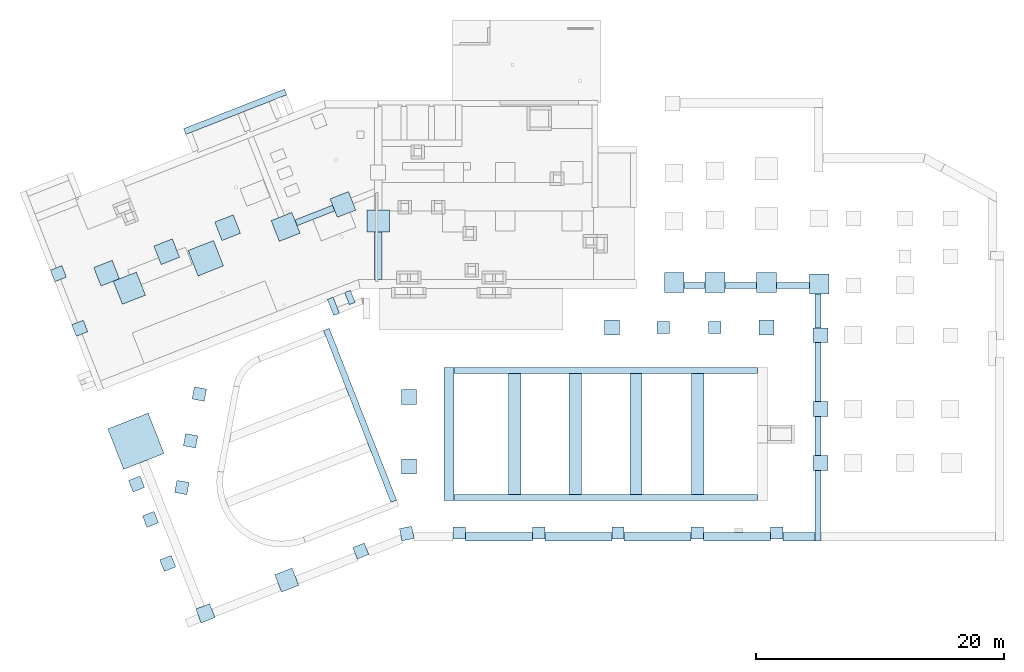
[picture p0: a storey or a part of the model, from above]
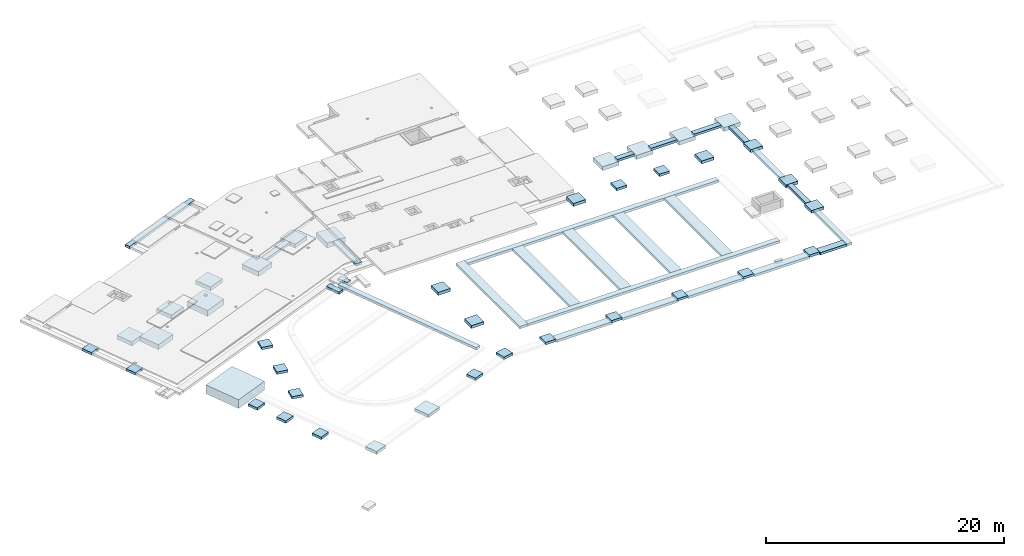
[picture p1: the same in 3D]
Properties of the parts of a building model (IFC2X3), part 1 of 4

# File
Description: no view
File name: L:\EXE\BA\2020\CALLEC\2020 303-Piscine DOULLENS\BET\DIFFUSIONS\IFC\MODELISATION-060921.ifc
Time: 2021-09-06T10:32:10
Author: Marie LEBLOND
Organization: No Organization
Written by: EDMsix Version 2.0100.09 Sep 7 2016
Made in: Allplan 2021.1 05.08.2021 - 11:04:06

# IfcProject, 2020 303 - CALLEC - PISCINE DOULLENS
AllplanAttributes - Modèle de projet: Gabarit; Description du projet: Data-Eng-2018

# IfcSite, Site
RefLatitude: 48, 0, 0, 0; RefLongitude: 0, 0, 0, 0

# IfcBuildingStorey (3)
In: Bâtiments
Name | Elevation (m)
FONDATIONS | -7.1
SOUS-SOL | -5.3
RDC | -0.14

# IfcBeam (139)
AllplanAttributes - Catégorie de transformation: Nouvelle construction; RATIO_HA: 200; Unité: m³; Nom_de_macro: Sous-poutre
Pset_BeamCommon - LoadBearing: yes
Name | In | Material = Matériau | Désignation | Id_élt_Allmétré
PoR 00 | FONDATIONS | Béton | PoR 00 | 0010S-p1612654325
PoR 00 | FONDATIONS | Béton | PoR 00 | 0010S-p1612721315
PoR 00 | SOUS-SOL | Béton | PoR 00 | 0050S-p1612686167
PoR 00 | SOUS-SOL | Béton | PoR 00 | 0050S-p1612686207
PoR 00 | SOUS-SOL | Béton | PoR 00 | 0050S-p1612686236
PoR 00 | SOUS-SOL | Béton | PoR 00 | 0050S-p1612686181
PoR 00 | SOUS-SOL | Béton | PoR 00 | 0050S-p1612686958
PoR 00 | SOUS-SOL | Béton | PoR 00 | 0050S-p1612686986
PoR 00 | SOUS-SOL | Béton | PoR 00 | 0050S-p1612686960
PoR 00 | SOUS-SOL | Béton | PoR 00 | 0050S-p1612686985
PoR 001 | SOUS-SOL | Béton | PoR 001 | 0050S-p1612678472
PoR 002 | SOUS-SOL | Béton | PoR 002 | 0050S-p1612673227
Po 003 | SOUS-SOL | Béton | Po 003 | 0050S-p1612648930
Po 004 | SOUS-SOL | Béton | Po 004 | 0050S-p1612648985
Po 005 | SOUS-SOL | Béton | Po 005 | 0050S-p1612649005
Po 008 | SOUS-SOL | Béton | Po 008 | 0050S-p1612649160
Po 009 | SOUS-SOL | Béton | Po 009 | 0050S-p1612649244
Po 011 | SOUS-SOL | Béton | Po 011 | 0050S-p1612661429
Po 012 | SOUS-SOL | Béton | Po 012 | 0050S-p1612649500
Po 013 | SOUS-SOL | Béton | Po 013 | 0050S-p1612650246
Po 014 | SOUS-SOL | Béton | Po 014 | 0050S-p1612650380
Po 015 | SOUS-SOL | Béton | Po 015 | 0050S-p1612649763
Po 020 | SOUS-SOL | Béton | Po 020 | 0050S-p1612649906
Po 021 | SOUS-SOL | Béton | Po 021 | 0050S-p1612649915
Po 022 | SOUS-SOL | Béton | Po 022 | 0050S-p1612649935
Po 023 | SOUS-SOL | Béton | Po 023 | 0050S-p1612649926
Po 040 | SOUS-SOL | Béton | Po 040 | 0050S-p1612657694
Po 041 | SOUS-SOL | Béton | Po 041 | 0050S-p1612657721
Po 042 | SOUS-SOL | Béton | Po 042 | 0050S-p1612657737
Po 043 | SOUS-SOL | Béton | Po 043 | 0050S-p1612657752
Po 044 | SOUS-SOL | Béton | Po 044 | 0050S-p1612657767
Po 066 | SOUS-SOL | Béton | Po 066 | 0050S-p1612658437
Po 067 | SOUS-SOL | Béton | Po 067 | 0050S-p1612688318
Po 068 | SOUS-SOL | Béton | Po 068 | 0050S-p1612688321
Po 076 | SOUS-SOL | Béton | Po 076 | 0050S-p1612657643
Po 077 | SOUS-SOL | Béton | Po 077 | 0050S-p1612657623
Po 078 | SOUS-SOL | Béton | Po 078 | 0050S-p1612657587
Po 017 | SOUS-SOL | Béton | Po 017 | 0050S-p1612650627
Po 025 | SOUS-SOL | Béton | Po 025 | 0050S-p1612650941
Po 024 | SOUS-SOL | Béton | Po 024 | 0050S-p1612650943
Po 019 | SOUS-SOL | Béton | Po 019 | 0050S-p1612650786
Po 016 | SOUS-SOL | Béton | Po 016 | 0050S-p1612650218
Po 057 | SOUS-SOL | Béton | Po 057 | 0050S-p1612650673
Po 018 | SOUS-SOL | Béton | Po 018 | 0050S-p1612650757
Po 026 | SOUS-SOL | Béton | Po 026 | 0050S-p1612650901
Po 027 | SOUS-SOL | Béton | Po 027 | 0050S-p1612650910
Po 058 | SOUS-SOL | Béton | Po 058 | 0050S-p1612651068
Po 037 | SOUS-SOL | Béton | Po 037 | 0050S-p1612651011
Po 059 | SOUS-SOL | Béton | Po 059 | 0050S-p1612736127
Po 028 | SOUS-SOL | Béton | Po 028 | 0050S-p1612736169
Po 060 | SOUS-SOL | Béton | Po 060 | 0050S-p1612651301
Po 029 | SOUS-SOL | Béton | Po 029 | 0050S-p1612651623
Po 033 | SOUS-SOL | Béton | Po 033 | 0050S-p1612652504
Po 053 | SOUS-SOL | Béton | Po 053 | 0050S-p1612652937
Po 065 | SOUS-SOL | Béton | Po 065 | 0050S-p1612657832
Po 062 | SOUS-SOL | Béton | Po 062 | 0050S-p1612657916
Po 061 | SOUS-SOL | Béton | Po 061 | 0050S-p1612657938
Po 054 | SOUS-SOL | Béton | Po 054 | 0050S-p1612735053
Po 035 | SOUS-SOL | Béton | Po 035 | 0050S-p1612741570
Po 034 | SOUS-SOL | Béton | Po 034 | 0050S-p1612741563
Po 036 | SOUS-SOL | Béton | Po 036 | 0050S-p1612651013
Po 031 | SOUS-SOL | Béton | Po 031 | 0050S-p1612744113
Po 030 | SOUS-SOL | Béton | Po 030 | 0050S-p1612651674
Po 031 | SOUS-SOL | Béton | Po 031 | 0050S-p1612651713
Po 032 | SOUS-SOL | Béton | Po 032 | 0050S-p1612735962
Po 039 | SOUS-SOL | Béton | Po 039 | 0050S-p1612735828
Po 038 | SOUS-SOL | Béton | Po 038 | 0050S-p1612652550
Po 064 | SOUS-SOL | Béton | Po 064 | 0050S-p1612736077
Po 051 | SOUS-SOL | Béton | Po 051 | 0050S-p1612652868
Po 052 | SOUS-SOL | Béton | Po 052 | 0050S-p1612652858
Po 051 | SOUS-SOL | Béton | Po 051 | 0050S-p1612745349
PoR 007 | SOUS-SOL | Béton | PoR 007 | 0050S-p1612647993
PoR 069 | SOUS-SOL | Béton | PoR 069 | 0050S-p1612778632
PoR 069 | SOUS-SOL | Béton | PoR 069 | 0050S-p1612778567
Po 045 | SOUS-SOL | Béton | Po 045 | 0050S-p1612652713
Po 047 | SOUS-SOL | Béton | Po 047 | 0050S-p1612652656
Po 046 | SOUS-SOL | Béton | Po 046 | 0050S-p1612735558
Po 063 | SOUS-SOL | Béton | Po 063 | 0050S-p1612652802
Po 048 | SOUS-SOL | Béton | Po 048 | 0050S-p1612652650
Po 075 | SOUS-SOL | Béton | Po 075 | 0050S-p1612665531
Po 074 | SOUS-SOL | Béton | Po 074 | 0050S-p1612665619
Po 073 | SOUS-SOL | Béton | Po 073 | 0050S-p1612665646
Po 079 | SOUS-SOL | Béton | Po 079 | 0050S-p1612663488
Po 080 | SOUS-SOL | Béton | Po 080 | 0050S-p1612788852
Po 081 | SOUS-SOL |  | Po 081 | 0050S-p1612788903
Po 082 | SOUS-SOL | Béton | Po 082 | 0050S-p1612788969
Po 083 | SOUS-SOL | Béton | Po 083 | 0050S-p1612789005
Po 084 | SOUS-SOL | Béton | Po 084 | 0050S-p1613170464
Po 084 | SOUS-SOL | Béton | Po 084 | 0050S-p1613170500
Po 084 | SOUS-SOL | Béton | Po 084 | 0050S-p1613170613
PoR 00 | SOUS-SOL | Béton | PoR 00 | 0050S-p1612780933
PoR 069 | SOUS-SOL | Béton | PoR 069 | 0050S-p1612778735
Po 085 | SOUS-SOL | Béton | Po 085 | 0050S-p1612788088
PoR 00 | SOUS-SOL | Béton | PoR 00 | 0050S-p1612780318
PoR 00 | SOUS-SOL | Béton | PoR 00 | 0050S-p1612780399
PoR 00 | SOUS-SOL | Béton | PoR 00 | 0050S-p1612780922
PoR 00 | SOUS-SOL | Béton | PoR 00 | 0050S-p1612780363
PoR 00 | SOUS-SOL | Béton | PoR 00 | 0050S-p1612780500
PoR 071 | SOUS-SOL | Béton | PoR 071 | 0050S-p1612778676
Po 084 | SOUS-SOL | Béton | Po 084 | 0050S-p1612787610
PoR 070 | SOUS-SOL | Béton | PoR 070 | 0050S-p1612778614
PoR 072 | SOUS-SOL | Béton | PoR 072 | 0050S-p1612778448
Po 055 | SOUS-SOL | Béton | Po 055 | 0050S-p1612652952
Po 056 | SOUS-SOL | Béton | Po 056 | 0050S-p1613195454
PoR 006 | SOUS-SOL | Béton | PoR 006 | 0050S-p1612647966
Po 086 | SOUS-SOL | Béton | Po 086 | 0050S-p1613203273
PoR 00 | SOUS-SOL | Béton | PoR 00 | 0050S-p1612776846
PoR 00 | SOUS-SOL | Béton | PoR 00 | 0050S-p1612776870
PoR 00 | SOUS-SOL | Béton | PoR 00 | 0050S-p1612776830
Po 010 | SOUS-SOL | Béton | Po 010 | 0050S-p1612661403
Po 050 | SOUS-SOL | Béton | Po 050 | 0050S-p1612735270
Po 049 | SOUS-SOL | Béton | Po 049 | 0050S-p1612652866
Po 087 | SOUS-SOL | Béton | Po 087 | 0050S-p1613204714
PoR 120 | RDC | Béton | PoR 120 | 0100S-p0000007770
Po 112 | RDC | Béton | Po 112 | 0100S-p0000010115
Po 117 | RDC | Béton | Po 117 | 0100S-p0000010028
Po 118 | RDC | Béton | Po 118 | 0100S-p0000010144
Po 116 | RDC | Béton | Po 116 | 0100S-p0000009747
Po 115 | RDC | Béton | Po 115 | 0100S-p0000009762
Po 114 | RDC | Béton | Po 114 | 0100S-p0000009777
Po 113 | RDC | Béton | Po 113 | 0100S-p0000009794
Po 111 | RDC | Béton | Po 111 | 0100S-p0000010074
Po 110 | RDC | Béton | Po 110 | 0100S-p0000009999
Po 109 | RDC | Béton | Po 109 | 0100S-p0000009725
Po 108 | RDC | Béton | Po 108 | 0100S-p0000009710
Po 107 | RDC | Béton | Po 107 | 0100S-p0000009695
Po 106 | RDC | Béton | Po 106 | 0100S-p0000009551
Po 105 | RDC | Béton | Po 105 | 0100S-p0000009680
PoR 126 | RDC | Béton | PoR 126 | 0100S-p0000007630
Po 119 | RDC | Béton | Po 119 | 0100S-p0000010157
PoR 121 | RDC | Béton | PoR 121 | 0100S-p0000010289
PoR 123 | RDC | Béton | PoR 123 | 0100S-p0000008214
PoR 124 | RDC | Béton | PoR 124 | 0100S-p0000008228
PoR 122 | RDC | Béton | PoR 122 | 0100S-p0000007911
PoR 101 | RDC | Béton | PoR 101 | 0100S-p0000014675
PoR 104 | RDC | Béton | PoR 104 | 0100S-p0000009035
PoR 103 | RDC | Béton | PoR 103 | 0100S-p0000008747
PoR 102 | RDC | Béton | PoR 102 | 0100S-p0000008701
PoR 125 | RDC | Béton | PoR 125 | 0100S-p0000009021

# IfcBuildingElementProxy, Cunette
In: FONDATIONS
Material: Béton
AllplanAttributes - Nom_de_macro: Elément d'architecture personnalisé; Désignation: Cunette; Matériau: Béton; Id_élt_Allmétré: 0010élé1612676268; Unité: m³

# IfcColumn (87)
Material: Béton
AllplanAttributes - Catégorie de transformation: Nouvelle construction; Matériau: Béton; RATIO_HA: 15; Unité: m³; Nom_de_macro: Poteau
Pset_ColumnCommon - LoadBearing: no
Name | In | Désignation | Id_élt_Allmétré
Pot 003 | SOUS-SOL | Pot 003 | 0050Pot1612673785
Pot 004 | SOUS-SOL | Pot 004 | 0050Pot1612673797
Pot 005 | SOUS-SOL | Pot 005 | 0050Pot1612647774
Pot 006 | SOUS-SOL | Pot 006 | 0050Pot1612648906
Pot 007 | SOUS-SOL | Pot 007 | 0050Pot1612648918
Pot 008 | SOUS-SOL | Pot 008 | 0050Pot1612649036
Pot 009 | SOUS-SOL | Pot 009 | 0050Pot1612661395
Pot 010 | SOUS-SOL | Pot 010 | 0050Pot1612649441
Pot 011 | SOUS-SOL | Pot 011 | 0050Pot1612649667
Pot 012 | SOUS-SOL | Pot 012 | 0050Pot1612649675
Pot 013 | SOUS-SOL | Pot 013 | 0050Pot1612649684
Pot 017 | SOUS-SOL | Pot 017 | 0050Pot1612649880
Pot 018 | SOUS-SOL | Pot 018 | 0050Pot1612649899
Pot 019 | SOUS-SOL | Pot 019 | 0050Pot1612649920
Pot 020 | SOUS-SOL | Pot 020 | 0050Pot1612649928
Pot 038 | SOUS-SOL | Pot 038 | 0050Pot1612656995
Pot 039 | SOUS-SOL | Pot 039 | 0050Pot1612657006
Pot 040 | SOUS-SOL | Pot 040 | 0050Pot1612657017
Pot 041 | SOUS-SOL | Pot 041 | 0050Pot1612657028
Pot 054 | SOUS-SOL | Pot 054 | 0050Pot1612687138
Pot 056 | SOUS-SOL | Pot 056 | 0050Pot1612687148
Pot 059 | SOUS-SOL | Pot 059 | 0050Pot1612687159
Pot 061 | SOUS-SOL | Pot 061 | 0050Pot1612656981
Pot 062 | SOUS-SOL | Pot 062 | 0050Pot1612687169
Pot 069 | SOUS-SOL | Pot 069 | 0050Pot1612654130
Pot 071 | SOUS-SOL | Pot 071 | 0050Pot1612658227
Pot 014 | SOUS-SOL | Pot 014 | 0050Pot1612650572
Pot 021 | SOUS-SOL | Pot 021 | 0050Pot1612650946
Pot 016 | SOUS-SOL | Pot 016 | 0050Pot1612650749
Pot 015 | SOUS-SOL | Pot 015 | 0050Pot1612650642
Pot 023 | SOUS-SOL | Pot 023 | 0050Pot1612650912
Pot 024 | SOUS-SOL | Pot 024 | 0050Pot1612651312
Pot 034 | SOUS-SOL | Pot 034 | 0050Pot1612651101
Pot 027 | SOUS-SOL | Pot 027 | 0050Pot1612651639
Pot 026 | SOUS-SOL | Pot 026 | 0050Pot1612651436
Pot 025 | SOUS-SOL | Pot 025 | 0050Pot1612651332
Pot 029 | SOUS-SOL | Pot 029 | 0050Pot1612652058
Pot 030 | SOUS-SOL | Pot 030 | 0050Pot1612651933
Pot 035 | SOUS-SOL | Pot 035 | 0050Pot1612651352
Pot 050 | SOUS-SOL | Pot 050 | 0050Pot1612652464
Pot 051 | SOUS-SOL | Pot 051 | 0050Pot1612652427
Pot 052 | SOUS-SOL | Pot 052 | 0050Pot1612652102
Pot 022 | SOUS-SOL | Pot 022 | 0050Pot1612650884
Pot 031 | SOUS-SOL | Pot 031 | 0050Pot1612650978
Pot 032 | SOUS-SOL | Pot 032 | 0050Pot1612650989
Pot 033 | SOUS-SOL | Pot 033 | 0050Pot1612650999
Pot 028 | SOUS-SOL | Pot 028 | 0050Pot1612651648
Pot 037 | SOUS-SOL | Pot 037 | 0050Pot1612652080
Pot 036 | SOUS-SOL | Pot 036 | 0050Pot1612652397
Pot 046 | SOUS-SOL | Pot 046 | 0050Pot1612652453
Pot 047 | SOUS-SOL | Pot 047 | 0050Pot1612652416
Pot 048 | SOUS-SOL | Pot 048 | 0050Pot1612652091
Pot 049 | SOUS-SOL | Pot 049 | 0050Pot1612652026
Pot 065 | SOUS-SOL | Pot 065 | 0050Pot1612654456
Pot 055 | SOUS-SOL | Pot 055 | 0050Pot1612654755
Pot 060 | SOUS-SOL | Pot 060 | 0050Pot1612654726
Pot 063 | SOUS-SOL | Pot 063 | 0050Pot1612654502
Pot 057 | SOUS-SOL | Pot 057 | 0050Pot1612654746
Pot 043 | SOUS-SOL | Pot 043 | 0050Pot1612652405
Pot 042 | SOUS-SOL | Pot 042 | 0050Pot1612652445
Pot 044 | SOUS-SOL | Pot 044 | 0050Pot1612652069
Pot 045 | SOUS-SOL | Pot 045 | 0050Pot1612652015
Pot 067 | SOUS-SOL | Pot 067 | 0050Pot1612654159
Pot 058 | SOUS-SOL | Pot 058 | 0050Pot1612656962
Pot 053 | SOUS-SOL | Pot 053 | 0050Pot1612652037
Pot 001 | SOUS-SOL | Pot 001 | 0050Pot1612647617
Pot 002 | SOUS-SOL | Pot 002 | 0050Pot1612648008
Pot 070 | SOUS-SOL | Pot 070 | 0050Pot1612653755
Pot 068 | SOUS-SOL | Pot 068 | 0050Pot1612654145
Pot 66 | SOUS-SOL | Pot 66 | 0050Pot1612654370
Pot 064 | SOUS-SOL | Pot 064 | 0050Pot1612654488
Pot101 | RDC | Pot101 | 0100Pot0000008467
Pot 102 | RDC | Pot 102 | 0100Pot0000008324
Pot 107 | RDC | Pot 107 | 0100Pot0000009464
Pot 108 | RDC | Pot 108 | 0100Pot0000009481
Pot 109 | RDC | Pot 109 | 0100Pot0000009490
Pot 110 | RDC | Pot 110 | 0100Pot0000009499
Pot 111 | RDC | Pot 111 | 0100Pot0000009508
Pot 112 | RDC | Pot 112 | 0100Pot0000009544
Pot 113 | RDC | Pot 113 | 0100Pot0000009535
Pot 114 | RDC | Pot 114 | 0100Pot0000009526
Pot 115 | RDC | Pot 115 | 0100Pot0000009517
Pot 116 | RDC | Pot 116 | 0100Pot0000024799
Pot 103 | RDC | Pot 103 | 0100Pot0000008482
Pot 104 | RDC | Pot 104 | 0100Pot0000008583
Pot 106 | RDC | Pot 106 | 0100Pot0000008981
Pot 105 | RDC | Pot 105 | 0100Pot0000014546

# IfcElementAssembly (61)
In: Site
AllplanAttributes - Unité: m³; Nom_de_macro: Grille des axes
Name | Id_élt_Allmétré
 | 0008Gri1612633215
 | 0008Gri1612633260
 | 0008Gri1612633269
 | 0008Gri1612633278
 | 0008Gri1612633287
 | 0008Gri1612633296
 | 0008Gri1612633486
 | 0008Gri1612633513
 | 0008Gri1612633540
 | 0008Gri1612633558
 | 0008Gri1612633576
 | 0008Gri1612633594
 | 0008Gri1612633675
 | 0008Gri1612633702
 | 0008Gri1612633729
 | 0008Gri1612633756
 | 0008Gri1612633783
 | 0008Gri1612633810
 | 0008Gri1612633864
 | 0008Gri1612633891
 | 0008Gri1612633909
 | 0008Gri1612633927
 | 0008Gri1612633981
 | 0008Gri1612633999
 | 0008Gri1612634035
 | 0008Gri1612634098
 | 0008Gri1612634252
 | 0008Gri1612634288
 | 0008Gri1612634474
 | 0008Gri1612634522
 | 0008Gri1612634540
 | 0008Gri1612634648
 | 0008Gri1612634730
 | 0008Gri1612634775
 | 0008Gri1612633945
 | 0008Gri1612633837
 | 0008Gri1612634270
 | 0008Gri1612636818
 | 0008Gri1612636827
 | 0008Gri1612636836
 | 0008Gri1612633963
 | 0008Gri1612636854
 | 0008Gri1612636863
 | 0008Gri1612636872
 | 0008Gri1612636881
 | 0008Gri1612636890
 | 0008Gri1612636917
 | 0008Gri1612636926
 | 0008Gri1612636935
 | 0008Gri1612636953
 | 0008Gri1612636998
 | 0008Gri1612637007
 | 0008Gri1612637016
 | 0008Gri1612636899
 | 0008Gri1612637025
 | 0008Gri1612637034
 | 0008Gri1612637052
 | 0008Gri1612637115
 | 0008Gri1612637150
 | 0008Gri1612637159
 | 0008Gri1612638170

# IfcFooting (154)
In: FONDATIONS
Material: Béton
AllplanAttributes - Matériau: Béton
Pset_FootingCommon - Status: Nouvelle construction; LoadBearing: no
Name | PredefinedType | Désignation | RATIO_HA | Id_élt_Allmétré | Unité | Nom_de_macro
SF006 | STRIP_FOOTING | SF006 | 50 | 0010SeF1612651470 | m | Semelle filante
SF006 | STRIP_FOOTING | SF006 | 50 | 0010SeF1612651531 | m | Semelle filante
SF006 | STRIP_FOOTING | SF006 | 50 | 0010SeF1612651554 | m | Semelle filante
M002-A | PAD_FOOTING | M002-A |  | 0010SeI1612652197 | m³ | Semelle isolée
M002-A | PAD_FOOTING | M002-A |  | 0010SeI1612652175 | m³ | Semelle isolée
M002-A | PAD_FOOTING | M002-A |  | 0010SeI1612652164 | m³ | Semelle isolée
M004-C | PAD_FOOTING | M004-C |  | 0010SeI1612652083 | m³ | Semelle isolée
M004-C | PAD_FOOTING | M004-C |  | 0010SeI1612652070 | m³ | Semelle isolée
M007-A | PAD_FOOTING | M007-A |  | 0010SeI1612651798 | m³ | Semelle isolée
SF006 | STRIP_FOOTING | SF006 | 50 | 0010SeF1612650997 | m | Semelle filante
SF006 | STRIP_FOOTING | SF006 | 50 | 0010SeF1612653563 | m | Semelle filante
SF001 | STRIP_FOOTING | SF001 | 50 | 0010SeF1612651608 | m | Semelle filante
SF001 | STRIP_FOOTING | SF001 | 50 | 0010SeF1612652292 | m | Semelle filante
SF001 | STRIP_FOOTING | SF001 | 50 | 0010SeF1612652274 | m | Semelle filante
SF001 | STRIP_FOOTING | SF001 | 50 | 0010SeF1612652254 | m | Semelle filante
SF001 | STRIP_FOOTING | SF001 | 50 | 0010SeF1612652774 | m | Semelle filante
SF001 | STRIP_FOOTING | SF001 | 50 | 0010SeF1612652627 | m | Semelle filante
SF003-A | STRIP_FOOTING | SF003-A | 50 | 0010SeF1612652830 | m | Semelle filante
SF001 | STRIP_FOOTING | SF001 | 50 | 0010SeF1612652680 | m | Semelle filante
SF003-A | STRIP_FOOTING | SF003-A | 50 | 0010SeF1612652820 | m | Semelle filante
SF001 | STRIP_FOOTING | SF001 | 50 | 0010SeF1612652618 | m | Semelle filante
SF001 | STRIP_FOOTING | SF001 | 50 | 0010SeF1612652717 | m | Semelle filante
SF001 | STRIP_FOOTING | SF001 | 50 | 0010SeF1612652643 | m | Semelle filante
SF006 | STRIP_FOOTING | SF006 | 50 | 0010SeF1612651762 | m | Semelle filante
SF006 | STRIP_FOOTING | SF006 | 50 | 0010SeF1612653541 | m | Semelle filante
SF006 | STRIP_FOOTING | SF006 | 50 | 0010SeF1612653519 | m | Semelle filante
SF006 | STRIP_FOOTING | SF006 | 50 | 0010SeF1612653496 | m | Semelle filante
SF006 | STRIP_FOOTING | SF006 | 50 | 0010SeF1612653474 | m | Semelle filante
SF006 | STRIP_FOOTING | SF006 | 50 | 0010SeF1612652485 | m | Semelle filante
SF006 | STRIP_FOOTING | SF006 | 50 | 0010SeF1612652510 | m | Semelle filante
SF006 | STRIP_FOOTING | SF006 | 50 | 0010SeF1612652528 | m | Semelle filante
SF006 | STRIP_FOOTING | SF006 | 50 | 0010SeF1612652546 | m | Semelle filante
SF006 | STRIP_FOOTING | SF006 | 50 | 0010SeF1612652560 | m | Semelle filante
M001-E | PAD_FOOTING | M001-E |  | 0010SeI1612653432 | m³ | Semelle isolée
M001-E | PAD_FOOTING | M001-E |  | 0010SeI1612653421 | m³ | Semelle isolée
M001-E | PAD_FOOTING | M001-E |  | 0010SeI1612653410 | m³ | Semelle isolée
M001-E | PAD_FOOTING | M001-E |  | 0010SeI1612653398 | m³ | Semelle isolée
M001-E | PAD_FOOTING | M001-E |  | 0010SeI1612653388 | m³ | Semelle isolée
M001-E | PAD_FOOTING | M001-E |  | 0010SeI1612665969 | m³ | Semelle isolée
M001-E | PAD_FOOTING | M001-E |  | 0010SeI1612652443 | m³ | Semelle isolée
M002-A | PAD_FOOTING | M002-A |  | 0010SeI1612666058 | m³ | Semelle isolée
M007-A | PAD_FOOTING | M007-A |  | 0010SeI1612651811 | m³ | Semelle isolée
M007-B | PAD_FOOTING | M007-B |  | 0010SeI1612652023 | m³ | Semelle isolée
M007-C | PAD_FOOTING | M007-C |  | 0010SeI1612652035 | m³ | Semelle isolée
M007-D | PAD_FOOTING | M007-D |  | 0010SeI1612651822 | m³ | Semelle isolée
M003-C | PAD_FOOTING | M003-C |  | 0010SeI1612652208 | m³ | Semelle isolée
M001-D | PAD_FOOTING | M001-D |  | 0010SeI1612653341 | m³ | Semelle isolée
M002-A | PAD_FOOTING | M002-A |  | 0010SeI1612653330 | m³ | Semelle isolée
M001-D | PAD_FOOTING | M001-D |  | 0010SeI1612653352 | m³ | Semelle isolée
M002-A | PAD_FOOTING | M002-A |  | 0010SeI1612653363 | m³ | Semelle isolée
M002-A | PAD_FOOTING | M002-A |  | 0010SeI1612652138 | m³ | Semelle isolée
M002-A | PAD_FOOTING | M002-A |  | 0010SeI1612652151 | m³ | Semelle isolée
M002-A | PAD_FOOTING | M002-A |  | 0010SeI1612652186 | m³ | Semelle isolée
M002-A | PAD_FOOTING | M002-A |  | 0010SeI1612652219 | m³ | Semelle isolée
M002-A | PAD_FOOTING | M002-A |  | 0010SeI1612652232 | m³ | Semelle isolée
M002-A | PAD_FOOTING | M002-A |  | 0010SeI1612652243 | m³ | Semelle isolée
M001-D | PAD_FOOTING | M001-D |  | 0010SeI1612652336 | m³ | Semelle isolée
M007-E | PAD_FOOTING | M007-E |  | 0010SeI1612651833 | m³ | Semelle isolée
M007-E | PAD_FOOTING | M007-E |  | 0010SeI1612651855 | m³ | Semelle isolée
M007-E | PAD_FOOTING | M007-E |  | 0010SeI1612651844 | m³ | Semelle isolée
M007-E | PAD_FOOTING | M007-E |  | 0010SeI1612651899 | m³ | Semelle isolée
M007-E | PAD_FOOTING | M007-E |  | 0010SeI1612651910 | m³ | Semelle isolée
M007-E | PAD_FOOTING | M007-E |  | 0010SeI1612651866 | m³ | Semelle isolée
M007-E | PAD_FOOTING | M007-E |  | 0010SeI1612651888 | m³ | Semelle isolée
M007-E | PAD_FOOTING | M007-E |  | 0010SeI1612651877 | m³ | Semelle isolée
M003-B | PAD_FOOTING | M003-B |  | 0010SeI1612651921 | m³ | Semelle isolée
M002-A | PAD_FOOTING | M002-A |  | 0010SeI1612653308 | m³ | Semelle isolée
M002-A | PAD_FOOTING | M002-A |  | 0010SeI1612653319 | m³ | Semelle isolée
M001-C | PAD_FOOTING | M001-C |  | 0010SeI1612652575 | m³ | Semelle isolée
M001-C | PAD_FOOTING | M001-C |  | 0010SeI1612652607 | m³ | Semelle isolée
M009 | PAD_FOOTING | M009 |  | 0010SeI1612652427 | m³ | Semelle isolée
M008 | PAD_FOOTING | M008 |  | 0010SeI1612652396 | m³ | Semelle isolée
M001-C | PAD_FOOTING | M001-C |  | 0010SeI1612652596 | m³ | Semelle isolée
M001-C | PAD_FOOTING | M001-C |  | 0010SeI1612653628 | m³ | Semelle isolée
M001-C | PAD_FOOTING | M001-C |  | 0010SeI1612653641 | m³ | Semelle isolée
M001-C | PAD_FOOTING | M001-C |  | 0010SeI1612653652 | m³ | Semelle isolée
M003-B | PAD_FOOTING | M003-B |  | 0010SeI1612651976 | m³ | Semelle isolée
M003-B | PAD_FOOTING | M003-B |  | 0010SeI1612651965 | m³ | Semelle isolée
M003-B | PAD_FOOTING | M003-B |  | 0010SeI1612651934 | m³ | Semelle isolée
M010 | PAD_FOOTING | M010 |  | 0010SeI1612666026 | m³ | Semelle isolée
SF001 | STRIP_FOOTING | SF001 | 50 | 0010SeF1612650064 | m | Semelle filante
SF001 | STRIP_FOOTING | SF001 | 50 | 0010SeF1612650013 | m | Semelle filante
SF001 | STRIP_FOOTING | SF001 | 50 | 0010SeF1612650039 | m | Semelle filante
SF001 | STRIP_FOOTING | SF001 | 50 | 0010SeF1612650052 | m | Semelle filante
SF001 | STRIP_FOOTING | SF001 | 50 | 0010SeF1612649396 | m | Semelle filante
SF002 | STRIP_FOOTING | SF002 | 50 | 0010SeF1612650516 | m | Semelle filante
SF002 | STRIP_FOOTING | SF002 | 50 | 0010SeF1612708971 | m | Semelle filante
SF002 | STRIP_FOOTING | SF002 | 50 | 0010SeF1612656001 | m | Semelle filante
SF001 | STRIP_FOOTING | SF001 | 50 | 0010SeF1612648638 | m | Semelle filante
SF001 | STRIP_FOOTING | SF001 | 50 | 0010SeF1612648993 | m | Semelle filante
SF001 | STRIP_FOOTING | SF001 | 50 | 0010SeF1612648941 | m | Semelle filante
SF001 | STRIP_FOOTING | SF001 | 50 | 0010SeF1612664343 | m | Semelle filante
SF006 | STRIP_FOOTING | SF006 | 50 | 0010SeF1612653584 | m | Semelle filante
SF001 | STRIP_FOOTING | SF001 | 50 | 0010SeF1612649152 | m | Semelle filante
SF001 | STRIP_FOOTING | SF001 | 50 | 0010SeF1612649073 | m | Semelle filante
SF001 | STRIP_FOOTING | SF001 | 50 | 0010SeF1612650729 | m | Semelle filante
SF001 | STRIP_FOOTING | SF001 | 50 | 0010SeF1612650741 | m | Semelle filante
SF001 | STRIP_FOOTING | SF001 | 50 | 0010SeF1612650754 | m | Semelle filante
SF001 | STRIP_FOOTING | SF001 | 50 | 0010SeF1612650817 | m | Semelle filante
SF002 | STRIP_FOOTING | SF002 | 50 | 0010SeF1612650541 | m | Semelle filante
SF001 | STRIP_FOOTING | SF001 | 50 | 0010SeF1612650166 | m | Semelle filante
SF002 | STRIP_FOOTING | SF002 | 50 | 0010SeF1612648480 | m | Semelle filante
SF001 | STRIP_FOOTING | SF001 | 50 | 0010SeF1612650233 | m | Semelle filante
SF001 | STRIP_FOOTING | SF001 | 50 | 0010SeF1612650082 | m | Semelle filante
SF001 | STRIP_FOOTING | SF001 | 50 | 0010SeF1612653696 | m | Semelle filante
SF001 | STRIP_FOOTING | SF001 | 50 | 0010SeF1612653708 | m | Semelle filante
SF001 | STRIP_FOOTING | SF001 | 50 | 0010SeF1612653663 | m | Semelle filante
SF001 | STRIP_FOOTING | SF001 | 50 | 0010SeF1612649705 | m | Semelle filante
SF001 | STRIP_FOOTING | SF001 | 50 | 0010SeF1612650722 | m | Semelle filante
SF003-B | STRIP_FOOTING | SF003-B | 50 | 0010SeF1612649238 | m | Semelle filante
SF003-B | STRIP_FOOTING | SF003-B | 50 | 0010SeF1612649431 | m | Semelle filante
SF001 | STRIP_FOOTING | SF001 | 50 | 0010SeF1612659269 | m | Semelle filante
SF001 | STRIP_FOOTING | SF001 | 50 | 0010SeF1612648887 | m | Semelle filante
SF002 | STRIP_FOOTING | SF002 | 50 | 0010SeF1612648829 | m | Semelle filante
SF001 | STRIP_FOOTING | SF001 | 50 | 0010SeF1612649362 | m | Semelle filante
SF001 | STRIP_FOOTING | SF001 | 50 | 0010SeF1612649766 | m | Semelle filante
SF001 | STRIP_FOOTING | SF001 | 50 | 0010SeF1612648390 | m | Semelle filante
M001-B | PAD_FOOTING | M001-B |  | 0010SeI1612650144 | m³ | Semelle isolée | AllplanAttributes - Gousset à gauche: 100; Gousset à droite: 100; Gousset à l'avant: 100; Gousset à l'arrière: 100
M001-B | PAD_FOOTING | M001-B |  | 0010SeI1612650216 | m³ | Semelle isolée
M005 | PAD_FOOTING | M005 |  | 0010SeI1612650132 | m³ | Semelle isolée
M006 | PAD_FOOTING | M006 |  | 0010SeI1612650262 | m³ | Semelle isolée
M003-A | PAD_FOOTING | M003-A |  | 0010SeI1612650962 | m³ | Semelle isolée
M003-A | PAD_FOOTING | M003-A |  | 0010SeI1612650971 | m³ | Semelle isolée
M003-A | PAD_FOOTING | M003-A |  | 0010SeI1612650980 | m³ | Semelle isolée
M004-A | PAD_FOOTING | M004-A |  | 0010SeI1612650277 | m³ | Semelle isolée
M003-D | PAD_FOOTING | M003-D |  | 0010SeI1612650318 | m³ | Semelle isolée
M004-D | PAD_FOOTING | M004-D |  | 0010SeI1612650371 | m³ | Semelle isolée
M002-B | PAD_FOOTING | M002-B |  | 0010SeI1612650359 | m³ | Semelle isolée
M004-B | PAD_FOOTING | M004-B |  | 0010SeI1612650438 | m³ | Semelle isolée
M004-B | PAD_FOOTING | M004-B |  | 0010SeI1612650427 | m³ | Semelle isolée
M003-A | PAD_FOOTING | M003-A |  | 0010SeI1612650391 | m³ | Semelle isolée
M003-A | PAD_FOOTING | M003-A |  | 0010SeI1612650418 | m³ | Semelle isolée
M003-A | PAD_FOOTING | M003-A |  | 0010SeI1612650409 | m³ | Semelle isolée
M003-A | PAD_FOOTING | M003-A |  | 0010SeI1612650400 | m³ | Semelle isolée
SF001 | STRIP_FOOTING | SF001 | 50 | 0010SeF1612652005 | m | Semelle filante
SF001 | STRIP_FOOTING | SF001 | 50 | 0010SeF1612651951 | m | Semelle filante
SF001 | STRIP_FOOTING | SF001 | 50 | 0010SeF1612651986 | m | Semelle filante
SF006 | STRIP_FOOTING | SF006 | 50 | 0010SeF1612651423 | m | Semelle filante
SF006 | STRIP_FOOTING | SF006 | 50 | 0010SeF1612651394 | m | Semelle filante
SF006 | STRIP_FOOTING | SF006 | 50 | 0010SeF1612651298 | m | Semelle filante
SF006 | STRIP_FOOTING | SF006 | 50 | 0010SeF1612664112 | m | Semelle filante
SF006 | STRIP_FOOTING | SF006 | 50 | 0010SeF1612651288 | m | Semelle filante
SF006 | STRIP_FOOTING | SF006 | 50 | 0010SeF1612651209 | m | Semelle filante
SF006 | STRIP_FOOTING | SF006 | 50 | 0010SeF1612651357 | m | Semelle filante
SF001 | STRIP_FOOTING | SF001 | 50 | 0010SeF1612653010 | m | Semelle filante
SF001 | STRIP_FOOTING | SF001 | 50 | 0010SeF1612653000 | m | Semelle filante
SF004 | STRIP_FOOTING | SF004 | 50 | 0010SeF1612653020 | m | Semelle filante
SF005 | STRIP_FOOTING | SF005 | 50 | 0010SeF1612653207 | m | Semelle filante
SF005 | STRIP_FOOTING | SF005 | 50 | 0010SeF1612653259 | m | Semelle filante
SF005 | STRIP_FOOTING | SF005 | 50 | 0010SeF1612653274 | m | Semelle filante
SF005 | STRIP_FOOTING | SF005 | 50 | 0010SeF1612653288 | m | Semelle filante
SF004 | STRIP_FOOTING | SF004 | 50 | 0010SeF1612653184 | m | Semelle filante
SF004 | STRIP_FOOTING | SF004 | 50 | 0010SeF1612719133 | m | Semelle filante
SF001 | STRIP_FOOTING | SF001 | 50 | 0010SeF1612648498 | m | Semelle filante

# IfcOpeningElement: Opening (1065)
Name | In | Object Layer Attributes #1, Catégorie de transformation | Object Layer Attributes #1, Métier | Object Layer Attributes #1, Id_élt_Allmétré | Object Layer Attributes #1, Unité | Object Layer Attributes #1, Nom_de_macro
Résa. | FONDATIONS | Nouvelle construction | Maçonnerie | 0010PeM1612676312 | m³ | Percement dans un mur | AllplanAttributes - Object Layer Attributes #1, Désignation: Résa.
Trémie dans dalle | FONDATIONS | Nouvelle construction |  | 0010TrD1612668609 | m³ | Trémie | AllplanAttributes - Object Layer Attributes #1, Matériau: Dalle_BA; Object Layer Attributes #1, structure_porteur: yes
Trémie dans dalle | FONDATIONS | Nouvelle construction |  | 0010TrD1612676138 | m³ | Trémie
Trémie dans dalle | FONDATIONS | Nouvelle construction |  | 0010TrD1612676131 | m³ | Trémie
Trémie dans dalle | FONDATIONS | Nouvelle construction |  | 0010TrD1612675832 | m³ | Trémie
Trémie dans dalle | FONDATIONS | Nouvelle construction |  | 0010TrD1612675840 | m³ | Trémie
Trémie dans dalle | FONDATIONS | Nouvelle construction |  | 0010TrD1612675825 | m³ | Trémie
Trémie dans dalle | FONDATIONS | Nouvelle construction |  | 0010TrD1612675818 | m³ | Trémie
Trémie dans dalle | FONDATIONS | Nouvelle construction |  | 0010TrD1612673805 | m³ | Trémie
Trémie dans dalle | FONDATIONS | Nouvelle construction |  | 0010TrD1612689277 | m³ | Trémie
Trémie dans dalle | FONDATIONS | Nouvelle construction |  | 0010TrD1612710010 | m³ | Trémie
Trémie dans dalle | FONDATIONS | Nouvelle construction |  | 0010TrD1612710000 | m³ | Trémie
Trémie dans dalle | FONDATIONS | Nouvelle construction |  | 0010TrD1612710005 | m³ | Trémie
Trémie dans dalle | FONDATIONS | Nouvelle construction |  | 0010TrD1612710017 | m³ | Trémie
Trémie dans dalle | FONDATIONS | Nouvelle construction |  | 0010TrD1612710335 | m³ | Trémie
Trémie dans dalle | FONDATIONS | Nouvelle construction |  | 0010TrD1612710074 | m³ | Trémie
Trémie dans dalle | FONDATIONS | Nouvelle construction |  | 0010TrD1612710297 | m³ | Trémie
Trémie dans dalle | FONDATIONS | Nouvelle construction |  | 0010TrD1612709995 | m³ | Trémie
Trémie dans dalle | FONDATIONS | Nouvelle construction |  | 0010TrD1612709990 | m³ | Trémie
Trémie dans dalle | FONDATIONS | Nouvelle construction |  | 0010TrD1612709985 | m³ | Trémie
Trémie dans dalle | FONDATIONS | Nouvelle construction |  | 0010TrD1612709660 | m³ | Trémie
Trémie dans dalle | FONDATIONS | Nouvelle construction |  | 0010TrD1612720826 | m³ | Trémie
Trémie dans dalle | FONDATIONS | Nouvelle construction |  | 0010TrD1612706906 | m³ | Trémie
Trémie dans dalle | FONDATIONS | Nouvelle construction |  | 0010TrD1612706894 | m³ | Trémie
Trémie dans dalle | FONDATIONS | Nouvelle construction |  | 0010TrD1612689319 | m³ | Trémie
Trémie dans dalle | FONDATIONS | Nouvelle construction |  | 0010TrD1612665962 | m³ | Trémie | AllplanAttributes - Object Layer Attributes #1, Matériau: Trémie; Object Layer Attributes #1, structure_porteur: no
Trémie dans dalle | FONDATIONS | Nouvelle construction |  | 0010TrD1612656506 | m³ | Trémie | AllplanAttributes - Object Layer Attributes #1, Matériau: Trémie; Object Layer Attributes #1, structure_porteur: no
Trémie dans dalle | FONDATIONS | Nouvelle construction |  | 0010TrD1612676103 | m³ | Trémie
Trémie dans dalle | FONDATIONS | Nouvelle construction |  | 0010TrD1612676110 | m³ | Trémie
Trémie dans dalle | FONDATIONS | Nouvelle construction |  | 0010TrD1612676117 | m³ | Trémie
Trémie dans dalle | FONDATIONS | Nouvelle construction |  | 0010TrD1612676124 | m³ | Trémie
Trémie dans dalle | FONDATIONS | Nouvelle construction |  | 0010TrD1612689294 | m³ | Trémie
Trémie dans dalle | FONDATIONS | Nouvelle construction |  | 0010TrD1612709317 | m³ | Trémie
CVC-011 | SOUS-SOL | Nouvelle construction | Maçonnerie | 0050PeM1612695766 | m³ | Percement dans un mur | AllplanAttributes - Object Layer Attributes #1, Désignation: CVC-011
Incorp. TE-019 | SOUS-SOL | Nouvelle construction | Maçonnerie | 0050PeM1613177163 | m³ | Percement dans un mur | AllplanAttributes - Object Layer Attributes #1, Désignation: Incorp. TE-019
Incorp.TE-018 | SOUS-SOL | Nouvelle construction | Maçonnerie | 0050PeM1613177093 | m³ | Percement dans un mur | AllplanAttributes - Object Layer Attributes #1, Désignation: Incorp.TE-018
Incorp. TE-020 | SOUS-SOL | Nouvelle construction | Maçonnerie | 0050PeM1613177200 | m³ | Percement dans un mur | AllplanAttributes - Object Layer Attributes #1, Désignation: Incorp. TE-020
Trappe | SOUS-SOL | Nouvelle construction | Maçonnerie | 0050PeM1612687194 | m³ | Percement dans un mur | AllplanAttributes - Object Layer Attributes #1, Désignation: Trappe
EL-001 | SOUS-SOL | Nouvelle construction | Maçonnerie | 0050PeM1612715001 | m³ | Percement dans un mur | AllplanAttributes - Object Layer Attributes #1, Désignation: EL-001
CVC-086 | SOUS-SOL | Nouvelle construction | Maçonnerie | 0050PeM1612697721 | m³ | Percement dans un mur | AllplanAttributes - Object Layer Attributes #1, Désignation: CVC-086
CVC-085 | SOUS-SOL | Nouvelle construction | Maçonnerie | 0050PeM1612697685 | m³ | Percement dans un mur | AllplanAttributes - Object Layer Attributes #1, Désignation: CVC-085
CVC-084 | SOUS-SOL | Nouvelle construction | Maçonnerie | 0050PeM1612697656 | m³ | Percement dans un mur | AllplanAttributes - Object Layer Attributes #1, Désignation: CVC-084
Baie de porte | SOUS-SOL | Nouvelle construction | Béton et béton armé | 0050Por1612723282 | m³ | Baie de porte | AllplanAttributes - Object Layer Attributes #1, Mode_d'ouverture_porte: DIN L
CVC-081 | SOUS-SOL | Nouvelle construction | Maçonnerie | 0050PeM1612697521 | m³ | Percement dans un mur | AllplanAttributes - Object Layer Attributes #1, Désignation: CVC-081
CVC-080 | SOUS-SOL | Nouvelle construction | Maçonnerie | 0050PeM1612697527 | m³ | Percement dans un mur | AllplanAttributes - Object Layer Attributes #1, Désignation: CVC-080
CVC-083 | SOUS-SOL | Nouvelle construction | Maçonnerie | 0050PeM1612697584 | m³ | Percement dans un mur | AllplanAttributes - Object Layer Attributes #1, Désignation: CVC-083
CVC-082 | SOUS-SOL | Nouvelle construction | Maçonnerie | 0050PeM1612697517 | m³ | Percement dans un mur | AllplanAttributes - Object Layer Attributes #1, Désignation: CVC-082
TE-027 | SOUS-SOL | Nouvelle construction | Maçonnerie | 0050PeM1612703368 | m³ | Percement dans un mur | AllplanAttributes - Object Layer Attributes #1, Désignation: TE-027
CVC-078 | SOUS-SOL | Nouvelle construction | Maçonnerie | 0050PeM1612697542 | m³ | Percement dans un mur | AllplanAttributes - Object Layer Attributes #1, Désignation: CVC-078
CVC-079 | SOUS-SOL | Nouvelle construction | Maçonnerie | 0050PeM1612697533 | m³ | Percement dans un mur | AllplanAttributes - Object Layer Attributes #1, Désignation: CVC-079
CVC-012 | SOUS-SOL | Nouvelle construction | Maçonnerie | 0050PeM1612695615 | m³ | Percement dans un mur | AllplanAttributes - Object Layer Attributes #1, Désignation: CVC-012
TE-030 | SOUS-SOL | Nouvelle construction | Maçonnerie | 0050PeM1612702965 | m³ | Percement dans un mur | AllplanAttributes - Object Layer Attributes #1, Désignation: TE-030
CVC-001 | SOUS-SOL | Nouvelle construction | Maçonnerie | 0050PeM1612687253 | m³ | Percement dans un mur | AllplanAttributes - Object Layer Attributes #1, Désignation: CVC-001
CVC-002 | SOUS-SOL | Nouvelle construction | Maçonnerie | 0050PeM1612695169 | m³ | Percement dans un mur | AllplanAttributes - Object Layer Attributes #1, Désignation: CVC-002
CVC-008 | SOUS-SOL | Nouvelle construction | Maçonnerie | 0050PeM1612695992 | m³ | Percement dans un mur | AllplanAttributes - Object Layer Attributes #1, Désignation: CVC-008
CVC-009 | SOUS-SOL | Nouvelle construction | Maçonnerie | 0050PeM1612696043 | m³ | Percement dans un mur | AllplanAttributes - Object Layer Attributes #1, Désignation: CVC-009
CVC-003 | SOUS-SOL | Nouvelle construction | Maçonnerie | 0050PeM1612695817 | m³ | Percement dans un mur | AllplanAttributes - Object Layer Attributes #1, Désignation: CVC-003
CVC-004 | SOUS-SOL | Nouvelle construction | Maçonnerie | 0050PeM1612695859 | m³ | Percement dans un mur | AllplanAttributes - Object Layer Attributes #1, Désignation: CVC-004
CVC-005 | SOUS-SOL | Nouvelle construction | Maçonnerie | 0050PeM1612695915 | m³ | Percement dans un mur | AllplanAttributes - Object Layer Attributes #1, Désignation: CVC-005
CVC-006 | SOUS-SOL | Nouvelle construction | Maçonnerie | 0050PeM1612695945 | m³ | Percement dans un mur | AllplanAttributes - Object Layer Attributes #1, Désignation: CVC-006
Baie de porte | SOUS-SOL | Nouvelle construction | Béton et béton armé | 0050Por1612723156 | m³ | Baie de porte | AllplanAttributes - Object Layer Attributes #1, Mode_d'ouverture_porte: DIN L
CVC-007 | SOUS-SOL | Nouvelle construction | Maçonnerie | 0050PeM1612695974 | m³ | Percement dans un mur | AllplanAttributes - Object Layer Attributes #1, Désignation: CVC-007
CVC-013 | SOUS-SOL | Nouvelle construction | Maçonnerie | 0050PeM1612696153 | m³ | Percement dans un mur | AllplanAttributes - Object Layer Attributes #1, Désignation: CVC-013
CVC-014 | SOUS-SOL | Nouvelle construction | Maçonnerie | 0050PeM1612696085 | m³ | Percement dans un mur | AllplanAttributes - Object Layer Attributes #1, Désignation: CVC-014
PB-033 | SOUS-SOL | Nouvelle construction | Maçonnerie | 0050PeM1612712724 | m³ | Percement dans un mur | AllplanAttributes - Object Layer Attributes #1, Désignation: PB-033
PB-040 | SOUS-SOL | Nouvelle construction | Maçonnerie | 0050PeM1612712791 | m³ | Percement dans un mur | AllplanAttributes - Object Layer Attributes #1, Désignation: PB-040
CVC-015 | SOUS-SOL | Nouvelle construction | Maçonnerie | 0050PeM1612696256 | m³ | Percement dans un mur | AllplanAttributes - Object Layer Attributes #1, Désignation: CVC-015
CVC-018 | SOUS-SOL | Nouvelle construction | Maçonnerie | 0050PeM1612696172 | m³ | Percement dans un mur | AllplanAttributes - Object Layer Attributes #1, Désignation: CVC-018
CVC-017 | SOUS-SOL | Nouvelle construction | Maçonnerie | 0050PeM1612696208 | m³ | Percement dans un mur | AllplanAttributes - Object Layer Attributes #1, Désignation: CVC-017
CVC-016 | SOUS-SOL | Nouvelle construction | Maçonnerie | 0050PeM1612696225 | m³ | Percement dans un mur | AllplanAttributes - Object Layer Attributes #1, Désignation: CVC-016
PB-050 | SOUS-SOL | Nouvelle construction | Maçonnerie | 0050PeM1612712808 | m³ | Percement dans un mur | AllplanAttributes - Object Layer Attributes #1, Désignation: PB-050
PB-052 | SOUS-SOL | Nouvelle construction | Maçonnerie | 0050PeM1612712852 | m³ | Percement dans un mur | AllplanAttributes - Object Layer Attributes #1, Désignation: PB-052
PB-043 | SOUS-SOL | Nouvelle construction | Maçonnerie | 0050PeM1612712883 | m³ | Percement dans un mur | AllplanAttributes - Object Layer Attributes #1, Désignation: PB-043
Baie de porte | SOUS-SOL | Nouvelle construction | Béton et béton armé | 0050Por1612723148 | m³ | Baie de porte | AllplanAttributes - Object Layer Attributes #1, Mode_d'ouverture_porte: DIN R
TE-030 | SOUS-SOL | Nouvelle construction | Maçonnerie | 0050PeM1612703617 | m³ | Percement dans un mur | AllplanAttributes - Object Layer Attributes #1, Désignation: TE-030
PB-023 | SOUS-SOL | Nouvelle construction | Maçonnerie | 0050PeM1612710799 | m³ | Percement dans un mur | AllplanAttributes - Object Layer Attributes #1, Désignation: PB-023
TE-028 | SOUS-SOL | Nouvelle construction | Maçonnerie | 0050PeM1612703460 | m³ | Percement dans un mur | AllplanAttributes - Object Layer Attributes #1, Désignation: TE-028
PB-025 | SOUS-SOL | Nouvelle construction | Maçonnerie | 0050PeM1612710882 | m³ | Percement dans un mur | AllplanAttributes - Object Layer Attributes #1, Désignation: PB-025
TE-029 | SOUS-SOL | Nouvelle construction | Maçonnerie | 0050PeM1612703489 | m³ | Percement dans un mur | AllplanAttributes - Object Layer Attributes #1, Désignation: TE-029
PB-024 | SOUS-SOL | Nouvelle construction | Maçonnerie | 0050PeM1612710842 | m³ | Percement dans un mur | AllplanAttributes - Object Layer Attributes #1, Désignation: PB-024
Baie de porte | SOUS-SOL | Nouvelle construction | Béton et béton armé | 0050Por1612723122 | m³ | Baie de porte | AllplanAttributes - Object Layer Attributes #1, Mode_d'ouverture_porte: DIN R
TE-020 | SOUS-SOL | Nouvelle construction | Maçonnerie | 0050PeM1612703508 | m³ | Percement dans un mur | AllplanAttributes - Object Layer Attributes #1, Désignation: TE-020
PB-030 | SOUS-SOL | Nouvelle construction | Maçonnerie | 0050PeM1612710995 | m³ | Percement dans un mur | AllplanAttributes - Object Layer Attributes #1, Désignation: PB-030
PB-029 | SOUS-SOL | Nouvelle construction | Maçonnerie | 0050PeM1612710954 | m³ | Percement dans un mur | AllplanAttributes - Object Layer Attributes #1, Désignation: PB-029
PB-028 | SOUS-SOL | Nouvelle construction | Maçonnerie | 0050PeM1612710923 | m³ | Percement dans un mur | AllplanAttributes - Object Layer Attributes #1, Désignation: PB-028
Baie de porte | SOUS-SOL | Nouvelle construction | Béton et béton armé | 0050Por1612723132 | m³ | Baie de porte | AllplanAttributes - Object Layer Attributes #1, Mode_d'ouverture_porte: DIN R
CVC-077 | SOUS-SOL | Nouvelle construction | Maçonnerie | 0050PeM1612697010 | m³ | Percement dans un mur | AllplanAttributes - Object Layer Attributes #1, Désignation: CVC-077
CVC-076 | SOUS-SOL | Nouvelle construction | Maçonnerie | 0050PeM1612696992 | m³ | Percement dans un mur | AllplanAttributes - Object Layer Attributes #1, Désignation: CVC-076
CVC-075 | SOUS-SOL | Nouvelle construction | Maçonnerie | 0050PeM1612696979 | m³ | Percement dans un mur | AllplanAttributes - Object Layer Attributes #1, Désignation: CVC-075
CVC-074 | SOUS-SOL | Nouvelle construction | Maçonnerie | 0050PeM1612696962 | m³ | Percement dans un mur | AllplanAttributes - Object Layer Attributes #1, Désignation: CVC-074
CVC-073 | SOUS-SOL | Nouvelle construction | Maçonnerie | 0050PeM1612696928 | m³ | Percement dans un mur | AllplanAttributes - Object Layer Attributes #1, Désignation: CVC-073
TE-026 | SOUS-SOL | Nouvelle construction | Maçonnerie | 0050PeM1612703294 | m³ | Percement dans un mur | AllplanAttributes - Object Layer Attributes #1, Désignation: TE-026
TE-024 | SOUS-SOL | Nouvelle construction | Maçonnerie | 0050PeM1612703230 | m³ | Percement dans un mur | AllplanAttributes - Object Layer Attributes #1, Désignation: TE-024
CVC-071 | SOUS-SOL | Nouvelle construction | Maçonnerie | 0050PeM1612696945 | m³ | Percement dans un mur | AllplanAttributes - Object Layer Attributes #1, Désignation: CVC-071
CVC-072 | SOUS-SOL | Nouvelle construction | Maçonnerie | 0050PeM1612696908 | m³ | Percement dans un mur | AllplanAttributes - Object Layer Attributes #1, Désignation: CVC-072
TE-025 | SOUS-SOL | Nouvelle construction | Maçonnerie | 0050PeM1612703269 | m³ | Percement dans un mur | AllplanAttributes - Object Layer Attributes #1, Désignation: TE-025
PB-010 | SOUS-SOL | Nouvelle construction | Maçonnerie | 0050PeM1612710553 | m³ | Percement dans un mur | AllplanAttributes - Object Layer Attributes #1, Désignation: PB-010
CVC-069 | SOUS-SOL | Nouvelle construction | Maçonnerie | 0050PeM1612696865 | m³ | Percement dans un mur | AllplanAttributes - Object Layer Attributes #1, Désignation: CVC-069
PB-015 | SOUS-SOL | Nouvelle construction | Maçonnerie | 0050PeM1612710726 | m³ | Percement dans un mur | AllplanAttributes - Object Layer Attributes #1, Désignation: PB-015
CVC-070 | SOUS-SOL | Nouvelle construction | Maçonnerie | 0050PeM1612696794 | m³ | Percement dans un mur | AllplanAttributes - Object Layer Attributes #1, Désignation: CVC-070
PB-017 | SOUS-SOL | Nouvelle construction | Maçonnerie | 0050PeM1612710770 | m³ | Percement dans un mur | AllplanAttributes - Object Layer Attributes #1, Désignation: PB-017
RCU | SOUS-SOL | Nouvelle construction | Maçonnerie | 0050PeM1612741470 | m³ | Percement dans un mur | AllplanAttributes - Object Layer Attributes #1, Désignation: RCU
CVC-061 | SOUS-SOL | Nouvelle construction | Maçonnerie | 0050PeM1612696754 | m³ | Percement dans un mur | AllplanAttributes - Object Layer Attributes #1, Désignation: CVC-061
TE-022 | SOUS-SOL | Nouvelle construction | Maçonnerie | 0050PeM1612703129 | m³ | Percement dans un mur | AllplanAttributes - Object Layer Attributes #1, Désignation: TE-022
TE-021 | SOUS-SOL | Nouvelle construction | Maçonnerie | 0050PeM1612703177 | m³ | Percement dans un mur | AllplanAttributes - Object Layer Attributes #1, Désignation: TE-021
TE-022 | SOUS-SOL | Nouvelle construction | Maçonnerie | 0050PeM1612703207 | m³ | Percement dans un mur | AllplanAttributes - Object Layer Attributes #1, Désignation: TE-022
PB-005 | SOUS-SOL | Nouvelle construction | Maçonnerie | 0050PeM1612710596 | m³ | Percement dans un mur | AllplanAttributes - Object Layer Attributes #1, Désignation: PB-005
PB-004 | SOUS-SOL | Nouvelle construction | Maçonnerie | 0050PeM1612710646 | m³ | Percement dans un mur | AllplanAttributes - Object Layer Attributes #1, Désignation: PB-004
PB-002 | SOUS-SOL | Nouvelle construction | Maçonnerie | 0050PeM1612710690 | m³ | Percement dans un mur | AllplanAttributes - Object Layer Attributes #1, Désignation: PB-002
TGBT | SOUS-SOL | Nouvelle construction | Maçonnerie | 0050PeM1613192825 | m³ | Percement dans un mur | AllplanAttributes - Object Layer Attributes #1, Désignation: TGBT
TGBT | SOUS-SOL | Nouvelle construction | Maçonnerie | 0050PeM1613192874 | m³ | Percement dans un mur | AllplanAttributes - Object Layer Attributes #1, Désignation: TGBT
Baie de porte | SOUS-SOL | Nouvelle construction | Béton et béton armé | 0050Por1612723191 | m³ | Baie de porte | AllplanAttributes - Object Layer Attributes #1, Mode_d'ouverture_porte: DIN L
CVC-060 | SOUS-SOL | Nouvelle construction | Maçonnerie | 0050PeM1612697788 | m³ | Percement dans un mur | AllplanAttributes - Object Layer Attributes #1, Désignation: CVC-060
CVC-059 | SOUS-SOL | Nouvelle construction | Maçonnerie | 0050PeM1612697833 | m³ | Percement dans un mur | AllplanAttributes - Object Layer Attributes #1, Désignation: CVC-059
PB-013 | SOUS-SOL | Nouvelle construction | Maçonnerie | 0050PeM1612718690 | m³ | Percement dans un mur | AllplanAttributes - Object Layer Attributes #1, Désignation: PB-013
PB-126 | SOUS-SOL | Nouvelle construction | Maçonnerie | 0050PeM1612718692 | m³ | Percement dans un mur | AllplanAttributes - Object Layer Attributes #1, Désignation: PB-126
PB-022 | SOUS-SOL | Nouvelle construction | Maçonnerie | 0050PeM1612718706 | m³ | Percement dans un mur | AllplanAttributes - Object Layer Attributes #1, Désignation: PB-022
PB-037 | SOUS-SOL | Nouvelle construction | Maçonnerie | 0050PeM1612709961 | m³ | Percement dans un mur | AllplanAttributes - Object Layer Attributes #1, Désignation: PB-037
CVC-057 | SOUS-SOL | Nouvelle construction | Maçonnerie | 0050PeM1612718680 | m³ | Percement dans un mur | AllplanAttributes - Object Layer Attributes #1, Désignation: CVC-057
PB-053 | SOUS-SOL | Nouvelle construction | Maçonnerie | 0050PeM1612718715 | m³ | Percement dans un mur | AllplanAttributes - Object Layer Attributes #1, Désignation: PB-053
Baie de porte | SOUS-SOL | Nouvelle construction | Béton et béton armé | 0050Por1612723211 | m³ | Baie de porte | AllplanAttributes - Object Layer Attributes #1, Mode_d'ouverture_porte: DIN L
CVC-058 | SOUS-SOL | Nouvelle construction | Maçonnerie | 0050PeM1612718673 | m³ | Percement dans un mur | AllplanAttributes - Object Layer Attributes #1, Désignation: CVC-058
Baie de porte | SOUS-SOL | Nouvelle construction | Béton et béton armé | 0050Por1612723230 | m³ | Baie de porte | AllplanAttributes - Object Layer Attributes #1, Mode_d'ouverture_porte: -
PB-078 | SOUS-SOL | Nouvelle construction | Maçonnerie | 0050PeM1612713019 | m³ | Percement dans un mur | AllplanAttributes - Object Layer Attributes #1, Désignation: PB-078
Percement dans mur | SOUS-SOL | Nouvelle construction | Maçonnerie | 0050PeM1612696506 | m³ | Percement dans un mur
TE-089 | SOUS-SOL | Nouvelle construction | Maçonnerie | 0050PeM1612703056 | m³ | Percement dans un mur | AllplanAttributes - Object Layer Attributes #1, Désignation: TE-089
Percement dans mur | SOUS-SOL | Nouvelle construction | Maçonnerie | 0050PeM1612696548 | m³ | Percement dans un mur
PB-098 | SOUS-SOL | Nouvelle construction | Maçonnerie | 0050PeM1612713103 | m³ | Percement dans un mur | AllplanAttributes - Object Layer Attributes #1, Désignation: PB-098
Percement dans mur | SOUS-SOL | Nouvelle construction | Maçonnerie | 0050PeM1612715276 | m³ | Percement dans un mur
Percement dans mur | SOUS-SOL | Nouvelle construction | Maçonnerie | 0050PeM1612704069 | m³ | Percement dans un mur
TE-098 | SOUS-SOL | Nouvelle construction | Maçonnerie | 0050PeM1612703895 | m³ | Percement dans un mur | AllplanAttributes - Object Layer Attributes #1, Désignation: TE-098
CVC-054 | SOUS-SOL | Nouvelle construction | Maçonnerie | 0050PeM1612698232 | m³ | Percement dans un mur | AllplanAttributes - Object Layer Attributes #1, Désignation: CVC-054
CVC-001 | SOUS-SOL | Nouvelle construction | Maçonnerie | 0050PeM1612700400 | m³ | Percement dans un mur | AllplanAttributes - Object Layer Attributes #1, Désignation: CVC-001
CVC-002 | SOUS-SOL | Nouvelle construction | Maçonnerie | 0050PeM1612700430 | m³ | Percement dans un mur | AllplanAttributes - Object Layer Attributes #1, Désignation: CVC-002
PB-104 | SOUS-SOL | Nouvelle construction | Maçonnerie | 0050PeM1612709411 | m³ | Percement dans un mur | AllplanAttributes - Object Layer Attributes #1, Désignation: PB-104
PB-114 | SOUS-SOL | Nouvelle construction | Maçonnerie | 0050PeM1612709451 | m³ | Percement dans un mur | AllplanAttributes - Object Layer Attributes #1, Désignation: PB-114
PB-116 | SOUS-SOL | Nouvelle construction | Maçonnerie | 0050PeM1612709505 | m³ | Percement dans un mur | AllplanAttributes - Object Layer Attributes #1, Désignation: PB-116
TE-102 | SOUS-SOL | Nouvelle construction | Maçonnerie | 0050PeM1612714929 | m³ | Percement dans un mur | AllplanAttributes - Object Layer Attributes #1, Désignation: TE-102
PB-120 | SOUS-SOL | Nouvelle construction | Maçonnerie | 0050PeM1612722838 | m³ | Percement dans un mur | AllplanAttributes - Object Layer Attributes #1, Désignation: PB-120
PB-121 | SOUS-SOL | Nouvelle construction | Maçonnerie | 0050PeM1612722836 | m³ | Percement dans un mur | AllplanAttributes - Object Layer Attributes #1, Désignation: PB-121
PB-122 | SOUS-SOL | Nouvelle construction | Maçonnerie | 0050PeM1612722834 | m³ | Percement dans un mur | AllplanAttributes - Object Layer Attributes #1, Désignation: PB-122
PB--119 | SOUS-SOL | Nouvelle construction | Maçonnerie | 0050PeM1612713593 | m³ | Percement dans un mur | AllplanAttributes - Object Layer Attributes #1, Désignation: PB--119
PB-097 | SOUS-SOL | Nouvelle construction | Maçonnerie | 0050PeM1612713138 | m³ | Percement dans un mur | AllplanAttributes - Object Layer Attributes #1, Désignation: PB-097
PB-066 | SOUS-SOL | Nouvelle construction | Maçonnerie | 0050PeM1612713173 | m³ | Percement dans un mur | AllplanAttributes - Object Layer Attributes #1, Désignation: PB-066
PB-041 | SOUS-SOL | Nouvelle construction | Maçonnerie | 0050PeM1612713237 | m³ | Percement dans un mur | AllplanAttributes - Object Layer Attributes #1, Désignation: PB-041
TE-085 | SOUS-SOL | Nouvelle construction | Maçonnerie | 0050PeM1612702737 | m³ | Percement dans un mur | AllplanAttributes - Object Layer Attributes #1, Désignation: TE-085
Baie de porte | SOUS-SOL | Nouvelle construction | Béton et béton armé | 0050Por1612723381 | m³ | Baie de porte | AllplanAttributes - Object Layer Attributes #1, Mode_d'ouverture_porte: DIN R
EL-025 | SOUS-SOL | Nouvelle construction | Maçonnerie | 0050PeM1612715368 | m³ | Percement dans un mur | AllplanAttributes - Object Layer Attributes #1, Désignation: EL-025
PB-044 | SOUS-SOL | Nouvelle construction | Maçonnerie | 0050PeM1612711430 | m³ | Percement dans un mur | AllplanAttributes - Object Layer Attributes #1, Désignation: PB-044
CVC-088 | SOUS-SOL | Nouvelle construction | Maçonnerie | 0050PeM1612698742 | m³ | Percement dans un mur | AllplanAttributes - Object Layer Attributes #1, Désignation: CVC-088
CVC-068 | SOUS-SOL | Nouvelle construction | Maçonnerie | 0050PeM1612698687 | m³ | Percement dans un mur | AllplanAttributes - Object Layer Attributes #1, Désignation: CVC-068
TE-090 | SOUS-SOL | Nouvelle construction | Maçonnerie | 0050PeM1612707557 | m³ | Percement dans un mur | AllplanAttributes - Object Layer Attributes #1, Désignation: TE-090
TE-033 | SOUS-SOL | Nouvelle construction | Maçonnerie | 0050PeM1612707662 | m³ | Percement dans un mur | AllplanAttributes - Object Layer Attributes #1, Désignation: TE-033
TE-032 | SOUS-SOL | Nouvelle construction | Maçonnerie | 0050PeM1612707600 | m³ | Percement dans un mur | AllplanAttributes - Object Layer Attributes #1, Désignation: TE-032
TE-034 | SOUS-SOL | Nouvelle construction | Maçonnerie | 0050PeM1612707726 | m³ | Percement dans un mur | AllplanAttributes - Object Layer Attributes #1, Désignation: TE-034
PB-049 | SOUS-SOL | Nouvelle construction | Maçonnerie | 0050PeM1612711559 | m³ | Percement dans un mur | AllplanAttributes - Object Layer Attributes #1, Désignation: PB-049
CVC-087 | SOUS-SOL | Nouvelle construction | Maçonnerie | 0050PeM1612699023 | m³ | Percement dans un mur | AllplanAttributes - Object Layer Attributes #1, Désignation: CVC-087
PB-051 | SOUS-SOL | Nouvelle construction | Maçonnerie | 0050PeM1612711611 | m³ | Percement dans un mur | AllplanAttributes - Object Layer Attributes #1, Désignation: PB-051
PB-061 | SOUS-SOL | Nouvelle construction | Maçonnerie | 0050PeM1612711772 | m³ | Percement dans un mur | AllplanAttributes - Object Layer Attributes #1, Désignation: PB-061
CVC-088 | SOUS-SOL | Nouvelle construction | Maçonnerie | 0050PeM1612698936 | m³ | Percement dans un mur | AllplanAttributes - Object Layer Attributes #1, Désignation: CVC-088
CVC-066 | SOUS-SOL | Nouvelle construction | Maçonnerie | 0050PeM1612698905 | m³ | Percement dans un mur | AllplanAttributes - Object Layer Attributes #1, Désignation: CVC-066
PB-054 | SOUS-SOL | Nouvelle construction | Maçonnerie | 0050PeM1612711668 | m³ | Percement dans un mur | AllplanAttributes - Object Layer Attributes #1, Désignation: PB-054
CVC-067 | SOUS-SOL | Nouvelle construction | Maçonnerie | 0050PeM1612698829 | m³ | Percement dans un mur | AllplanAttributes - Object Layer Attributes #1, Désignation: CVC-067
TE-046 | SOUS-SOL | Nouvelle construction | Maçonnerie | 0050PeM1612706623 | m³ | Percement dans un mur | AllplanAttributes - Object Layer Attributes #1, Désignation: TE-046
Percement dans mur | SOUS-SOL | Nouvelle construction | Maçonnerie | 0050PeM1612715260 | m³ | Percement dans un mur
TE-035 | SOUS-SOL | Nouvelle construction | Maçonnerie | 0050PeM1612707483 | m³ | Percement dans un mur | AllplanAttributes - Object Layer Attributes #1, Désignation: TE-035
TE-036 | SOUS-SOL | Nouvelle construction | Maçonnerie | 0050PeM1612707319 | m³ | Percement dans un mur | AllplanAttributes - Object Layer Attributes #1, Désignation: TE-036
TE-048 | SOUS-SOL | Nouvelle construction | Maçonnerie | 0050PeM1612707213 | m³ | Percement dans un mur | AllplanAttributes - Object Layer Attributes #1, Désignation: TE-048
TE-010 | SOUS-SOL | Nouvelle construction | Maçonnerie | 0050PeM1612707189 | m³ | Percement dans un mur | AllplanAttributes - Object Layer Attributes #1, Désignation: TE-010
CVC-050 | SOUS-SOL | Nouvelle construction | Maçonnerie | 0050PeM1612698610 | m³ | Percement dans un mur | AllplanAttributes - Object Layer Attributes #1, Désignation: CVC-050
TE-014 | SOUS-SOL | Nouvelle construction | Maçonnerie | 0050PeM1612706927 | m³ | Percement dans un mur | AllplanAttributes - Object Layer Attributes #1, Désignation: TE-014
TE-018 | SOUS-SOL | Nouvelle construction | Maçonnerie | 0050PeM1612706265 | m³ | Percement dans un mur | AllplanAttributes - Object Layer Attributes #1, Désignation: TE-018
TE-053 | SOUS-SOL | Nouvelle construction | Maçonnerie | 0050PeM1612706235 | m³ | Percement dans un mur | AllplanAttributes - Object Layer Attributes #1, Désignation: TE-053
TE-051 | SOUS-SOL | Nouvelle construction | Maçonnerie | 0050PeM1612706191 | m³ | Percement dans un mur | AllplanAttributes - Object Layer Attributes #1, Désignation: TE-051
TE-063 | SOUS-SOL | Nouvelle construction | Maçonnerie | 0050PeM1612705691 | m³ | Percement dans un mur | AllplanAttributes - Object Layer Attributes #1, Désignation: TE-063
TE-054 | SOUS-SOL | Nouvelle construction | Maçonnerie | 0050PeM1612705835 | m³ | Percement dans un mur | AllplanAttributes - Object Layer Attributes #1, Désignation: TE-054
CVC-053 | SOUS-SOL | Nouvelle construction | Maçonnerie | 0050PeM1612698276 | m³ | Percement dans un mur | AllplanAttributes - Object Layer Attributes #1, Désignation: CVC-053
CVC-054 | SOUS-SOL | Nouvelle construction | Maçonnerie | 0050PeM1612698141 | m³ | Percement dans un mur | AllplanAttributes - Object Layer Attributes #1, Désignation: CVC-054
TE-098 | SOUS-SOL | Nouvelle construction | Maçonnerie | 0050PeM1612703857 | m³ | Percement dans un mur | AllplanAttributes - Object Layer Attributes #1, Désignation: TE-098
TE-070 | SOUS-SOL | Nouvelle construction | Maçonnerie | 0050PeM1612703996 | m³ | Percement dans un mur | AllplanAttributes - Object Layer Attributes #1, Désignation: TE-070
TE-068 | SOUS-SOL | Nouvelle construction | Maçonnerie | 0050PeM1612704227 | m³ | Percement dans un mur | AllplanAttributes - Object Layer Attributes #1, Désignation: TE-068
TE-096 | SOUS-SOL | Nouvelle construction | Maçonnerie | 0050PeM1612704347 | m³ | Percement dans un mur | AllplanAttributes - Object Layer Attributes #1, Désignation: TE-096
TE-072 | SOUS-SOL | Nouvelle construction | Maçonnerie | 0050PeM1612704433 | m³ | Percement dans un mur | AllplanAttributes - Object Layer Attributes #1, Désignation: TE-072
TE-050 | SOUS-SOL | Nouvelle construction | Maçonnerie | 0050PeM1612704532 | m³ | Percement dans un mur | AllplanAttributes - Object Layer Attributes #1, Désignation: TE-050
TE-008 | SOUS-SOL | Nouvelle construction | Maçonnerie | 0050PeM1612704602 | m³ | Percement dans un mur | AllplanAttributes - Object Layer Attributes #1, Désignation: TE-008
TE-017 | SOUS-SOL | Nouvelle construction | Maçonnerie | 0050PeM1612704734 | m³ | Percement dans un mur | AllplanAttributes - Object Layer Attributes #1, Désignation: TE-017
TE-065 | SOUS-SOL | Nouvelle construction | Maçonnerie | 0050PeM1612704841 | m³ | Percement dans un mur | AllplanAttributes - Object Layer Attributes #1, Désignation: TE-065
TE-016 | SOUS-SOL | Nouvelle construction | Maçonnerie | 0050PeM1612704965 | m³ | Percement dans un mur | AllplanAttributes - Object Layer Attributes #1, Désignation: TE-016
TE-049 | SOUS-SOL | Nouvelle construction | Maçonnerie | 0050PeM1612704801 | m³ | Percement dans un mur | AllplanAttributes - Object Layer Attributes #1, Désignation: TE-049
TE-007 | SOUS-SOL | Nouvelle construction | Maçonnerie | 0050PeM1612705066 | m³ | Percement dans un mur | AllplanAttributes - Object Layer Attributes #1, Désignation: TE-007
CVC-052 | SOUS-SOL | Nouvelle construction | Maçonnerie | 0050PeM1612698362 | m³ | Percement dans un mur | AllplanAttributes - Object Layer Attributes #1, Désignation: CVC-052
TE-101 | SOUS-SOL | Nouvelle construction | Maçonnerie | 0050PeM1612705463 | m³ | Percement dans un mur | AllplanAttributes - Object Layer Attributes #1, Désignation: TE-101
TE-047 | SOUS-SOL | Nouvelle construction | Maçonnerie | 0050PeM1612706498 | m³ | Percement dans un mur | AllplanAttributes - Object Layer Attributes #1, Désignation: TE-047
TE-009 | SOUS-SOL | Nouvelle construction | Maçonnerie | 0050PeM1612706554 | m³ | Percement dans un mur | AllplanAttributes - Object Layer Attributes #1, Désignation: TE-009
TE-086 | SOUS-SOL | Nouvelle construction | Maçonnerie | 0050PeM1612706526 | m³ | Percement dans un mur | AllplanAttributes - Object Layer Attributes #1, Désignation: TE-086
TE-041 | SOUS-SOL | Nouvelle construction | Maçonnerie | 0050PeM1612741286 | m³ | Percement dans un mur | AllplanAttributes - Object Layer Attributes #1, Désignation: TE-041
CVC-051 | SOUS-SOL | Nouvelle construction | Maçonnerie | 0050PeM1612698461 | m³ | Percement dans un mur | AllplanAttributes - Object Layer Attributes #1, Désignation: CVC-051
TE-012 | SOUS-SOL | Nouvelle construction | Maçonnerie | 0050PeM1612741340 | m³ | Percement dans un mur | AllplanAttributes - Object Layer Attributes #1, Désignation: TE-012
TE-011 | SOUS-SOL | Nouvelle construction | Maçonnerie | 0050PeM1612741363 | m³ | Percement dans un mur | AllplanAttributes - Object Layer Attributes #1, Désignation: TE-011
TE-015 | SOUS-SOL | Nouvelle construction | Maçonnerie | 0050PeM1612706594 | m³ | Percement dans un mur | AllplanAttributes - Object Layer Attributes #1, Désignation: TE-015
CVC-010 | SOUS-SOL | Nouvelle construction | Maçonnerie | 0050PeM1612696684 | m³ | Percement dans un mur | AllplanAttributes - Object Layer Attributes #1, Désignation: CVC-010
Baie de porte | SOUS-SOL | Nouvelle construction | Béton et béton armé | 0050Por1612730842 | m³ | Baie de porte | AllplanAttributes - Object Layer Attributes #1, Mode_d'ouverture_porte: DIN R
CVC-020 | SOUS-SOL | Nouvelle construction | Maçonnerie | 0050PeM1612730844 | m³ | Percement dans un mur | AllplanAttributes - Object Layer Attributes #1, Désignation: CVC-020
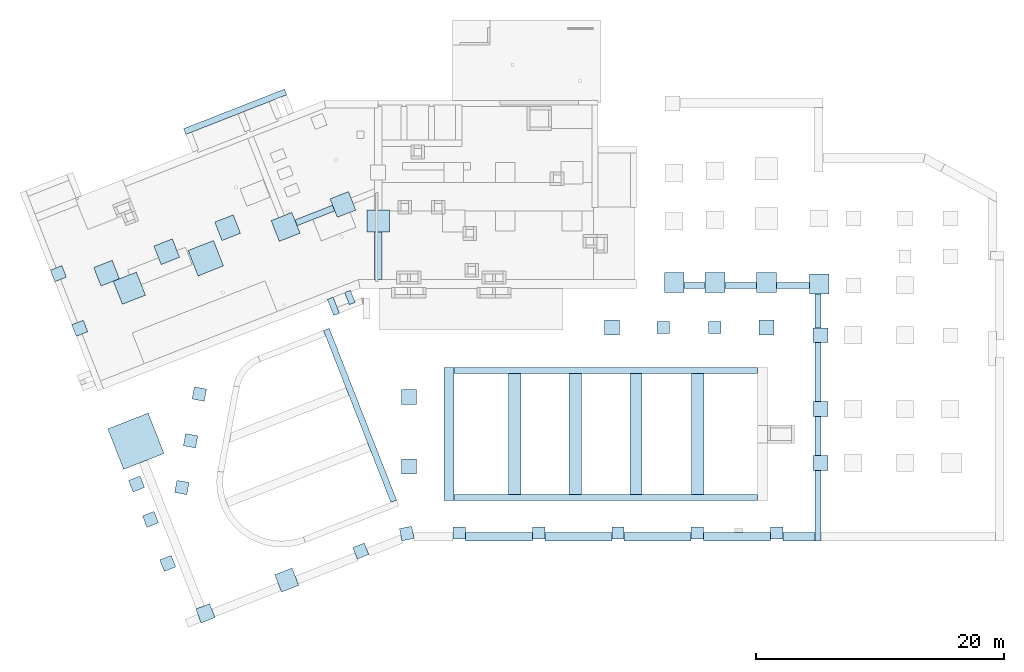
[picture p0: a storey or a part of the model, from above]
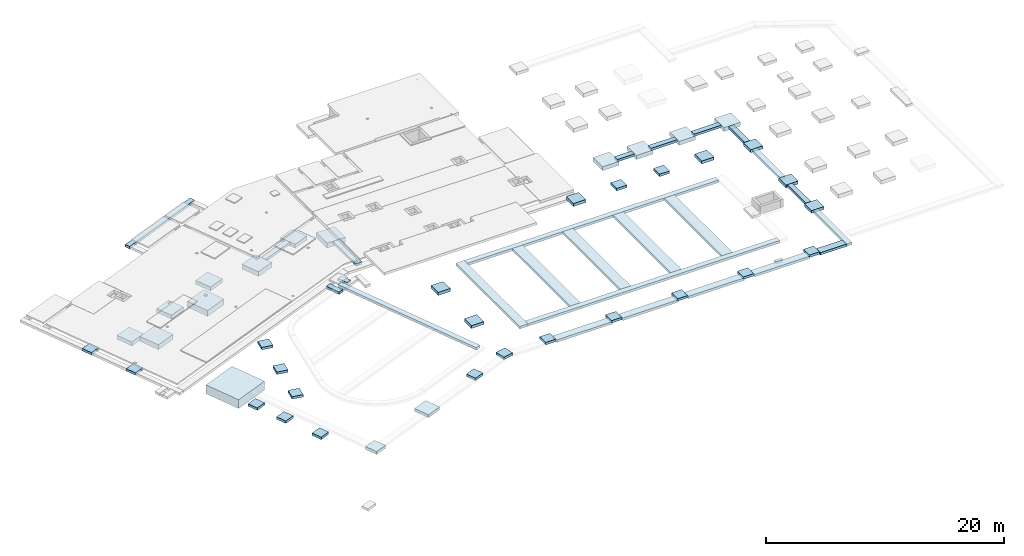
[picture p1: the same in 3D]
Properties of the parts of a building model (IFC2X3), part 2 of 4

# IfcOpeningElement: Opening (1065)
Name | In | Object Layer Attributes #1, Catégorie de transformation | Object Layer Attributes #1, Métier | Object Layer Attributes #1, Id_élt_Allmétré | Object Layer Attributes #1, Unité | Object Layer Attributes #1, Nom_de_macro
CVC-019 | SOUS-SOL | Nouvelle construction | Maçonnerie | 0050PeM1612730846 | m³ | Percement dans un mur | AllplanAttributes - Object Layer Attributes #1, Désignation: CVC-019
PB-078 | SOUS-SOL | Nouvelle construction | Maçonnerie | 0050PeM1612730848 | m³ | Percement dans un mur | AllplanAttributes - Object Layer Attributes #1, Désignation: PB-078
PB-098 | SOUS-SOL | Nouvelle construction | Maçonnerie | 0050PeM1612730850 | m³ | Percement dans un mur | AllplanAttributes - Object Layer Attributes #1, Désignation: PB-098
TE-089 | SOUS-SOL | Nouvelle construction | Maçonnerie | 0050PeM1612730852 | m³ | Percement dans un mur | AllplanAttributes - Object Layer Attributes #1, Désignation: TE-089
PB-012 | SOUS-SOL | Nouvelle construction | Maçonnerie | 0050PeM1612718190 | m³ | Percement dans un mur | AllplanAttributes - Object Layer Attributes #1, Désignation: PB-012
PB-016 | SOUS-SOL | Nouvelle construction | Maçonnerie | 0050PeM1612718188 | m³ | Percement dans un mur | AllplanAttributes - Object Layer Attributes #1, Désignation: PB-016
Baie de porte | SOUS-SOL | Nouvelle construction | Béton et béton armé | 0050Por1612723086 | m³ | Baie de porte | AllplanAttributes - Object Layer Attributes #1, Mode_d'ouverture_porte: DIN R
CVC-063 | SOUS-SOL | Nouvelle construction | Maçonnerie | 0050PeM1612718192 | m³ | Percement dans un mur | AllplanAttributes - Object Layer Attributes #1, Désignation: CVC-063
PB-026 | SOUS-SOL | Nouvelle construction | Maçonnerie | 0050PeM1612718186 | m³ | Percement dans un mur | AllplanAttributes - Object Layer Attributes #1, Désignation: PB-026
EL-007 | SOUS-SOL | Nouvelle construction | Maçonnerie | 0050PeM1612715321 | m³ | Percement dans un mur | AllplanAttributes - Object Layer Attributes #1, Désignation: EL-007
CVC-064 | SOUS-SOL | Nouvelle construction | Maçonnerie | 0050PeM1612718182 | m³ | Percement dans un mur | AllplanAttributes - Object Layer Attributes #1, Désignation: CVC-064
PB-034 | SOUS-SOL | Nouvelle construction | Maçonnerie | 0050PeM1612718180 | m³ | Percement dans un mur | AllplanAttributes - Object Layer Attributes #1, Désignation: PB-034
PB-032 | SOUS-SOL | Nouvelle construction | Maçonnerie | 0050PeM1612711331 | m³ | Percement dans un mur | AllplanAttributes - Object Layer Attributes #1, Désignation: PB-032
Percement dans mur | SOUS-SOL | Nouvelle construction | Maçonnerie | 0050PeM1613195102 | m³ | Percement dans un mur
Percement dans mur | SOUS-SOL | Nouvelle construction | Maçonnerie | 0050PeM1613195118 | m³ | Percement dans un mur
PB-060 | SOUS-SOL | Nouvelle construction | Maçonnerie | 0050PeM1612710403 | m³ | Percement dans un mur | AllplanAttributes - Object Layer Attributes #1, Désignation: PB-060
PB-080 | SOUS-SOL | Nouvelle construction | Maçonnerie | 0050PeM1612710186 | m³ | Percement dans un mur | AllplanAttributes - Object Layer Attributes #1, Désignation: PB-080
PB-085 | SOUS-SOL | Nouvelle construction | Maçonnerie | 0050PeM1612710117 | m³ | Percement dans un mur | AllplanAttributes - Object Layer Attributes #1, Désignation: PB-085
TE-080 | SOUS-SOL | Nouvelle construction | Maçonnerie | 0050PeM1612703634 | m³ | Percement dans un mur | AllplanAttributes - Object Layer Attributes #1, Désignation: TE-080
CVC-056 | SOUS-SOL | Nouvelle construction | Maçonnerie | 0050PeM1612698008 | m³ | Percement dans un mur | AllplanAttributes - Object Layer Attributes #1, Désignation: CVC-056
TE-006 | SOUS-SOL | Nouvelle construction | Maçonnerie | 0050PeM1612703684 | m³ | Percement dans un mur | AllplanAttributes - Object Layer Attributes #1, Désignation: TE-006
Incorpo TE-016 | SOUS-SOL | Nouvelle construction | Maçonnerie | 0050PeM1612703802 | m³ | Percement dans un mur | AllplanAttributes - Object Layer Attributes #1, Désignation: Incorpo TE-016
Incorpo TE-017 | SOUS-SOL | Nouvelle construction | Maçonnerie | 0050PeM1612703820 | m³ | Percement dans un mur | AllplanAttributes - Object Layer Attributes #1, Désignation: Incorpo TE-017
Incorpo TE-015 | SOUS-SOL | Nouvelle construction | Maçonnerie | 0050PeM1612703758 | m³ | Percement dans un mur | AllplanAttributes - Object Layer Attributes #1, Désignation: Incorpo TE-015
TE-004 | SOUS-SOL | Nouvelle construction | Maçonnerie | 0050PeM1612708902 | m³ | Percement dans un mur | AllplanAttributes - Object Layer Attributes #1, Désignation: TE-004
CVC-033 | SOUS-SOL | Nouvelle construction | Maçonnerie | 0050PeM1612700371 | m³ | Percement dans un mur | AllplanAttributes - Object Layer Attributes #1, Désignation: CVC-033
TE-073 | SOUS-SOL | Nouvelle construction | Maçonnerie | 0050PeM1612708859 | m³ | Percement dans un mur | AllplanAttributes - Object Layer Attributes #1, Désignation: TE-073
TE-003 | SOUS-SOL | Nouvelle construction | Maçonnerie | 0050PeM1612708768 | m³ | Percement dans un mur | AllplanAttributes - Object Layer Attributes #1, Désignation: TE-003
TE-060 | SOUS-SOL | Nouvelle construction | Maçonnerie | 0050PeM1612708398 | m³ | Percement dans un mur | AllplanAttributes - Object Layer Attributes #1, Désignation: TE-060
TE-061 | SOUS-SOL | Nouvelle construction | Maçonnerie | 0050PeM1612708313 | m³ | Percement dans un mur | AllplanAttributes - Object Layer Attributes #1, Désignation: TE-061
TE-078 | SOUS-SOL | Nouvelle construction | Maçonnerie | 0050PeM1612708191 | m³ | Percement dans un mur | AllplanAttributes - Object Layer Attributes #1, Désignation: TE-078
TE-058 | SOUS-SOL | Nouvelle construction | Maçonnerie | 0050PeM1612708220 | m³ | Percement dans un mur | AllplanAttributes - Object Layer Attributes #1, Désignation: TE-058
TE-079 | SOUS-SOL | Nouvelle construction | Maçonnerie | 0050PeM1612708094 | m³ | Percement dans un mur | AllplanAttributes - Object Layer Attributes #1, Désignation: TE-079
TE-001 | SOUS-SOL | Nouvelle construction | Maçonnerie | 0050PeM1612707884 | m³ | Percement dans un mur | AllplanAttributes - Object Layer Attributes #1, Désignation: TE-001
TE-043 | SOUS-SOL | Nouvelle construction | Maçonnerie | 0050PeM1612707844 | m³ | Percement dans un mur | AllplanAttributes - Object Layer Attributes #1, Désignation: TE-043
TE-042 | SOUS-SOL | Nouvelle construction | Maçonnerie | 0050PeM1612707799 | m³ | Percement dans un mur | AllplanAttributes - Object Layer Attributes #1, Désignation: TE-042
CVC-036 | SOUS-SOL | Nouvelle construction | Maçonnerie | 0050PeM1612700181 | m³ | Percement dans un mur | AllplanAttributes - Object Layer Attributes #1, Désignation: CVC-036
TE-077 | SOUS-SOL | Nouvelle construction | Maçonnerie | 0050PeM1612708453 | m³ | Percement dans un mur | AllplanAttributes - Object Layer Attributes #1, Désignation: TE-077
TE-057 | SOUS-SOL | Nouvelle construction | Maçonnerie | 0050PeM1612708531 | m³ | Percement dans un mur | AllplanAttributes - Object Layer Attributes #1, Désignation: TE-057
TE-064 | SOUS-SOL | Nouvelle construction | Maçonnerie | 0050PeM1612708572 | m³ | Percement dans un mur | AllplanAttributes - Object Layer Attributes #1, Désignation: TE-064
TE-076 | SOUS-SOL | Nouvelle construction | Maçonnerie | 0050PeM1612708715 | m³ | Percement dans un mur | AllplanAttributes - Object Layer Attributes #1, Désignation: TE-076
CVC-034 | SOUS-SOL | Nouvelle construction | Maçonnerie | 0050PeM1612700326 | m³ | Percement dans un mur | AllplanAttributes - Object Layer Attributes #1, Désignation: CVC-034
TE-002 | SOUS-SOL | Nouvelle construction | Maçonnerie | 0050PeM1612708169 | m³ | Percement dans un mur | AllplanAttributes - Object Layer Attributes #1, Désignation: TE-002
CVC-035 | SOUS-SOL | Nouvelle construction | Maçonnerie | 0050PeM1612700264 | m³ | Percement dans un mur | AllplanAttributes - Object Layer Attributes #1, Désignation: CVC-035
YE-044 | SOUS-SOL | Nouvelle construction | Maçonnerie | 0050PeM1612707969 | m³ | Percement dans un mur | AllplanAttributes - Object Layer Attributes #1, Désignation: YE-044
TE-067 | SOUS-SOL | Nouvelle construction | Maçonnerie | 0050PeM1612708794 | m³ | Percement dans un mur | AllplanAttributes - Object Layer Attributes #1, Désignation: TE-067
Trémie dans dalle | SOUS-SOL | Nouvelle construction |  | 0050TrD1612686878 | m³ | Trémie
Trémie dans dalle | SOUS-SOL | Nouvelle construction |  | 0050TrD1612686953 | m³ | Trémie
PB-089 | SOUS-SOL | Nouvelle construction | Maçonnerie | 0050PeM1612710083 | m³ | Percement dans un mur | AllplanAttributes - Object Layer Attributes #1, Désignation: PB-089
PB-082 | SOUS-SOL | Nouvelle construction | Maçonnerie | 0050PeM1612710045 | m³ | Percement dans un mur | AllplanAttributes - Object Layer Attributes #1, Désignation: PB-082
PB-064 | SOUS-SOL | Nouvelle construction | Maçonnerie | 0050PeM1612710002 | m³ | Percement dans un mur | AllplanAttributes - Object Layer Attributes #1, Désignation: PB-064
Percement dans mur | SOUS-SOL | Nouvelle construction | Maçonnerie | 0050PeM1612704287 | m³ | Percement dans un mur
Percement dans mur | SOUS-SOL | Nouvelle construction | Maçonnerie | 0050PeM1612698317 | m³ | Percement dans un mur
Percement dans mur | SOUS-SOL | Nouvelle construction | Maçonnerie | 0050PeM1612704357 | m³ | Percement dans un mur
Percement dans mur | SOUS-SOL | Nouvelle construction | Maçonnerie | 0050PeM1612705941 | m³ | Percement dans un mur
Percement dans mur | SOUS-SOL | Nouvelle construction | Maçonnerie | 0050PeM1612705947 | m³ | Percement dans un mur
Percement dans mur | SOUS-SOL | Nouvelle construction | Maçonnerie | 0050PeM1612706315 | m³ | Percement dans un mur
Percement dans mur | SOUS-SOL | Nouvelle construction | Maçonnerie | 0050PeM1612706323 | m³ | Percement dans un mur
Percement dans mur | SOUS-SOL | Nouvelle construction | Maçonnerie | 0050PeM1612706330 | m³ | Percement dans un mur
Percement dans mur | SOUS-SOL | Nouvelle construction | Maçonnerie | 0050PeM1612707347 | m³ | Percement dans un mur
Incorpo TE001 | SOUS-SOL | Nouvelle construction | Maçonnerie | 0050PeM1612704429 | m³ | Percement dans un mur | AllplanAttributes - Object Layer Attributes #1, Désignation: Incorpo TE001
IncorpoTE002 | SOUS-SOL | Nouvelle construction | Maçonnerie | 0050PeM1612704573 | m³ | Percement dans un mur | AllplanAttributes - Object Layer Attributes #1, Désignation: IncorpoTE002
IncorpoTE003 | SOUS-SOL | Nouvelle construction | Maçonnerie | 0050PeM1612704656 | m³ | Percement dans un mur | AllplanAttributes - Object Layer Attributes #1, Désignation: IncorpoTE003
IncorpoTE004 | SOUS-SOL | Nouvelle construction | Maçonnerie | 0050PeM1612704730 | m³ | Percement dans un mur | AllplanAttributes - Object Layer Attributes #1, Désignation: IncorpoTE004
Percement dans mur | SOUS-SOL | Nouvelle construction | Maçonnerie | 0050PeM1612704880 | m³ | Percement dans un mur
Percement dans mur | SOUS-SOL | Nouvelle construction | Maçonnerie | 0050PeM1612698423 | m³ | Percement dans un mur
IncorpoTE006 | SOUS-SOL | Nouvelle construction | Maçonnerie | 0050PeM1612705125 | m³ | Percement dans un mur | AllplanAttributes - Object Layer Attributes #1, Désignation: IncorpoTE006
IncorpoTE007 | SOUS-SOL | Nouvelle construction | Maçonnerie | 0050PeM1612705240 | m³ | Percement dans un mur | AllplanAttributes - Object Layer Attributes #1, Désignation: IncorpoTE007
IncorpoTE005 | SOUS-SOL | Nouvelle construction | Maçonnerie | 0050PeM1612705008 | m³ | Percement dans un mur | AllplanAttributes - Object Layer Attributes #1, Désignation: IncorpoTE005
IncorpoTE008 | SOUS-SOL | Nouvelle construction | Maçonnerie | 0050PeM1612705512 | m³ | Percement dans un mur | AllplanAttributes - Object Layer Attributes #1, Désignation: IncorpoTE008
Percement dans mur | SOUS-SOL | Nouvelle construction | Maçonnerie | 0050PeM1612698619 | m³ | Percement dans un mur
IncorpoTE014 | SOUS-SOL | Nouvelle construction | Maçonnerie | 0050PeM1612741034 | m³ | Percement dans un mur | AllplanAttributes - Object Layer Attributes #1, Désignation: IncorpoTE014
IncorpoTE013 | SOUS-SOL | Nouvelle construction | Maçonnerie | 0050PeM1612740984 | m³ | Percement dans un mur | AllplanAttributes - Object Layer Attributes #1, Désignation: IncorpoTE013
IncorpoTE012 | SOUS-SOL | Nouvelle construction | Maçonnerie | 0050PeM1612707069 | m³ | Percement dans un mur | AllplanAttributes - Object Layer Attributes #1, Désignation: IncorpoTE012
IncorpoTE010 | SOUS-SOL | Nouvelle construction | Maçonnerie | 0050PeM1612706700 | m³ | Percement dans un mur | AllplanAttributes - Object Layer Attributes #1, Désignation: IncorpoTE010
Percement dans mur | SOUS-SOL | Nouvelle construction | Maçonnerie | 0050PeM1612707279 | m³ | Percement dans un mur
Percement dans mur | SOUS-SOL | Nouvelle construction | Maçonnerie | 0050PeM1612706684 | m³ | Percement dans un mur
IncorpoTE009 | SOUS-SOL | Nouvelle construction | Maçonnerie | 0050PeM1612706686 | m³ | Percement dans un mur | AllplanAttributes - Object Layer Attributes #1, Désignation: IncorpoTE009
Percement dans mur | SOUS-SOL | Nouvelle construction | Maçonnerie | 0050PeM1612706445 | m³ | Percement dans un mur
Percement dans mur | SOUS-SOL | Nouvelle construction | Maçonnerie | 0050PeM1612698537 | m³ | Percement dans un mur
Percement dans mur | SOUS-SOL | Nouvelle construction | Maçonnerie | 0050PeM1612705957 | m³ | Percement dans un mur
Percement dans mur | SOUS-SOL | Nouvelle construction | Maçonnerie | 0050PeM1612706720 | m³ | Percement dans un mur
IncorpoTE011 | SOUS-SOL | Nouvelle construction | Maçonnerie | 0050PeM1612740928 | m³ | Percement dans un mur | AllplanAttributes - Object Layer Attributes #1, Désignation: IncorpoTE011
TE-035 | SOUS-SOL | Nouvelle construction | Maçonnerie | 0050PeM1612707518 | m³ | Percement dans un mur | AllplanAttributes - Object Layer Attributes #1, Désignation: TE-035
Rainure X | SOUS-SOL | Nouvelle construction |  | 0050PeM1612678404 | m³ | Percement dans un mur | AllplanAttributes - Object Layer Attributes #1, Désignation: Rainure X
Percement dans mur | SOUS-SOL | Nouvelle construction |  | 0050PeM1612678436 | m³ | Percement dans un mur
Percement dans mur | SOUS-SOL | Nouvelle construction |  | 0050PeM1612678434 | m³ | Percement dans un mur
Percement dans mur | SOUS-SOL | Nouvelle construction |  | 0050PeM1612678438 | m³ | Percement dans un mur
Percement dans mur | SOUS-SOL | Nouvelle construction |  | 0050PeM1612678440 | m³ | Percement dans un mur
Percement dans mur | SOUS-SOL | Nouvelle construction |  | 0050PeM1612678442 | m³ | Percement dans un mur
Percement dans mur | SOUS-SOL | Nouvelle construction |  | 0050PeM1612678444 | m³ | Percement dans un mur
N°8 | SOUS-SOL | Nouvelle construction |  | 0050PeM1612678415 | m³ | Percement dans un mur | AllplanAttributes - Object Layer Attributes #1, Désignation: N°8
N°11 | SOUS-SOL | Nouvelle construction |  | 0050PeM1612678406 | m³ | Percement dans un mur | AllplanAttributes - Object Layer Attributes #1, Désignation: N°11
N°6 | SOUS-SOL | Nouvelle construction |  | 0050PeM1612678413 | m³ | Percement dans un mur | AllplanAttributes - Object Layer Attributes #1, Désignation: N°6
N°4 | SOUS-SOL | Nouvelle construction |  | 0050PeM1612678411 | m³ | Percement dans un mur | AllplanAttributes - Object Layer Attributes #1, Désignation: N°4
N°8 | SOUS-SOL | Nouvelle construction |  | 0050PeM1612678408 | m³ | Percement dans un mur | AllplanAttributes - Object Layer Attributes #1, Désignation: N°8
N°9 | SOUS-SOL | Nouvelle construction |  | 0050PeM1612678418 | m³ | Percement dans un mur | AllplanAttributes - Object Layer Attributes #1, Désignation: N°9
Percement dans mur | SOUS-SOL | Nouvelle construction |  | 0050PeM1612673496 | m³ | Percement dans un mur
Percement dans mur | SOUS-SOL | Nouvelle construction |  | 0050PeM1612673372 | m³ | Percement dans un mur
Percement dans mur | SOUS-SOL | Nouvelle construction |  | 0050PeM1612673410 | m³ | Percement dans un mur
Percement dans mur | SOUS-SOL | Nouvelle construction |  | 0050PeM1612673328 | m³ | Percement dans un mur
Percement dans mur | SOUS-SOL | Nouvelle construction |  | 0050PeM1612673460 | m³ | Percement dans un mur
N°8 | SOUS-SOL | Nouvelle construction |  | 0050PeM1612673462 | m³ | Percement dans un mur | AllplanAttributes - Object Layer Attributes #1, Désignation: N°8
N°6 | SOUS-SOL | Nouvelle construction |  | 0050PeM1612673420 | m³ | Percement dans un mur | AllplanAttributes - Object Layer Attributes #1, Désignation: N°6
N°8 | SOUS-SOL | Nouvelle construction |  | 0050PeM1612673369 | m³ | Percement dans un mur | AllplanAttributes - Object Layer Attributes #1, Désignation: N°8
N°5 | SOUS-SOL | Nouvelle construction |  | 0050PeM1612673338 | m³ | Percement dans un mur | AllplanAttributes - Object Layer Attributes #1, Désignation: N°5
N°8 | SOUS-SOL | Nouvelle construction |  | 0050PeM1612673493 | m³ | Percement dans un mur | AllplanAttributes - Object Layer Attributes #1, Désignation: N°8
Rainure X | SOUS-SOL | Nouvelle construction |  | 0050PeM1612680427 | m³ | Percement dans un mur | AllplanAttributes - Object Layer Attributes #1, Désignation: Rainure X
EL-022 | SOUS-SOL | Nouvelle construction | Maçonnerie | 0050PeM1612736498 | m³ | Percement dans un mur | AllplanAttributes - Object Layer Attributes #1, Désignation: EL-022
EL-022 | SOUS-SOL | Nouvelle construction | Maçonnerie | 0050PeM1612736496 | m³ | Percement dans un mur | AllplanAttributes - Object Layer Attributes #1, Désignation: EL-022
Percement dans mur | SOUS-SOL | Nouvelle construction |  | 0050PeM1612684737 | m³ | Percement dans un mur
Percement dans mur | SOUS-SOL | Nouvelle construction |  | 0050PeM1612684793 | m³ | Percement dans un mur
Percement dans mur | SOUS-SOL | Nouvelle construction |  | 0050PeM1612681989 | m³ | Percement dans un mur
N°7 | SOUS-SOL | Nouvelle construction |  | 0050PeM1612684801 | m³ | Percement dans un mur | AllplanAttributes - Object Layer Attributes #1, Désignation: N°7
Percement dans mur | SOUS-SOL | Nouvelle construction |  | 0050PeM1612682860 | m³ | Percement dans un mur
N°7 | SOUS-SOL | Nouvelle construction |  | 0050PeM1612684490 | m³ | Percement dans un mur | AllplanAttributes - Object Layer Attributes #1, Désignation: N°7
N°7a | SOUS-SOL | Nouvelle construction |  | 0050PeM1612682158 | m³ | Percement dans un mur | AllplanAttributes - Object Layer Attributes #1, Désignation: N°7a
Percement dans mur | SOUS-SOL | Nouvelle construction | Maçonnerie | 0050PeM1612771061 | m³ | Percement dans un mur | AllplanAttributes - Object Layer Attributes #2, Catégorie de transformation: Nouvelle construction; Object Layer Attributes #2, Métier: Maçonnerie; Object Layer Attributes #2, Id_élt_Allmétré: 0050PeM1612771062; Object Layer Attributes #2, Unité: m²; Object Layer Attributes #2, Nom_de_macro: Percement dans un mur
Percement dans mur | SOUS-SOL | Nouvelle construction | Maçonnerie | 0050PeM1612771125 | m³ | Percement dans un mur
Percement dans mur | SOUS-SOL | Nouvelle construction | Maçonnerie | 0050PeM1612771199 | m³ | Percement dans un mur | AllplanAttributes - Object Layer Attributes #2, Catégorie de transformation: Nouvelle construction; Object Layer Attributes #2, Métier: Maçonnerie; Object Layer Attributes #2, Id_élt_Allmétré: 0050PeM1612771200; Object Layer Attributes #2, Unité: m²; Object Layer Attributes #2, Nom_de_macro: Percement dans un mur
Percement dans mur | SOUS-SOL | Nouvelle construction | Maçonnerie | 0050PeM1612771268 | m³ | Percement dans un mur
Percement dans mur | SOUS-SOL | Nouvelle construction | Maçonnerie | 0050PeM1612771333 | m³ | Percement dans un mur
Percement dans mur | SOUS-SOL | Nouvelle construction | Maçonnerie | 0050PeM1612771380 | m³ | Percement dans un mur | AllplanAttributes - Object Layer Attributes #2, Catégorie de transformation: Nouvelle construction; Object Layer Attributes #2, Métier: Maçonnerie; Object Layer Attributes #2, Id_élt_Allmétré: 0050PeM1612771379; Object Layer Attributes #2, Unité: m²; Object Layer Attributes #2, Nom_de_macro: Percement dans un mur
Percement dans mur | SOUS-SOL | Nouvelle construction | Maçonnerie | 0050PeM1612771378 | m³ | Percement dans un mur
Percement dans mur | SOUS-SOL | Nouvelle construction | Maçonnerie | 0050PeM1612771400 | m³ | Percement dans un mur | AllplanAttributes - Object Layer Attributes #2, Catégorie de transformation: Nouvelle construction; Object Layer Attributes #2, Métier: Maçonnerie; Object Layer Attributes #2, Id_élt_Allmétré: 0050PeM1612771401; Object Layer Attributes #2, Unité: m²; Object Layer Attributes #2, Nom_de_macro: Percement dans un mur
Percement dans mur | SOUS-SOL | Nouvelle construction | Maçonnerie | 0050PeM1612771025 | m³ | Percement dans un mur | AllplanAttributes - Object Layer Attributes #2, Catégorie de transformation: Nouvelle construction; Object Layer Attributes #2, Métier: Maçonnerie; Object Layer Attributes #2, Id_élt_Allmétré: 0050PeM1612771026; Object Layer Attributes #2, Unité: m²; Object Layer Attributes #2, Nom_de_macro: Percement dans un mur
Percement dans mur | SOUS-SOL | Nouvelle construction | Maçonnerie | 0050PeM1612771423 | m³ | Percement dans un mur | AllplanAttributes - Object Layer Attributes #2, Catégorie de transformation: Nouvelle construction; Object Layer Attributes #2, Métier: Maçonnerie; Object Layer Attributes #2, Id_élt_Allmétré: 0050PeM1612771424; Object Layer Attributes #2, Unité: m²; Object Layer Attributes #2, Nom_de_macro: Percement dans un mur
Percement dans mur | SOUS-SOL | Nouvelle construction | Maçonnerie | 0050PeM1612770994 | m³ | Percement dans un mur
Accès VS | SOUS-SOL | Nouvelle construction | Maçonnerie | 0050PeM1613173010 | m³ | Percement dans un mur | AllplanAttributes - Object Layer Attributes #1, Désignation: Accès VS
Accès VS | SOUS-SOL | Nouvelle construction | Maçonnerie | 0050PeM1613173164 | m³ | Percement dans un mur | AllplanAttributes - Object Layer Attributes #1, Désignation: Accès VS
Percement dans mur | SOUS-SOL | Nouvelle construction | Maçonnerie | 0050PeM1612771311 | m³ | Percement dans un mur | AllplanAttributes - Object Layer Attributes #2, Catégorie de transformation: Nouvelle construction; Object Layer Attributes #2, Métier: Maçonnerie; Object Layer Attributes #2, Id_élt_Allmétré: 0050PeM1612771312; Object Layer Attributes #2, Unité: m²; Object Layer Attributes #2, Nom_de_macro: Percement dans un mur
Accès VS | SOUS-SOL | Nouvelle construction | Maçonnerie | 0050PeM1613173190 | m³ | Percement dans un mur | AllplanAttributes - Object Layer Attributes #1, Désignation: Accès VS
Percement dans mur | SOUS-SOL | Nouvelle construction | Maçonnerie | 0050PeM1612771010 | m³ | Percement dans un mur
Percement dans mur | SOUS-SOL |  | Maçonnerie | 0050PeM1612772188 | m³ | Percement dans un mur | AllplanAttributes - Object Layer Attributes #2, Métier: Maçonnerie; Object Layer Attributes #2, Id_élt_Allmétré: 0050PeM1612772189; Object Layer Attributes #2, Unité: m²; Object Layer Attributes #2, Nom_de_macro: Percement dans un mur
Percement dans mur | SOUS-SOL | Nouvelle construction | Maçonnerie | 0050PeM1612772138 | m³ | Percement dans un mur
Percement dans mur | SOUS-SOL | Nouvelle construction | Maçonnerie | 0050PeM1612772123 | m³ | Percement dans un mur
Percement dans mur | SOUS-SOL | Nouvelle construction | Maçonnerie | 0050PeM1612788171 | m² | Percement dans un mur | AllplanAttributes - Object Layer Attributes #2, Catégorie de transformation: Nouvelle construction; Object Layer Attributes #2, Métier: Maçonnerie; Object Layer Attributes #2, Id_élt_Allmétré: 0050PeM1612788168; Object Layer Attributes #2, Unité: m³; Object Layer Attributes #2, Nom_de_macro: Percement dans un mur
Percement dans mur | SOUS-SOL | Nouvelle construction | Maçonnerie | 0050PeM1612788208 | m² | Percement dans un mur | AllplanAttributes - Object Layer Attributes #2, Catégorie de transformation: Nouvelle construction; Object Layer Attributes #2, Métier: Maçonnerie; Object Layer Attributes #2, Id_élt_Allmétré: 0050PeM1612788210; Object Layer Attributes #2, Unité: m²; Object Layer Attributes #2, Nom_de_macro: Percement dans un mur
Percement dans mur | SOUS-SOL | Nouvelle construction | Maçonnerie | 0050PeM1612772860 | m³ | Percement dans un mur | AllplanAttributes - Object Layer Attributes #2, Catégorie de transformation: Nouvelle construction; Object Layer Attributes #2, Métier: Maçonnerie; Object Layer Attributes #2, Id_élt_Allmétré: 0050PeM1612772861; Object Layer Attributes #2, Unité: m²; Object Layer Attributes #2, Nom_de_macro: Percement dans un mur
Percement dans mur | SOUS-SOL | Nouvelle construction | Maçonnerie | 0050PeM1612788283 | m² | Percement dans un mur | AllplanAttributes - Object Layer Attributes #1, Désignation: Percement dans mur; Object Layer Attributes #1, structure_porteur: no
Percement dans mur | SOUS-SOL |  | Maçonnerie | 0050PeM1612774059 | m² | Percement dans un mur
Percement dans mur | SOUS-SOL |  | Maçonnerie | 0050PeM1612773679 | m² | Percement dans un mur | AllplanAttributes - Object Layer Attributes #2, Métier: Maçonnerie; Object Layer Attributes #2, Id_élt_Allmétré: 0050PeM1612773680; Object Layer Attributes #2, Unité: m³; Object Layer Attributes #2, Nom_de_macro: Percement dans un mur
Percement dans mur | SOUS-SOL |  | Maçonnerie | 0050PeM1612774006 | m² | Percement dans un mur | AllplanAttributes - Object Layer Attributes #2, Métier: Maçonnerie; Object Layer Attributes #2, Id_élt_Allmétré: 0050PeM1612774007; Object Layer Attributes #2, Unité: m³; Object Layer Attributes #2, Nom_de_macro: Percement dans un mur
Percement dans mur | SOUS-SOL |  | Maçonnerie | 0050PeM1612773766 | m² | Percement dans un mur | AllplanAttributes - Object Layer Attributes #2, Métier: Maçonnerie; Object Layer Attributes #2, Id_élt_Allmétré: 0050PeM1612773767; Object Layer Attributes #2, Unité: m³; Object Layer Attributes #2, Nom_de_macro: Percement dans un mur
Percement dans mur | SOUS-SOL |  | Maçonnerie | 0050PeM1612772878 | m² | Percement dans un mur | AllplanAttributes - Object Layer Attributes #2, Métier: Maçonnerie; Object Layer Attributes #2, Id_élt_Allmétré: 0050PeM1612772879; Object Layer Attributes #2, Unité: m³; Object Layer Attributes #2, Nom_de_macro: Percement dans un mur
Percement dans mur | SOUS-SOL |  | Maçonnerie | 0050PeM1612773082 | m² | Percement dans un mur | AllplanAttributes - Object Layer Attributes #2, Métier: Maçonnerie; Object Layer Attributes #2, Id_élt_Allmétré: 0050PeM1612773083; Object Layer Attributes #2, Unité: m³; Object Layer Attributes #2, Nom_de_macro: Percement dans un mur
Percement dans mur | SOUS-SOL |  | Maçonnerie | 0050PeM1612773117 | m² | Percement dans un mur | AllplanAttributes - Object Layer Attributes #2, Métier: Maçonnerie; Object Layer Attributes #2, Id_élt_Allmétré: 0050PeM1612773118; Object Layer Attributes #2, Unité: m³; Object Layer Attributes #2, Nom_de_macro: Percement dans un mur
Percement dans mur | SOUS-SOL |  | Maçonnerie | 0050PeM1612773568 | m² | Percement dans un mur | AllplanAttributes - Object Layer Attributes #2, Métier: Maçonnerie; Object Layer Attributes #2, Id_élt_Allmétré: 0050PeM1612773569; Object Layer Attributes #2, Unité: m²; Object Layer Attributes #2, Nom_de_macro: Percement dans un mur
Percement dans mur | SOUS-SOL |  | Maçonnerie | 0050PeM1612773662 | m² | Percement dans un mur | AllplanAttributes - Object Layer Attributes #2, Métier: Maçonnerie; Object Layer Attributes #2, Id_élt_Allmétré: 0050PeM1612773663; Object Layer Attributes #2, Unité: m³; Object Layer Attributes #2, Nom_de_macro: Percement dans un mur
Percement dans mur | SOUS-SOL |  | Maçonnerie | 0050PeM1612773701 | m² | Percement dans un mur
Percement dans mur | SOUS-SOL |  | Maçonnerie | 0050PeM1612773068 | m³ | Percement dans un mur
Percement dans mur | SOUS-SOL |  | Maçonnerie | 0050PeM1612773134 | m³ | Percement dans un mur
Percement dans mur | SOUS-SOL |  | Maçonnerie | 0050PeM1612773148 | m³ | Percement dans un mur
Percement dans mur | SOUS-SOL | Nouvelle construction | Maçonnerie | 0050PeM1612774255 | m³ | Percement dans un mur | AllplanAttributes - Object Layer Attributes #2, Catégorie de transformation: Nouvelle construction; Object Layer Attributes #2, Métier: Maçonnerie; Object Layer Attributes #2, Id_élt_Allmétré: 0050PeM1612774256; Object Layer Attributes #2, Unité: m²; Object Layer Attributes #2, Nom_de_macro: Percement dans un mur
Percement dans mur | SOUS-SOL | Nouvelle construction | Maçonnerie | 0050PeM1612774237 | m³ | Percement dans un mur | AllplanAttributes - Object Layer Attributes #2, Catégorie de transformation: Nouvelle construction; Object Layer Attributes #2, Métier: Maçonnerie; Object Layer Attributes #2, Id_élt_Allmétré: 0050PeM1612774238; Object Layer Attributes #2, Unité: m²; Object Layer Attributes #2, Nom_de_macro: Percement dans un mur
Percement dans mur | SOUS-SOL | Nouvelle construction | Maçonnerie | 0050PeM1612774222 | m³ | Percement dans un mur
Percement dans mur | SOUS-SOL | Nouvelle construction | Maçonnerie | 0050PeM1612774096 | m³ | Percement dans un mur | AllplanAttributes - Object Layer Attributes #2, Catégorie de transformation: Nouvelle construction; Object Layer Attributes #2, Métier: Maçonnerie; Object Layer Attributes #2, Id_élt_Allmétré: 0050PeM1612774097; Object Layer Attributes #2, Unité: m²; Object Layer Attributes #2, Nom_de_macro: Percement dans un mur
Percement dans mur | SOUS-SOL | Nouvelle construction | Maçonnerie | 0050PeM1612774114 | m³ | Percement dans un mur
Percement dans mur | SOUS-SOL |  | Maçonnerie | 0050PeM1612774274 | m² | Percement dans un mur | AllplanAttributes - Object Layer Attributes #2, Métier: Maçonnerie; Object Layer Attributes #2, Id_élt_Allmétré: 0050PeM1612774275; Object Layer Attributes #2, Unité: m²; Object Layer Attributes #2, Nom_de_macro: Percement dans un mur
Percement dans mur | SOUS-SOL |  | Maçonnerie | 0050PeM1613174093 | m³ | Percement dans un mur
PB-111 | SOUS-SOL | Nouvelle construction | Maçonnerie | 0050PeM1612713558 | m³ | Percement dans un mur | AllplanAttributes - Object Layer Attributes #1, Désignation: PB-111
Trémie dans dalle | SOUS-SOL | Nouvelle construction |  | 0050TrD1612782720 | m³ | Trémie
Trémie dans dalle | SOUS-SOL | Nouvelle construction |  | 0050TrD1612782605 | m³ | Trémie
Trémie dans dalle | SOUS-SOL | Nouvelle construction |  | 0050TrD1612782735 | m³ | Trémie
Trémie dans dalle | SOUS-SOL | Nouvelle construction |  | 0050TrD1612711837 | m³ | Trémie
Trémie dans dalle | SOUS-SOL | Nouvelle construction |  | 0050TrD1612711830 | m³ | Trémie
Trémie dans dalle | SOUS-SOL | Nouvelle construction |  | 0050TrD1612711160 | m³ | Trémie
Trémie dans dalle | SOUS-SOL | Nouvelle construction |  | 0050TrD1612711153 | m³ | Trémie
Trémie dans dalle | SOUS-SOL | Nouvelle construction |  | 0050TrD1612711146 | m³ | Trémie
Trémie dans dalle | SOUS-SOL | Nouvelle construction |  | 0050TrD1612711139 | m³ | Trémie
Trémie dans dalle | SOUS-SOL | Nouvelle construction |  | 0050TrD1612711132 | m³ | Trémie
Trémie dans dalle | SOUS-SOL | Nouvelle construction |  | 0050TrD1612711125 | m³ | Trémie
Trémie dans dalle | SOUS-SOL | Nouvelle construction |  | 0050TrD1612712910 | m³ | Trémie
Trémie dans dalle | SOUS-SOL | Nouvelle construction |  | 0050TrD1612782984 | m³ | Trémie
Trémie dans dalle | SOUS-SOL | Nouvelle construction |  | 0050TrD1612782997 | m³ | Trémie
Trémie dans dalle | SOUS-SOL | Nouvelle construction |  | 0050TrD1612783007 | m³ | Trémie
Trémie dans dalle | SOUS-SOL | Nouvelle construction |  | 0050TrD1612783020 | m³ | Trémie
Trémie dans dalle | SOUS-SOL | Nouvelle construction |  | 0050TrD1612783032 | m³ | Trémie
Trémie dans dalle | SOUS-SOL | Nouvelle construction |  | 0050TrD1612783044 | m³ | Trémie
Trémie dans dalle | SOUS-SOL | Nouvelle construction |  | 0050TrD1612783055 | m³ | Trémie
Trémie dans dalle | SOUS-SOL | Nouvelle construction |  | 0050TrD1612783067 | m³ | Trémie
Trémie dans dalle | SOUS-SOL | Nouvelle construction |  | 0050TrD1612783079 | m³ | Trémie
Trémie dans dalle | SOUS-SOL | Nouvelle construction |  | 0050TrD1612783096 | m³ | Trémie
Trémie dans dalle | SOUS-SOL | Nouvelle construction |  | 0050TrD1612783112 | m³ | Trémie
Percement dans mur | SOUS-SOL |  | Maçonnerie | 0050PeM1612790992 | m³ | Percement dans un mur
Percement dans mur | SOUS-SOL | Nouvelle construction | Maçonnerie | 0050PeM1612789351 | m³ | Percement dans un mur
Percement dans mur | SOUS-SOL | Nouvelle construction | Maçonnerie | 0050PeM1612789336 | m³ | Percement dans un mur
Percement dans mur | SOUS-SOL | Nouvelle construction | Maçonnerie | 0050PeM1612789321 | m³ | Percement dans un mur
Percement dans mur | SOUS-SOL | Nouvelle construction | Maçonnerie | 0050PeM1612789306 | m³ | Percement dans un mur
Percement dans mur | SOUS-SOL | Nouvelle construction | Maçonnerie | 0050PeM1612789291 | m³ | Percement dans un mur
Percement dans mur | SOUS-SOL | Nouvelle construction | Maçonnerie | 0050PeM1612789276 | m³ | Percement dans un mur
Percement dans mur | SOUS-SOL | Nouvelle construction | Maçonnerie | 0050PeM1612789261 | m³ | Percement dans un mur
Percement dans mur | SOUS-SOL | Nouvelle construction | Maçonnerie | 0050PeM1612789552 | m³ | Percement dans un mur
Percement dans mur | SOUS-SOL | Nouvelle construction | Maçonnerie | 0050PeM1612789567 | m³ | Percement dans un mur | AllplanAttributes - Object Layer Attributes #2, Catégorie de transformation: Nouvelle construction; Object Layer Attributes #2, Métier: Maçonnerie; Object Layer Attributes #2, Id_élt_Allmétré: 0050PeM1612789568; Object Layer Attributes #2, Unité: m²; Object Layer Attributes #2, Nom_de_macro: Percement dans un mur
Percement dans mur | SOUS-SOL | Nouvelle construction | Maçonnerie | 0050PeM1612789648 | m³ | Percement dans un mur | AllplanAttributes - Object Layer Attributes #2, Catégorie de transformation: Nouvelle construction; Object Layer Attributes #2, Métier: Maçonnerie; Object Layer Attributes #2, Id_élt_Allmétré: 0050PeM1612789647; Object Layer Attributes #2, Unité: m²; Object Layer Attributes #2, Nom_de_macro: Percement dans un mur
Percement dans mur | SOUS-SOL | Nouvelle construction | Maçonnerie | 0050PeM1612789664 | m³ | Percement dans un mur | AllplanAttributes - Object Layer Attributes #2, Catégorie de transformation: Nouvelle construction; Object Layer Attributes #2, Métier: Maçonnerie; Object Layer Attributes #2, Id_élt_Allmétré: 0050PeM1612789665; Object Layer Attributes #2, Unité: m²; Object Layer Attributes #2, Nom_de_macro: Percement dans un mur
Percement dans mur | SOUS-SOL | Nouvelle construction | Maçonnerie | 0050PeM1612789681 | m³ | Percement dans un mur | AllplanAttributes - Object Layer Attributes #2, Catégorie de transformation: Nouvelle construction; Object Layer Attributes #2, Métier: Maçonnerie; Object Layer Attributes #2, Id_élt_Allmétré: 0050PeM1612789680; Object Layer Attributes #2, Unité: m²; Object Layer Attributes #2, Nom_de_macro: Percement dans un mur
Percement dans mur | SOUS-SOL | Nouvelle construction | Maçonnerie | 0050PeM1612789696 | m³ | Percement dans un mur | AllplanAttributes - Object Layer Attributes #2, Catégorie de transformation: Nouvelle construction; Object Layer Attributes #2, Métier: Maçonnerie; Object Layer Attributes #2, Id_élt_Allmétré: 0050PeM1612789697; Object Layer Attributes #2, Unité: m²; Object Layer Attributes #2, Nom_de_macro: Percement dans un mur
Percement dans mur | SOUS-SOL | Nouvelle construction | Maçonnerie | 0050PeM1612789713 | m³ | Percement dans un mur | AllplanAttributes - Object Layer Attributes #2, Catégorie de transformation: Nouvelle construction; Object Layer Attributes #2, Métier: Maçonnerie; Object Layer Attributes #2, Id_élt_Allmétré: 0050PeM1612789712; Object Layer Attributes #2, Unité: m²; Object Layer Attributes #2, Nom_de_macro: Percement dans un mur
Percement dans mur | SOUS-SOL | Nouvelle construction | Maçonnerie | 0050PeM1612789728 | m³ | Percement dans un mur | AllplanAttributes - Object Layer Attributes #2, Catégorie de transformation: Nouvelle construction; Object Layer Attributes #2, Métier: Maçonnerie; Object Layer Attributes #2, Id_élt_Allmétré: 0050PeM1612789729; Object Layer Attributes #2, Unité: m²; Object Layer Attributes #2, Nom_de_macro: Percement dans un mur
Percement dans mur | SOUS-SOL | Nouvelle construction | Maçonnerie | 0050PeM1612789745 | m³ | Percement dans un mur | AllplanAttributes - Object Layer Attributes #2, Catégorie de transformation: Nouvelle construction; Object Layer Attributes #2, Métier: Maçonnerie; Object Layer Attributes #2, Id_élt_Allmétré: 0050PeM1612789744; Object Layer Attributes #2, Unité: m²; Object Layer Attributes #2, Nom_de_macro: Percement dans un mur
Percement dans mur | SOUS-SOL | Nouvelle construction | Maçonnerie | 0050PeM1612789962 | m³ | Percement dans un mur
Percement dans mur | SOUS-SOL | Nouvelle construction | Maçonnerie | 0050PeM1612789947 | m³ | Percement dans un mur
Percement dans mur | SOUS-SOL | Nouvelle construction | Maçonnerie | 0050PeM1612790035 | m³ | Percement dans un mur
Percement dans mur | SOUS-SOL | Nouvelle construction | Maçonnerie | 0050PeM1612790234 | m³ | Percement dans un mur
Percement dans mur | SOUS-SOL | Nouvelle construction | Maçonnerie | 0050PeM1612790248 | m³ | Percement dans un mur
Percement dans mur | SOUS-SOL | Nouvelle construction | Maçonnerie | 0050PeM1612790263 | m³ | Percement dans un mur
Percement dans mur | SOUS-SOL | Nouvelle construction | Maçonnerie | 0050PeM1612790262 | m³ | Percement dans un mur
Percement dans mur | SOUS-SOL | Nouvelle construction | Maçonnerie | 0050PeM1612790392 | m³ | Percement dans un mur
Percement dans mur | SOUS-SOL | Nouvelle construction | Maçonnerie | 0050PeM1612790420 | m³ | Percement dans un mur
Percement dans mur | SOUS-SOL | Nouvelle construction | Maçonnerie | 0050PeM1612789528 | m³ | Percement dans un mur
Percement dans mur | SOUS-SOL | Nouvelle construction | Maçonnerie | 0050PeM1612789758 | m³ | Percement dans un mur
Percement dans mur | SOUS-SOL | Nouvelle construction | Maçonnerie | 0050PeM1612789585 | m³ | Percement dans un mur
Percement dans mur | SOUS-SOL | Nouvelle construction | Maçonnerie | 0050PeM1612789600 | m³ | Percement dans un mur | AllplanAttributes - Object Layer Attributes #2, Catégorie de transformation: Nouvelle construction; Object Layer Attributes #2, Métier: Maçonnerie; Object Layer Attributes #2, Id_élt_Allmétré: 0050PeM1612789601; Object Layer Attributes #2, Unité: m²; Object Layer Attributes #2, Nom_de_macro: Percement dans un mur
Percement dans mur | SOUS-SOL | Nouvelle construction | Maçonnerie | 0050PeM1612789928 | m³ | Percement dans un mur | AllplanAttributes - Object Layer Attributes #2, Catégorie de transformation: Nouvelle construction; Object Layer Attributes #2, Métier: Maçonnerie; Object Layer Attributes #2, Id_élt_Allmétré: 0050PeM1612789929; Object Layer Attributes #2, Unité: m²; Object Layer Attributes #2, Nom_de_macro: Percement dans un mur; Object Layer Attributes #2, Désignation: N°6
Percement dans mur | SOUS-SOL | Nouvelle construction | Maçonnerie | 0050PeM1612789997 | m³ | Percement dans un mur
Percement dans mur | SOUS-SOL | Nouvelle construction | Maçonnerie | 0050PeM1612789982 | m³ | Percement dans un mur
Percement dans mur | SOUS-SOL | Nouvelle construction | Maçonnerie | 0050PeM1612790017 | m³ | Percement dans un mur | AllplanAttributes - Object Layer Attributes #2, Catégorie de transformation: Nouvelle construction; Object Layer Attributes #2, Métier: Maçonnerie; Object Layer Attributes #2, Id_élt_Allmétré: 0050PeM1612790018; Object Layer Attributes #2, Unité: m²; Object Layer Attributes #2, Nom_de_macro: Percement dans un mur
Percement dans mur | SOUS-SOL | Nouvelle construction | Maçonnerie | 0050PeM1612790050 | m³ | Percement dans un mur
Percement dans mur | SOUS-SOL | Nouvelle construction | Maçonnerie | 0050PeM1612790065 | m³ | Percement dans un mur | AllplanAttributes - Object Layer Attributes #2, Catégorie de transformation: Nouvelle construction; Object Layer Attributes #2, Métier: Maçonnerie; Object Layer Attributes #2, Id_élt_Allmétré: 0050PeM1612790066; Object Layer Attributes #2, Unité: m²; Object Layer Attributes #2, Nom_de_macro: Percement dans un mur
Percement dans mur | SOUS-SOL | Nouvelle construction | Maçonnerie | 0050PeM1612790083 | m³ | Percement dans un mur | AllplanAttributes - Object Layer Attributes #2, Catégorie de transformation: Nouvelle construction; Object Layer Attributes #2, Métier: Maçonnerie; Object Layer Attributes #2, Id_élt_Allmétré: 0050PeM1612790084; Object Layer Attributes #2, Unité: m²; Object Layer Attributes #2, Nom_de_macro: Percement dans un mur
Percement dans mur | SOUS-SOL | Nouvelle construction | Maçonnerie | 0050PeM1612790101 | m³ | Percement dans un mur | AllplanAttributes - Object Layer Attributes #2, Catégorie de transformation: Nouvelle construction; Object Layer Attributes #2, Métier: Maçonnerie; Object Layer Attributes #2, Id_élt_Allmétré: 0050PeM1612790102; Object Layer Attributes #2, Unité: m²; Object Layer Attributes #2, Nom_de_macro: Percement dans un mur
Percement dans mur | SOUS-SOL | Nouvelle construction | Maçonnerie | 0050PeM1612790119 | m³ | Percement dans un mur | AllplanAttributes - Object Layer Attributes #2, Catégorie de transformation: Nouvelle construction; Object Layer Attributes #2, Métier: Maçonnerie; Object Layer Attributes #2, Id_élt_Allmétré: 0050PeM1612790120; Object Layer Attributes #2, Unité: m²; Object Layer Attributes #2, Nom_de_macro: Percement dans un mur
Percement dans mur | SOUS-SOL | Nouvelle construction | Maçonnerie | 0050PeM1612790137 | m³ | Percement dans un mur | AllplanAttributes - Object Layer Attributes #2, Catégorie de transformation: Nouvelle construction; Object Layer Attributes #2, Métier: Maçonnerie; Object Layer Attributes #2, Id_élt_Allmétré: 0050PeM1612790138; Object Layer Attributes #2, Unité: m²; Object Layer Attributes #2, Nom_de_macro: Percement dans un mur
Percement dans mur | SOUS-SOL | Nouvelle construction | Maçonnerie | 0050PeM1612790195 | m³ | Percement dans un mur
Percement dans mur | SOUS-SOL | Nouvelle construction | Maçonnerie | 0050PeM1612790155 | m³ | Percement dans un mur | AllplanAttributes - Object Layer Attributes #2, Catégorie de transformation: Nouvelle construction; Object Layer Attributes #2, Métier: Maçonnerie; Object Layer Attributes #2, Id_élt_Allmétré: 0050PeM1612790156; Object Layer Attributes #2, Unité: m²; Object Layer Attributes #2, Nom_de_macro: Percement dans un mur
Percement dans mur | SOUS-SOL | Nouvelle construction | Maçonnerie | 0050PeM1612790285 | m³ | Percement dans un mur
Percement dans mur | SOUS-SOL | Nouvelle construction | Maçonnerie | 0050PeM1612790284 | m³ | Percement dans un mur
Percement dans mur | SOUS-SOL | Nouvelle construction | Maçonnerie | 0050PeM1612790305 | m³ | Percement dans un mur
Percement dans mur | SOUS-SOL | Nouvelle construction | Maçonnerie | 0050PeM1612790318 | m³ | Percement dans un mur
Percement dans mur | SOUS-SOL | Nouvelle construction | Maçonnerie | 0050PeM1612790346 | m³ | Percement dans un mur
Percement dans mur | SOUS-SOL | Nouvelle construction | Maçonnerie | 0050PeM1612790361 | m³ | Percement dans un mur
Percement dans mur | SOUS-SOL | Nouvelle construction | Maçonnerie | 0050PeM1612790331 | m³ | Percement dans un mur
Percement dans mur | SOUS-SOL | Nouvelle construction | Maçonnerie | 0050PeM1612790173 | m³ | Percement dans un mur
Percement dans mur | SOUS-SOL | Nouvelle construction | Maçonnerie | 0050PeM1612789904 | m³ | Percement dans un mur
Percement dans mur | SOUS-SOL | Nouvelle construction | Maçonnerie | 0050PeM1612788730 | m² | Percement dans un mur
Percement dans mur | SOUS-SOL | Nouvelle construction | Maçonnerie | 0050PeM1612788860 | m² | Percement dans un mur
Percement dans mur | SOUS-SOL | Nouvelle construction | Maçonnerie | 0050PeM1612788899 | m² | Percement dans un mur
Percement dans mur | SOUS-SOL | Nouvelle construction | Maçonnerie | 0050PeM1612788967 | m² | Percement dans un mur
Percement dans mur | SOUS-SOL | Nouvelle construction | Maçonnerie | 0050PeM1612789001 | m² | Percement dans un mur
Trémie dans dalle | SOUS-SOL | Nouvelle construction |  | 0050TrD1613162960 | m³ | Trémie
Trémie dans dalle | SOUS-SOL | Nouvelle construction |  | 0050TrD1613162959 | m³ | Trémie
Trémie dans dalle | SOUS-SOL | Nouvelle construction |  | 0050TrD1613162958 | m³ | Trémie
Trémie dans dalle | SOUS-SOL | Nouvelle construction |  | 0050TrD1613162957 | m³ | Trémie
Trémie dans dalle | SOUS-SOL | Nouvelle construction |  | 0050TrD1613162956 | m³ | Trémie
Trémie dans dalle | SOUS-SOL | Nouvelle construction |  | 0050TrD1613162955 | m³ | Trémie
Trémie dans dalle | SOUS-SOL | Nouvelle construction |  | 0050TrD1613162954 | m³ | Trémie
Trémie dans dalle | SOUS-SOL | Nouvelle construction |  | 0050TrD1613162953 | m³ | Trémie
Trémie dans dalle | SOUS-SOL | Nouvelle construction |  | 0050TrD1613162952 | m³ | Trémie
Trémie dans dalle | SOUS-SOL | Nouvelle construction |  | 0050TrD1613162951 | m³ | Trémie
Trémie dans dalle | SOUS-SOL | Nouvelle construction |  | 0050TrD1613162950 | m³ | Trémie
Trémie dans dalle | SOUS-SOL | Nouvelle construction |  | 0050TrD1613162949 | m³ | Trémie
Trémie dans dalle | SOUS-SOL | Nouvelle construction |  | 0050TrD1613162948 | m³ | Trémie
Trémie dans dalle | SOUS-SOL | Nouvelle construction |  | 0050TrD1613162947 | m³ | Trémie
Trémie dans dalle | SOUS-SOL | Nouvelle construction |  | 0050TrD1613162908 | m³ | Trémie
Trémie dans dalle | SOUS-SOL | Nouvelle construction |  | 0050TrD1613162906 | m³ | Trémie
Trémie dans dalle | SOUS-SOL | Nouvelle construction |  | 0050TrD1613162904 | m³ | Trémie
Trémie dans dalle | SOUS-SOL | Nouvelle construction |  | 0050TrD1613162902 | m³ | Trémie
Trémie dans dalle | SOUS-SOL | Nouvelle construction |  | 0050TrD1613162900 | m³ | Trémie
Trémie dans dalle | SOUS-SOL | Nouvelle construction |  | 0050TrD1613162898 | m³ | Trémie
Percement dans mur | SOUS-SOL |  | Maçonnerie | 0050PeM1613163939 | m³ | Percement dans un mur
Percement dans mur | SOUS-SOL | Nouvelle construction | Maçonnerie | 0050PeM1613163936 | m³ | Percement dans un mur
Percement dans mur | SOUS-SOL | Nouvelle construction | Maçonnerie | 0050PeM1613163932 | m³ | Percement dans un mur
Percement dans mur | SOUS-SOL | Nouvelle construction | Maçonnerie | 0050PeM1613163928 | m³ | Percement dans un mur
Percement dans mur | SOUS-SOL | Nouvelle construction | Maçonnerie | 0050PeM1613163913 | m³ | Percement dans un mur
Percement dans mur | SOUS-SOL | Nouvelle construction | Maçonnerie | 0050PeM1613163909 | m³ | Percement dans un mur
Percement dans mur | SOUS-SOL | Nouvelle construction | Maçonnerie | 0050PeM1613163905 | m³ | Percement dans un mur
Percement dans mur | SOUS-SOL | Nouvelle construction | Maçonnerie | 0050PeM1612789839 | m³ | Percement dans un mur
Percement dans mur | SOUS-SOL | Nouvelle construction | Maçonnerie | 0050PeM1612787139 | m³ | Percement dans un mur
Percement dans mur | SOUS-SOL |  | Maçonnerie | 0050PeM1612789179 | m³ | Percement dans un mur
TE-074 | SOUS-SOL | Nouvelle construction | Maçonnerie | 0050PeM1612708915 | m³ | Percement dans un mur | AllplanAttributes - Object Layer Attributes #1, Désignation: TE-074
TE-075 | SOUS-SOL | Nouvelle construction | Maçonnerie | 0050PeM1612708980 | m³ | Percement dans un mur | AllplanAttributes - Object Layer Attributes #1, Désignation: TE-075
Trémie dans dalle | SOUS-SOL | Nouvelle construction |  | 0050TrD1612740833 | m³ | Trémie
Trémie dans dalle | SOUS-SOL | Nouvelle construction |  | 0050TrD1612700172 | m³ | Trémie
Trémie dans dalle | SOUS-SOL | Nouvelle construction |  | 0050TrD1612700165 | m³ | Trémie
Trémie dans dalle | SOUS-SOL | Nouvelle construction |  | 0050TrD1612700148 | m³ | Trémie
Trémie dans dalle | SOUS-SOL | Nouvelle construction |  | 0050TrD1612700140 | m³ | Trémie
Trémie dans dalle | SOUS-SOL | Nouvelle construction |  | 0050TrD1612700088 | m³ | Trémie
Trémie dans dalle | SOUS-SOL | Nouvelle construction |  | 0050TrD1612781641 | m³ | Trémie
Trémie dans dalle | SOUS-SOL | Nouvelle construction |  | 0050TrD1612780106 | m³ | Trémie
Trémie dans dalle | SOUS-SOL | Nouvelle construction |  | 0050TrD1612780102 | m³ | Trémie
Trémie dans dalle | SOUS-SOL | Nouvelle construction |  | 0050TrD1612780100 | m³ | Trémie
Trémie dans dalle | SOUS-SOL | Nouvelle construction |  | 0050TrD1612780098 | m³ | Trémie
Trémie dans dalle | SOUS-SOL | Nouvelle construction |  | 0050TrD1612780096 | m³ | Trémie
Trémie dans dalle | SOUS-SOL | Nouvelle construction |  | 0050TrD1612780094 | m³ | Trémie
Trémie dans dalle | SOUS-SOL | Nouvelle construction |  | 0050TrD1612780092 | m³ | Trémie
Trémie dans dalle | SOUS-SOL | Nouvelle construction |  | 0050TrD1612780090 | m³ | Trémie
Trémie dans dalle | SOUS-SOL | Nouvelle construction |  | 0050TrD1612780088 | m³ | Trémie
Trémie dans dalle | SOUS-SOL | Nouvelle construction |  | 0050TrD1612780104 | m³ | Trémie
PB-055 | SOUS-SOL | Nouvelle construction | Maçonnerie | 0050PeM1612713477 | m³ | Percement dans un mur | AllplanAttributes - Object Layer Attributes #1, Désignation: PB-055
CVC-024 | SOUS-SOL | Nouvelle construction | Maçonnerie | 0050PeM1612695459 | m³ | Percement dans un mur | AllplanAttributes - Object Layer Attributes #1, Désignation: CVC-024
CVC-025 | SOUS-SOL | Nouvelle construction | Maçonnerie | 0050PeM1612687292 | m³ | Percement dans un mur | AllplanAttributes - Object Layer Attributes #1, Désignation: CVC-025
CVC-023 | SOUS-SOL | Nouvelle construction | Maçonnerie | 0050PeM1612687332 | m³ | Percement dans un mur | AllplanAttributes - Object Layer Attributes #1, Désignation: CVC-023
CVC-022 | SOUS-SOL | Nouvelle construction | Maçonnerie | 0050PeM1612687378 | m³ | Percement dans un mur | AllplanAttributes - Object Layer Attributes #1, Désignation: CVC-022
Trémie dans dalle | SOUS-SOL | Nouvelle construction |  | 0050TrD1613162886 | m³ | Trémie
Trémie dans dalle | SOUS-SOL | Nouvelle construction |  | 0050TrD1613163235 | m³ | Trémie
Trémie dans dalle | SOUS-SOL | Nouvelle construction |  | 0050TrD1613162884 | m³ | Trémie
Trémie dans dalle | SOUS-SOL | Nouvelle construction |  | 0050TrD1613162888 | m³ | Trémie
Trémie dans dalle | SOUS-SOL | Nouvelle construction |  | 0050TrD1613162890 | m³ | Trémie
Trémie dans dalle | SOUS-SOL | Nouvelle construction |  | 0050TrD1613162893 | m³ | Trémie
Trémie dans dalle | SOUS-SOL | Nouvelle construction |  | 0050TrD1613162896 | m³ | Trémie
Trémie dans dalle | SOUS-SOL | Nouvelle construction |  | 0050TrD1613162910 | m³ | Trémie
Trémie dans dalle | SOUS-SOL | Nouvelle construction |  | 0050TrD1613162912 | m³ | Trémie
Trémie dans dalle | SOUS-SOL | Nouvelle construction |  | 0050TrD1613162914 | m³ | Trémie
Trémie dans dalle | SOUS-SOL | Nouvelle construction |  | 0050TrD1613162916 | m³ | Trémie
Trémie dans dalle | SOUS-SOL | Nouvelle construction |  | 0050TrD1613162918 | m³ | Trémie
Trémie dans dalle | SOUS-SOL | Nouvelle construction |  | 0050TrD1613162920 | m³ | Trémie
Trémie dans dalle | SOUS-SOL | Nouvelle construction |  | 0050TrD1613162922 | m³ | Trémie
Trémie dans dalle | SOUS-SOL | Nouvelle construction |  | 0050TrD1613162924 | m³ | Trémie
Trémie dans dalle | SOUS-SOL | Nouvelle construction |  | 0050TrD1613162926 | m³ | Trémie
Trémie dans dalle | SOUS-SOL | Nouvelle construction |  | 0050TrD1613162928 | m³ | Trémie
Trémie dans dalle | SOUS-SOL | Nouvelle construction |  | 0050TrD1613162930 | m³ | Trémie
Trémie dans dalle | SOUS-SOL | Nouvelle construction |  | 0050TrD1613162932 | m³ | Trémie
Trémie dans dalle | SOUS-SOL | Nouvelle construction |  | 0050TrD1613162935 | m³ | Trémie
Trémie dans dalle | SOUS-SOL | Nouvelle construction |  | 0050TrD1613162938 | m³ | Trémie
Trémie dans dalle | SOUS-SOL | Nouvelle construction |  | 0050TrD1613162939 | m³ | Trémie
Trémie dans dalle | SOUS-SOL | Nouvelle construction |  | 0050TrD1613162940 | m³ | Trémie
Trémie dans dalle | SOUS-SOL | Nouvelle construction |  | 0050TrD1613162941 | m³ | Trémie
Trémie dans dalle | SOUS-SOL | Nouvelle construction |  | 0050TrD1613162942 | m³ | Trémie
Trémie dans dalle | SOUS-SOL | Nouvelle construction |  | 0050TrD1613162943 | m³ | Trémie
Trémie dans dalle | SOUS-SOL | Nouvelle construction |  | 0050TrD1613162944 | m³ | Trémie
Trémie dans dalle | SOUS-SOL | Nouvelle construction |  | 0050TrD1613162945 | m³ | Trémie
Trémie dans dalle | SOUS-SOL | Nouvelle construction |  | 0050TrD1613162946 | m³ | Trémie
PB-118 | SOUS-SOL | Nouvelle construction | Maçonnerie | 0050PeM1612709582 | m³ | Percement dans un mur | AllplanAttributes - Object Layer Attributes #1, Désignation: PB-118
PB-115 | SOUS-SOL | Nouvelle construction | Maçonnerie | 0050PeM1612709550 | m³ | Percement dans un mur | AllplanAttributes - Object Layer Attributes #1, Désignation: PB-115
Trémie dans dalle | SOUS-SOL | Nouvelle construction |  | 0050TrD1613163220 | m³ | Trémie
Trémie dans dalle | SOUS-SOL | Nouvelle construction |  | 0050TrD1612716943 | m³ | Trémie
Trémie dans dalle | SOUS-SOL | Nouvelle construction |  | 0050TrD1612716944 | m³ | Trémie
Trémie dans dalle | SOUS-SOL | Nouvelle construction |  | 0050TrD1612716939 | m³ | Trémie
Trémie dans dalle | SOUS-SOL | Nouvelle construction |  | 0050TrD1612716940 | m³ | Trémie
Trémie dans dalle | SOUS-SOL | Nouvelle construction |  | 0050TrD1612716941 | m³ | Trémie
Trémie dans dalle | SOUS-SOL | Nouvelle construction |  | 0050TrD1612716937 | m³ | Trémie
Trémie dans dalle | SOUS-SOL | Nouvelle construction |  | 0050TrD1612716945 | m³ | Trémie
Trémie dans dalle | SOUS-SOL | Nouvelle construction |  | 0050TrD1612716936 | m³ | Trémie
Trémie dans dalle | SOUS-SOL | Nouvelle construction |  | 0050TrD1612716938 | m³ | Trémie
Trémie dans dalle | SOUS-SOL | Nouvelle construction |  | 0050TrD1612716942 | m³ | Trémie
Trémie dans dalle | SOUS-SOL | Nouvelle construction |  | 0050TrD1612716935 | m³ | Trémie
Trémie dans dalle | SOUS-SOL | Nouvelle construction |  | 0050TrD1612776760 | m³ | Trémie
Trémie dans dalle | SOUS-SOL | Nouvelle construction |  | 0050TrD1612776718 | m³ | Trémie
Trémie dans dalle | SOUS-SOL | Nouvelle construction |  | 0050TrD1612776725 | m³ | Trémie
Trémie dans dalle | SOUS-SOL | Nouvelle construction |  | 0050TrD1612776732 | m³ | Trémie
Trémie dans dalle | SOUS-SOL | Nouvelle construction |  | 0050TrD1612776739 | m³ | Trémie
Trémie dans dalle | SOUS-SOL | Nouvelle construction |  | 0050TrD1612776746 | m³ | Trémie
Trémie dans dalle | SOUS-SOL | Nouvelle construction |  | 0050TrD1612776753 | m³ | Trémie
Trémie dans dalle | SOUS-SOL | Nouvelle construction |  | 0050TrD1612777907 | m³ | Trémie
Trémie dans dalle | SOUS-SOL | Nouvelle construction |  | 0050TrD1612776594 | m³ | Trémie
Trémie dans dalle | SOUS-SOL | Nouvelle construction |  | 0050TrD1612776656 | m³ | Trémie
Trémie dans dalle | SOUS-SOL | Nouvelle construction |  | 0050TrD1612776663 | m³ | Trémie
Trémie dans dalle | SOUS-SOL | Nouvelle construction |  | 0050TrD1612776670 | m³ | Trémie
Trémie dans dalle | SOUS-SOL | Nouvelle construction |  | 0050TrD1612776677 | m³ | Trémie
Trémie dans dalle | SOUS-SOL | Nouvelle construction |  | 0050TrD1612776698 | m³ | Trémie
Trémie dans dalle | SOUS-SOL | Nouvelle construction |  | 0050TrD1612776705 | m³ | Trémie
Percement dans mur | SOUS-SOL |  | Maçonnerie | 0050PeM1612771779 | m³ | Percement dans un mur
Percement dans mur | SOUS-SOL | Nouvelle construction | Maçonnerie | 0050PeM1612771844 | m³ | Percement dans un mur
Percement dans mur | SOUS-SOL | Nouvelle construction | Maçonnerie | 0050PeM1612771859 | m³ | Percement dans un mur
Percement dans mur | SOUS-SOL | Nouvelle construction | Maçonnerie | 0050PeM1612788099 | m² | Percement dans un mur | AllplanAttributes - Object Layer Attributes #2, Catégorie de transformation: Nouvelle construction; Object Layer Attributes #2, Métier: Maçonnerie; Object Layer Attributes #2, Id_élt_Allmétré: 0050PeM1612788091; Object Layer Attributes #2, Unité: m²; Object Layer Attributes #2, Nom_de_macro: Percement dans un mur
Percement dans mur | SOUS-SOL | Nouvelle construction | Maçonnerie | 0050PeM1612787953 | m² | Percement dans un mur | AllplanAttributes - Object Layer Attributes #2, Catégorie de transformation: Nouvelle construction; Object Layer Attributes #2, Métier: Maçonnerie; Object Layer Attributes #2, Id_élt_Allmétré: 0050PeM1612787952; Object Layer Attributes #2, Unité: m²; Object Layer Attributes #2, Nom_de_macro: Percement dans un mur
Percement dans mur | SOUS-SOL | Nouvelle construction | Maçonnerie | 0050PeM1613203541 | m³ | Percement dans un mur
Percement dans mur | SOUS-SOL | Nouvelle construction | Maçonnerie | 0050PeM1613203609 | m³ | Percement dans un mur
Percement dans mur | SOUS-SOL | Nouvelle construction | Maçonnerie | 0050PeM1613203640 | m³ | Percement dans un mur
PB-96 | SOUS-SOL | Nouvelle construction | Maçonnerie | 0050PeM1613203979 | m³ | Percement dans un mur | AllplanAttributes - Object Layer Attributes #1, Désignation: PB-96
Accès VS | SOUS-SOL | Nouvelle construction | Maçonnerie | 0050PeM1613203990 | m³ | Percement dans un mur | AllplanAttributes - Object Layer Attributes #1, Désignation: Accès VS
PB-96 | SOUS-SOL | Nouvelle construction | Maçonnerie | 0050PeM1612709681 | m³ | Percement dans un mur | AllplanAttributes - Object Layer Attributes #1, Désignation: PB-96
Accès VS | SOUS-SOL | Nouvelle construction | Maçonnerie | 0050PeM1612755784 | m³ | Percement dans un mur | AllplanAttributes - Object Layer Attributes #1, Désignation: Accès VS
PB-123 | SOUS-SOL | Nouvelle construction | Maçonnerie | 0050PeM1612709624 | m³ | Percement dans un mur | AllplanAttributes - Object Layer Attributes #1, Désignation: PB-123
Trémie dans dalle | SOUS-SOL | Nouvelle construction |  | 0050TrD1612782767 | m³ | Trémie
Trémie dans dalle | SOUS-SOL | Nouvelle construction |  | 0050TrD1612782751 | m³ | Trémie
Trémie dans dalle | SOUS-SOL | Nouvelle construction |  | 0050TrD1612782710 | m³ | Trémie
Trémie dans dalle | SOUS-SOL | Nouvelle construction |  | 0050TrD1612782698 | m³ | Trémie
Trémie dans dalle | SOUS-SOL | Nouvelle construction |  | 0050TrD1612782686 | m³ | Trémie
Trémie dans dalle | SOUS-SOL | Nouvelle construction |  | 0050TrD1612782674 | m³ | Trémie
Trémie dans dalle | SOUS-SOL | Nouvelle construction |  | 0050TrD1612782661 | m³ | Trémie
Trémie dans dalle | SOUS-SOL | Nouvelle construction |  | 0050TrD1612782649 | m³ | Trémie
Trémie dans dalle | SOUS-SOL | Nouvelle construction |  | 0050TrD1612782637 | m³ | Trémie
Trémie dans dalle | SOUS-SOL | Nouvelle construction |  | 0050TrD1612782625 | m³ | Trémie
Trémie dans dalle | SOUS-SOL | Nouvelle construction |  | 0050TrD1612782293 | m³ | Trémie
Trémie dans dalle | SOUS-SOL | Nouvelle construction |  | 0050TrD1612782283 | m³ | Trémie
Trémie dans dalle | SOUS-SOL | Nouvelle construction |  | 0050TrD1612782273 | m³ | Trémie
Trémie dans dalle | SOUS-SOL | Nouvelle construction |  | 0050TrD1612782263 | m³ | Trémie
Trémie dans dalle | SOUS-SOL | Nouvelle construction |  | 0050TrD1612782253 | m³ | Trémie
Trémie dans dalle | SOUS-SOL | Nouvelle construction |  | 0050TrD1612782243 | m³ | Trémie
Trémie dans dalle | SOUS-SOL | Nouvelle construction |  | 0050TrD1612782233 | m³ | Trémie
Trémie dans dalle | SOUS-SOL | Nouvelle construction |  | 0050TrD1612782223 | m³ | Trémie
Trémie dans dalle | SOUS-SOL | Nouvelle construction |  | 0050TrD1612782213 | m³ | Trémie
Trémie dans dalle | SOUS-SOL | Nouvelle construction |  | 0050TrD1612782202 | m³ | Trémie
Trémie dans dalle | SOUS-SOL | Nouvelle construction |  | 0050TrD1612782186 | m³ | Trémie
Trémie dans dalle | SOUS-SOL | Nouvelle construction |  | 0050TrD1612782171 | m³ | Trémie
Trémie dans dalle | SOUS-SOL | Nouvelle construction |  | 0050TrD1612739596 | m³ | Trémie
Trémie dans dalle | SOUS-SOL | Nouvelle construction |  | 0050TrD1612739598 | m³ | Trémie
Trémie dans dalle | SOUS-SOL | Nouvelle construction |  | 0050TrD1612739593 | m³ | Trémie
Trémie dans dalle | SOUS-SOL | Nouvelle construction |  | 0050TrD1612739592 | m³ | Trémie
Trémie dans dalle | SOUS-SOL | Nouvelle construction |  | 0050TrD1612739594 | m³ | Trémie
Trémie dans dalle | SOUS-SOL | Nouvelle construction |  | 0050TrD1612739595 | m³ | Trémie
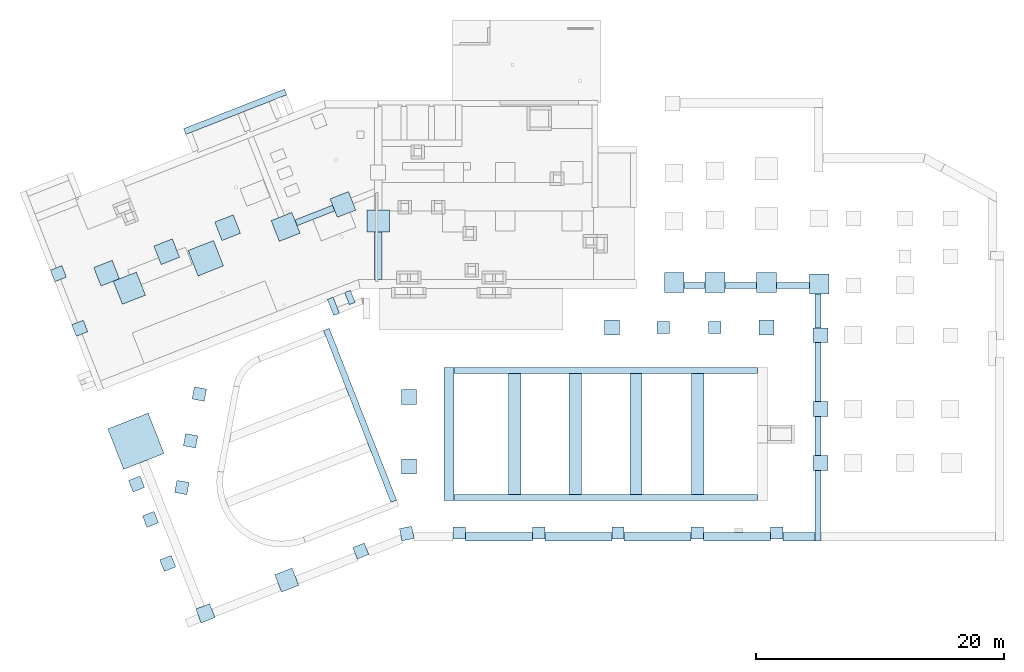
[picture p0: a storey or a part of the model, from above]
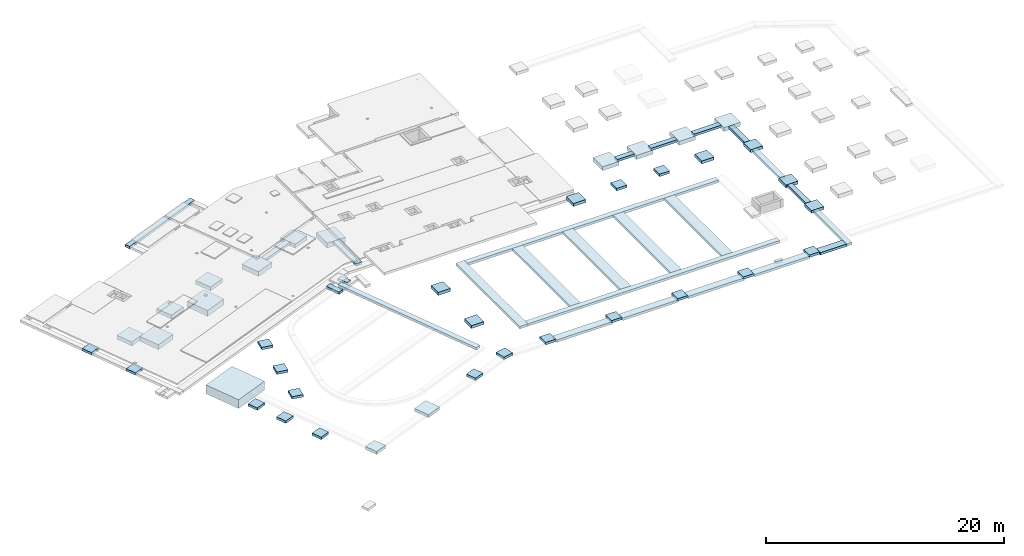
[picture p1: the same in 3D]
Properties of the parts of a building model (IFC2X3), part 3 of 4

# IfcOpeningElement: Opening (1065)
Name | In | Object Layer Attributes #1, Catégorie de transformation | Object Layer Attributes #1, Métier | Object Layer Attributes #1, Id_élt_Allmétré | Object Layer Attributes #1, Unité | Object Layer Attributes #1, Nom_de_macro
Trémie dans dalle | SOUS-SOL | Nouvelle construction |  | 0050TrD1612739597 | m³ | Trémie
Trémie dans dalle | SOUS-SOL | Nouvelle construction |  | 0050TrD1612739599 | m³ | Trémie
Trémie dans dalle | SOUS-SOL | Nouvelle construction |  | 0050TrD1612783311 | m³ | Trémie
Trémie dans dalle | SOUS-SOL | Nouvelle construction |  | 0050TrD1612783299 | m³ | Trémie
Trémie dans dalle | SOUS-SOL | Nouvelle construction |  | 0050TrD1612783286 | m³ | Trémie
Trémie dans dalle | SOUS-SOL | Nouvelle construction |  | 0050TrD1612783275 | m³ | Trémie
Trémie dans dalle | SOUS-SOL | Nouvelle construction |  | 0050TrD1612783262 | m³ | Trémie
Trémie dans dalle | SOUS-SOL | Nouvelle construction |  | 0050TrD1612783251 | m³ | Trémie
Trémie dans dalle | SOUS-SOL | Nouvelle construction |  | 0050TrD1612783239 | m³ | Trémie
Trémie dans dalle | SOUS-SOL | Nouvelle construction |  | 0050TrD1612783227 | m³ | Trémie
Trémie dans dalle | SOUS-SOL | Nouvelle construction |  | 0050TrD1612783215 | m³ | Trémie
Trémie dans dalle | SOUS-SOL | Nouvelle construction |  | 0050TrD1612783203 | m³ | Trémie
Trémie dans dalle | SOUS-SOL | Nouvelle construction |  | 0050TrD1612783191 | m³ | Trémie
Trémie dans dalle | SOUS-SOL | Nouvelle construction |  | 0050TrD1612783178 | m³ | Trémie
Trémie dans dalle | SOUS-SOL | Nouvelle construction |  | 0050TrD1612783167 | m³ | Trémie
Trémie dans dalle | SOUS-SOL | Nouvelle construction |  | 0050TrD1612783154 | m³ | Trémie
Trémie dans dalle | SOUS-SOL | Nouvelle construction |  | 0050TrD1612783121 | m³ | Trémie
Trémie dans dalle | SOUS-SOL | Nouvelle construction |  | 0050TrD1612782974 | m³ | Trémie
Trémie dans dalle | SOUS-SOL | Nouvelle construction |  | 0050TrD1612782963 | m³ | Trémie
Trémie dans dalle | SOUS-SOL | Nouvelle construction |  | 0050TrD1612782940 | m³ | Trémie
Trémie dans dalle | SOUS-SOL | Nouvelle construction |  | 0050TrD1612782932 | m³ | Trémie
Trémie dans dalle | SOUS-SOL | Nouvelle construction |  | 0050TrD1612782922 | m³ | Trémie
Trémie dans dalle | SOUS-SOL | Nouvelle construction |  | 0050TrD1612782911 | m³ | Trémie
Trémie dans dalle | SOUS-SOL | Nouvelle construction |  | 0050TrD1612782895 | m³ | Trémie
Trémie dans dalle | SOUS-SOL | Nouvelle construction |  | 0050TrD1612731216 | m³ | Trémie
Trémie dans dalle | SOUS-SOL | Nouvelle construction |  | 0050TrD1612731228 | m³ | Trémie
Trémie dans dalle | SOUS-SOL | Nouvelle construction |  | 0050TrD1612695564 | m³ | Trémie
Trémie dans dalle | SOUS-SOL | Nouvelle construction |  | 0050TrD1612695571 | m³ | Trémie
Trémie dans dalle | SOUS-SOL | Nouvelle construction |  | 0050TrD1612695606 | m³ | Trémie
Trémie dans dalle | SOUS-SOL | Nouvelle construction |  | 0050TrD1612783321 | m³ | Trémie
Trémie dans dalle | SOUS-SOL | Nouvelle construction |  | 0050TrD1612783337 | m³ | Trémie
Trémie dans dalle | SOUS-SOL | Nouvelle construction |  | 0050TrD1612783348 | m³ | Trémie
Trémie dans dalle | SOUS-SOL | Nouvelle construction |  | 0050TrD1612783370 | m³ | Trémie
Trémie dans dalle | SOUS-SOL | Nouvelle construction |  | 0050TrD1612783394 | m³ | Trémie
Trémie dans dalle | SOUS-SOL | Nouvelle construction |  | 0050TrD1612783405 | m³ | Trémie
Trémie dans dalle | SOUS-SOL | Nouvelle construction |  | 0050TrD1612695577 | m³ | Trémie
Trémie dans dalle | SOUS-SOL | Nouvelle construction |  | 0050TrD1612783383 | m³ | Trémie
Trémie dans dalle | SOUS-SOL | Nouvelle construction |  | 0050TrD1612695598 | m³ | Trémie
Trémie dans dalle | SOUS-SOL | Nouvelle construction |  | 0050TrD1612695591 | m³ | Trémie
Trémie dans dalle | SOUS-SOL | Nouvelle construction |  | 0050TrD1612695584 | m³ | Trémie
Trémie dans dalle | SOUS-SOL | Nouvelle construction |  | 0050TrD1612703090 | m³ | Trémie
Trémie dans dalle | SOUS-SOL | Nouvelle construction |  | 0050TrD1612711844 | m³ | Trémie
Trémie dans dalle | SOUS-SOL | Nouvelle construction |  | 0050TrD1612711851 | m³ | Trémie
Trémie dans dalle | SOUS-SOL | Nouvelle construction |  | 0050TrD1612711858 | m³ | Trémie
Trémie dans dalle | SOUS-SOL | Nouvelle construction |  | 0050TrD1612712670 | m³ | Trémie
Trémie dans dalle | SOUS-SOL | Nouvelle construction |  | 0050TrD1612712656 | m³ | Trémie
Trémie dans dalle | SOUS-SOL | Nouvelle construction |  | 0050TrD1612695556 | m³ | Trémie
Trémie dans dalle | SOUS-SOL | Nouvelle construction |  | 0050TrD1612695549 | m³ | Trémie
Trémie dans dalle | SOUS-SOL | Nouvelle construction |  | 0050TrD1612695542 | m³ | Trémie
Trémie dans dalle | SOUS-SOL | Nouvelle construction |  | 0050TrD1612695536 | m³ | Trémie
Trémie dans dalle | SOUS-SOL | Nouvelle construction |  | 0050TrD1612695528 | m³ | Trémie
Trémie dans dalle | SOUS-SOL | Nouvelle construction |  | 0050TrD1612783358 | m³ | Trémie
Trémie dans dalle | SOUS-SOL | Nouvelle construction |  | 0050TrD1612699106 | m³ | Trémie
Trémie dans dalle | SOUS-SOL | Nouvelle construction |  | 0050TrD1612711821 | m³ | Trémie
Trémie dans dalle | SOUS-SOL | Nouvelle construction |  | 0050TrD1612711865 | m³ | Trémie
Trémie dans dalle | SOUS-SOL | Nouvelle construction |  | 0050TrD1612712616 | m³ | Trémie
Trémie dans dalle | SOUS-SOL | Nouvelle construction |  | 0050TrD1612712609 | m³ | Trémie
Trémie dans dalle | SOUS-SOL | Nouvelle construction |  | 0050TrD1612712623 | m³ | Trémie
Trémie dans dalle | SOUS-SOL | Nouvelle construction |  | 0050TrD1612703076 | m³ | Trémie
Trémie dans dalle | SOUS-SOL | Nouvelle construction |  | 0050TrD1612712663 | m³ | Trémie
Trémie dans dalle | SOUS-SOL | Nouvelle construction |  | 0050TrD1612712642 | m³ | Trémie
Trémie dans dalle | SOUS-SOL | Nouvelle construction |  | 0050TrD1612712649 | m³ | Trémie
Trémie dans dalle | SOUS-SOL | Nouvelle construction |  | 0050TrD1612696537 | m³ | Trémie
Trémie dans dalle | SOUS-SOL | Nouvelle construction |  | 0050TrD1612699089 | m³ | Trémie
Trémie dans dalle | SOUS-SOL | Nouvelle construction |  | 0050TrD1612703083 | m³ | Trémie
Trémie dans dalle | SOUS-SOL | Nouvelle construction |  | 0050TrD1612711519 | m³ | Trémie
Trémie dans dalle | SOUS-SOL | Nouvelle construction |  | 0050TrD1612711526 | m³ | Trémie
Trémie dans dalle | SOUS-SOL | Nouvelle construction |  | 0050TrD1612711533 | m³ | Trémie
Trémie dans dalle | SOUS-SOL | Nouvelle construction |  | 0050TrD1612711813 | m³ | Trémie
Trémie dans dalle | SOUS-SOL | Nouvelle construction |  | 0050TrD1612711872 | m³ | Trémie
Trémie dans dalle | SOUS-SOL | Nouvelle construction |  | 0050TrD1612711879 | m³ | Trémie
Trémie dans dalle | SOUS-SOL | Nouvelle construction |  | 0050TrD1612711886 | m³ | Trémie
Trémie dans dalle | SOUS-SOL | Nouvelle construction |  | 0050TrD1612712630 | m³ | Trémie
Trémie dans dalle | SOUS-SOL | Nouvelle construction |  | 0050TrD1612782875 | m³ | Trémie
Trémie dans dalle | SOUS-SOL | Nouvelle construction |  | 0050TrD1612782863 | m³ | Trémie
Trémie dans dalle | SOUS-SOL | Nouvelle construction |  | 0050TrD1612782851 | m³ | Trémie
Trémie dans dalle | SOUS-SOL | Nouvelle construction |  | 0050TrD1612782839 | m³ | Trémie
Trémie dans dalle | SOUS-SOL | Nouvelle construction |  | 0050TrD1612782827 | m³ | Trémie
Trémie dans dalle | SOUS-SOL | Nouvelle construction |  | 0050TrD1612782594 | m³ | Trémie
Trémie dans dalle | SOUS-SOL | Nouvelle construction |  | 0050TrD1612782582 | m³ | Trémie
Trémie dans dalle | SOUS-SOL | Nouvelle construction |  | 0050TrD1612782570 | m³ | Trémie
Trémie dans dalle | SOUS-SOL | Nouvelle construction |  | 0050TrD1612782558 | m³ | Trémie
Trémie dans dalle | SOUS-SOL | Nouvelle construction |  | 0050TrD1612782546 | m³ | Trémie
Trémie dans dalle | SOUS-SOL | Nouvelle construction |  | 0050TrD1612782534 | m³ | Trémie
Trémie dans dalle | SOUS-SOL | Nouvelle construction |  | 0050TrD1612782522 | m³ | Trémie
Trémie dans dalle | SOUS-SOL | Nouvelle construction |  | 0050TrD1612782509 | m³ | Trémie
Trémie dans dalle | SOUS-SOL | Nouvelle construction |  | 0050TrD1612782498 | m³ | Trémie
Trémie dans dalle | SOUS-SOL | Nouvelle construction |  | 0050TrD1612782486 | m³ | Trémie
Trémie dans dalle | SOUS-SOL | Nouvelle construction |  | 0050TrD1612782474 | m³ | Trémie
Trémie dans dalle | SOUS-SOL | Nouvelle construction |  | 0050TrD1612782462 | m³ | Trémie
Trémie dans dalle | SOUS-SOL | Nouvelle construction |  | 0050TrD1612782450 | m³ | Trémie
Trémie dans dalle | SOUS-SOL | Nouvelle construction |  | 0050TrD1612782438 | m³ | Trémie
Trémie dans dalle | SOUS-SOL | Nouvelle construction |  | 0050TrD1612782390 | m³ | Trémie
Trémie dans dalle | SOUS-SOL | Nouvelle construction |  | 0050TrD1612782400 | m³ | Trémie
Trémie dans dalle | SOUS-SOL | Nouvelle construction |  | 0050TrD1612782380 | m³ | Trémie
Trémie dans dalle | SOUS-SOL | Nouvelle construction |  | 0050TrD1612782385 | m³ | Trémie
Trémie dans dalle | SOUS-SOL | Nouvelle construction |  | 0050TrD1612782395 | m³ | Trémie
Trémie dans dalle | SOUS-SOL | Nouvelle construction |  | 0050TrD1612782363 | m³ | Trémie
Trémie dans dalle | SOUS-SOL | Nouvelle construction |  | 0050TrD1612782351 | m³ | Trémie
Trémie dans dalle | SOUS-SOL | Nouvelle construction |  | 0050TrD1612782339 | m³ | Trémie
Trémie dans dalle | SOUS-SOL | Nouvelle construction |  | 0050TrD1612782327 | m³ | Trémie
Trémie dans dalle | SOUS-SOL | Nouvelle construction |  | 0050TrD1612782316 | m³ | Trémie
Trémie dans dalle | SOUS-SOL | Nouvelle construction |  | 0050TrD1612782303 | m³ | Trémie
Trémie dans dalle | SOUS-SOL | Nouvelle construction |  | 0050TrD1612736451 | m³ | Trémie
Trémie dans dalle | SOUS-SOL | Nouvelle construction |  | 0050TrD1612736452 | m³ | Trémie
Trémie dans dalle | SOUS-SOL | Nouvelle construction |  | 0050TrD1612736453 | m³ | Trémie
Trémie dans dalle | SOUS-SOL | Nouvelle construction |  | 0050TrD1612736454 | m³ | Trémie
Trémie dans dalle | SOUS-SOL | Nouvelle construction |  | 0050TrD1612736455 | m³ | Trémie
Trémie dans dalle | SOUS-SOL | Nouvelle construction |  | 0050TrD1612782007 | m³ | Trémie
Trémie dans dalle | SOUS-SOL | Nouvelle construction |  | 0050TrD1612781995 | m³ | Trémie
Trémie dans dalle | SOUS-SOL | Nouvelle construction |  | 0050TrD1612781984 | m³ | Trémie
Trémie dans dalle | SOUS-SOL | Nouvelle construction |  | 0050TrD1612781970 | m³ | Trémie
Trémie dans dalle | SOUS-SOL | Nouvelle construction |  | 0050TrD1612781943 | m³ | Trémie
Trémie dans dalle | SOUS-SOL | Nouvelle construction |  | 0050TrD1612781930 | m³ | Trémie
Trémie dans dalle | SOUS-SOL | Nouvelle construction |  | 0050TrD1612702716 | m³ | Trémie
Trémie dans dalle | SOUS-SOL | Nouvelle construction |  | 0050TrD1612702699 | m³ | Trémie
Trémie dans dalle | SOUS-SOL | Nouvelle construction |  | 0050TrD1612709339 | m³ | Trémie
Trémie dans dalle | SOUS-SOL | Nouvelle construction |  | 0050TrD1612709394 | m³ | Trémie
Trémie dans dalle | SOUS-SOL | Nouvelle construction |  | 0050TrD1612709387 | m³ | Trémie
Trémie dans dalle | SOUS-SOL | Nouvelle construction |  | 0050TrD1612709355 | m³ | Trémie
Trémie dans dalle | SOUS-SOL | Nouvelle construction |  | 0050TrD1612709348 | m³ | Trémie
Trémie dans dalle | SOUS-SOL | Nouvelle construction |  | 0050TrD1612709380 | m³ | Trémie
Trémie dans dalle | SOUS-SOL | Nouvelle construction |  | 0050TrD1613195636 | m³ | Trémie
Trémie dans dalle | SOUS-SOL | Nouvelle construction |  | 0050TrD1613195634 | m³ | Trémie
Trémie dans dalle | SOUS-SOL | Nouvelle construction |  | 0050TrD1613195632 | m³ | Trémie
Trémie dans dalle | SOUS-SOL | Nouvelle construction |  | 0050TrD1613195630 | m³ | Trémie
Trémie dans dalle | SOUS-SOL | Nouvelle construction |  | 0050TrD1613195628 | m³ | Trémie
Trémie dans dalle | SOUS-SOL | Nouvelle construction |  | 0050TrD1613195626 | m³ | Trémie
Trémie dans dalle | SOUS-SOL | Nouvelle construction |  | 0050TrD1613195624 | m³ | Trémie
Trémie dans dalle | SOUS-SOL | Nouvelle construction |  | 0050TrD1613195622 | m³ | Trémie
Trémie dans dalle | SOUS-SOL | Nouvelle construction |  | 0050TrD1613195620 | m³ | Trémie
Trémie dans dalle | SOUS-SOL | Nouvelle construction |  | 0050TrD1613195617 | m³ | Trémie
Trémie dans dalle | SOUS-SOL | Nouvelle construction |  | 0050TrD1612782062 | m³ | Trémie
Trémie dans dalle | SOUS-SOL | Nouvelle construction |  | 0050TrD1612709043 | m³ | Trémie
Trémie dans dalle | SOUS-SOL | Nouvelle construction |  | 0050TrD1612742766 | m³ | Trémie
Trémie dans dalle | SOUS-SOL | Nouvelle construction |  | 0050TrD1612709265 | m³ | Trémie
Trémie dans dalle | SOUS-SOL | Nouvelle construction |  | 0050TrD1612709364 | m³ | Trémie
Trémie dans dalle | SOUS-SOL | Nouvelle construction |  | 0050TrD1612709371 | m³ | Trémie
Trémie dans dalle | SOUS-SOL | Nouvelle construction |  | 0050TrD1612709272 | m³ | Trémie
Trémie dans dalle | SOUS-SOL | Nouvelle construction |  | 0050TrD1612709279 | m³ | Trémie
Trémie dans dalle | SOUS-SOL | Nouvelle construction |  | 0050TrD1612782017 | m³ | Trémie
Trémie dans dalle | SOUS-SOL | Nouvelle construction |  | 0050TrD1612782033 | m³ | Trémie
Trémie dans dalle | SOUS-SOL | Nouvelle construction |  | 0050TrD1612782044 | m³ | Trémie
Trémie dans dalle | SOUS-SOL | Nouvelle construction |  | 0050TrD1612782054 | m³ | Trémie
Trémie dans dalle | SOUS-SOL | Nouvelle construction |  | 0050TrD1612743190 | m³ | Trémie
Trémie dans dalle | SOUS-SOL | Nouvelle construction |  | 0050TrD1612714978 | m³ | Trémie
Trémie dans dalle | SOUS-SOL | Nouvelle construction |  | 0050TrD1612782072 | m³ | Trémie
Trémie dans dalle | SOUS-SOL | Nouvelle construction |  | 0050TrD1612709015 | m³ | Trémie
Trémie dans dalle | SOUS-SOL | Nouvelle construction |  | 0050TrD1612782096 | m³ | Trémie
Trémie dans dalle | SOUS-SOL | Nouvelle construction |  | 0050TrD1612743975 | m³ | Trémie
Trémie dans dalle | SOUS-SOL | Nouvelle construction |  | 0050TrD1612709036 | m³ | Trémie
Trémie dans dalle | SOUS-SOL | Nouvelle construction |  | 0050TrD1612744046 | m³ | Trémie
Trémie dans dalle | SOUS-SOL | Nouvelle construction |  | 0050TrD1612743998 | m³ | Trémie
Trémie dans dalle | SOUS-SOL | Nouvelle construction |  | 0050TrD1612780980 | m³ | Trémie
Trémie dans dalle | SOUS-SOL | Nouvelle construction |  | 0050TrD1612780982 | m³ | Trémie
Trémie dans dalle | SOUS-SOL | Nouvelle construction |  | 0050TrD1612780984 | m³ | Trémie
Trémie dans dalle | SOUS-SOL | Nouvelle construction |  | 0050TrD1612780986 | m³ | Trémie
Trémie dans dalle | SOUS-SOL | Nouvelle construction |  | 0050TrD1612780988 | m³ | Trémie
Trémie dans dalle | SOUS-SOL | Nouvelle construction |  | 0050TrD1612780990 | m³ | Trémie
Trémie dans dalle | SOUS-SOL | Nouvelle construction |  | 0050TrD1612780992 | m³ | Trémie
Trémie dans dalle | SOUS-SOL | Nouvelle construction |  | 0050TrD1612780994 | m³ | Trémie
Trémie dans dalle | SOUS-SOL | Nouvelle construction |  | 0050TrD1612781003 | m³ | Trémie
Trémie dans dalle | SOUS-SOL | Nouvelle construction |  | 0050TrD1612781002 | m³ | Trémie
Trémie dans dalle | SOUS-SOL | Nouvelle construction |  | 0050TrD1612781000 | m³ | Trémie
Trémie dans dalle | SOUS-SOL | Nouvelle construction |  | 0050TrD1612780998 | m³ | Trémie
Trémie dans dalle | SOUS-SOL | Nouvelle construction |  | 0050TrD1612780996 | m³ | Trémie
Trémie dans dalle | SOUS-SOL | Nouvelle construction |  | 0050TrD1612781005 | m³ | Trémie
Trémie dans dalle | SOUS-SOL | Nouvelle construction |  | 0050TrD1612776531 | m³ | Trémie
Trémie dans dalle | SOUS-SOL | Nouvelle construction |  | 0050TrD1612776412 | m³ | Trémie
Trémie dans dalle | SOUS-SOL | Nouvelle construction |  | 0050TrD1612776414 | m³ | Trémie
Trémie dans dalle | SOUS-SOL | Nouvelle construction |  | 0050TrD1612776416 | m³ | Trémie
Trémie dans dalle | SOUS-SOL | Nouvelle construction |  | 0050TrD1612776418 | m³ | Trémie
Trémie dans dalle | SOUS-SOL | Nouvelle construction |  | 0050TrD1612776420 | m³ | Trémie
Trémie dans dalle | SOUS-SOL | Nouvelle construction |  | 0050TrD1612776422 | m³ | Trémie
Trémie dans dalle | SOUS-SOL | Nouvelle construction |  | 0050TrD1612776434 | m³ | Trémie
Trémie dans dalle | SOUS-SOL | Nouvelle construction |  | 0050TrD1612776438 | m³ | Trémie
Trémie dans dalle | SOUS-SOL | Nouvelle construction |  | 0050TrD1612776440 | m³ | Trémie
Trémie dans dalle | SOUS-SOL | Nouvelle construction |  | 0050TrD1612776442 | m³ | Trémie
Trémie dans dalle | SOUS-SOL | Nouvelle construction |  | 0050TrD1612776444 | m³ | Trémie
Trémie dans dalle | SOUS-SOL | Nouvelle construction |  | 0050TrD1612776446 | m³ | Trémie
Trémie dans dalle | SOUS-SOL | Nouvelle construction |  | 0050TrD1612776426 | m³ | Trémie
Trémie dans dalle | SOUS-SOL | Nouvelle construction |  | 0050TrD1612776410 | m³ | Trémie
Trémie dans dalle | SOUS-SOL | Nouvelle construction |  | 0050TrD1612776408 | m³ | Trémie
Trémie dans dalle | SOUS-SOL | Nouvelle construction |  | 0050TrD1612776406 | m³ | Trémie
Trémie dans dalle | SOUS-SOL | Nouvelle construction |  | 0050TrD1612776404 | m³ | Trémie
Trémie dans dalle | SOUS-SOL | Nouvelle construction |  | 0050TrD1612776533 | m³ | Trémie
Trémie dans dalle | SOUS-SOL | Nouvelle construction |  | 0050TrD1612776428 | m³ | Trémie
Trémie dans dalle | SOUS-SOL | Nouvelle construction |  | 0050TrD1612781280 | m³ | Trémie
Trémie dans dalle | SOUS-SOL | Nouvelle construction |  | 0050TrD1612781369 | m³ | Trémie
Trémie dans dalle | SOUS-SOL | Nouvelle construction |  | 0050TrD1612781380 | m³ | Trémie
Trémie dans dalle | SOUS-SOL | Nouvelle construction |  | 0050TrD1612781393 | m³ | Trémie
Trémie dans dalle | SOUS-SOL | Nouvelle construction |  | 0050TrD1612781405 | m³ | Trémie
Trémie dans dalle | SOUS-SOL | Nouvelle construction |  | 0050TrD1612781417 | m³ | Trémie
Trémie dans dalle | SOUS-SOL | Nouvelle construction |  | 0050TrD1612781440 | m³ | Trémie
Trémie dans dalle | SOUS-SOL | Nouvelle construction |  | 0050TrD1612781450 | m³ | Trémie
Trémie dans dalle | SOUS-SOL | Nouvelle construction |  | 0050TrD1612781460 | m³ | Trémie
Trémie dans dalle | SOUS-SOL | Nouvelle construction |  | 0050TrD1612781470 | m³ | Trémie
Trémie dans dalle | SOUS-SOL | Nouvelle construction |  | 0050TrD1612781480 | m³ | Trémie
Trémie dans dalle | SOUS-SOL | Nouvelle construction |  | 0050TrD1612781490 | m³ | Trémie
Trémie dans dalle | SOUS-SOL | Nouvelle construction |  | 0050TrD1612781521 | m³ | Trémie
Trémie dans dalle | SOUS-SOL | Nouvelle construction |  | 0050TrD1612782146 | m³ | Trémie
Trémie dans dalle | SOUS-SOL | Nouvelle construction |  | 0050TrD1612782162 | m³ | Trémie
Trémie dans dalle | SOUS-SOL | Nouvelle construction |  | 0050TrD1612781356 | m³ | Trémie
Trémie dans dalle | SOUS-SOL | Nouvelle construction |  | 0050TrD1612781271 | m³ | Trémie
Trémie dans dalle | SOUS-SOL | Nouvelle construction |  | 0050TrD1612776585 | m³ | Trémie
Trémie dans dalle | SOUS-SOL | Nouvelle construction |  | 0050TrD1612776576 | m³ | Trémie
Trémie dans dalle | SOUS-SOL | Nouvelle construction |  | 0050TrD1612776436 | m³ | Trémie
Trémie dans dalle | SOUS-SOL | Nouvelle construction |  | 0050TrD1613171263 | m³ | Trémie
Trémie dans dalle | SOUS-SOL | Nouvelle construction |  | 0050TrD1613171273 | m³ | Trémie
Trémie dans dalle | SOUS-SOL | Nouvelle construction |  | 0050TrD1612776430 | m³ | Trémie
Trémie dans dalle | SOUS-SOL | Nouvelle construction |  | 0050TrD1612776432 | m³ | Trémie
Trémie dans dalle | SOUS-SOL | Nouvelle construction |  | 0050TrD1612776448 | m³ | Trémie
Trémie dans dalle | SOUS-SOL | Nouvelle construction |  | 0050TrD1612781290 | m³ | Trémie
Trémie dans dalle | RDC | Nouvelle construction |  | 0100TrD0000039356 | m³ | Trémie
Percement dans mur | RDC | Nouvelle construction | Maçonnerie | 0100PeM0000026264 | m³ | Percement dans un mur
Baie de porte | RDC | Nouvelle construction | Béton et béton armé | 0100Por0000028287 | m³ | Baie de porte | AllplanAttributes - Object Layer Attributes #1, Mode_d'ouverture_porte: -
Baie de fenêtre | RDC | Nouvelle construction | Fenêtrage | 0100Fen0000028139 | m³ | Baie de fenêtre
Baie de fenêtre | RDC | Nouvelle construction | Fenêtrage | 0100Fen0000028156 | m³ | Baie de fenêtre
Baie de fenêtre | RDC | Nouvelle construction | Fenêtrage | 0100Fen0000028166 | m³ | Baie de fenêtre
Baie de fenêtre | RDC | Nouvelle construction | Fenêtrage | 0100Fen0000028176 | m³ | Baie de fenêtre
Baie de fenêtre | RDC | Nouvelle construction | Fenêtrage | 0100Fen0000028186 | m³ | Baie de fenêtre
Baie de fenêtre | RDC | Nouvelle construction | Fenêtrage | 0100Fen0000028194 | m³ | Baie de fenêtre
Baie de fenêtre | RDC | Nouvelle construction | Fenêtrage | 0100Fen0000028209 | m³ | Baie de fenêtre
Baie de fenêtre | RDC | Nouvelle construction | Fenêtrage | 0100Fen0000028219 | m³ | Baie de fenêtre
Baie de fenêtre | RDC | Nouvelle construction | Fenêtrage | 0100Fen0000028237 | m³ | Baie de fenêtre
Baie de fenêtre | RDC | Nouvelle construction | Fenêtrage | 0100Fen0000028247 | m³ | Baie de fenêtre
Baie de fenêtre | RDC | Nouvelle construction | Fenêtrage | 0100Fen0000028257 | m³ | Baie de fenêtre
Baie de fenêtre | RDC | Nouvelle construction | Fenêtrage | 0100Fen0000028267 | m³ | Baie de fenêtre
PB-RDC-1 | RDC | Nouvelle construction | Maçonnerie | 0100PeM0000030817 | m³ | Percement dans un mur | AllplanAttributes - Object Layer Attributes #1, Désignation: PB-RDC-1
Baie de porte | RDC | Nouvelle construction | Béton et béton armé | 0100Por0000027680 | m³ | Baie de porte | AllplanAttributes - Object Layer Attributes #1, Mode_d'ouverture_porte: DIN R
CVC-076 | RDC | Nouvelle construction | Maçonnerie | 0100NiM0000035881 | m³ | Niche | AllplanAttributes - Object Layer Attributes #1, Désignation: CVC-076
CVC-072 | RDC | Nouvelle construction | Maçonnerie | 0100NiM0000035896 | m³ | Niche | AllplanAttributes - Object Layer Attributes #1, Désignation: CVC-072
Percement dans mur | RDC | Nouvelle construction | Maçonnerie | 0100PeM0000026307 | m³ | Percement dans un mur
PB-RDC-22 | RDC | Nouvelle construction | Maçonnerie | 0100PeM0000029161 | m³ | Percement dans un mur | AllplanAttributes - Object Layer Attributes #1, Désignation: PB-RDC-22
CVC-075 | RDC | Nouvelle construction | Maçonnerie | 0100NiM0000035911 | m³ | Niche | AllplanAttributes - Object Layer Attributes #1, Désignation: CVC-075
CVC-071 | RDC | Nouvelle construction | Maçonnerie | 0100NiM0000035924 | m³ | Niche | AllplanAttributes - Object Layer Attributes #1, Désignation: CVC-071
Percement dans mur | RDC | Nouvelle construction | Maçonnerie | 0100PeM0000026221 | m³ | Percement dans un mur
Percement dans mur | RDC | Nouvelle construction | Maçonnerie | 0100PeM0000026234 | m³ | Percement dans un mur
Baie de porte | RDC | Nouvelle construction | Béton et béton armé | 0100Por0000027706 | m³ | Baie de porte | AllplanAttributes - Object Layer Attributes #1, Mode_d'ouverture_porte: -
Baie de porte | RDC | Nouvelle construction | Béton et béton armé | 0100Por0000028314 | m³ | Baie de porte | AllplanAttributes - Object Layer Attributes #1, Mode_d'ouverture_porte: DIN R
CVC-002 | RDC | Nouvelle construction | Maçonnerie | 0100NiM0000043464 | m³ | Niche | AllplanAttributes - Object Layer Attributes #1, Désignation: CVC-002
CVC-001 | RDC | Nouvelle construction | Maçonnerie | 0100NiM0000043362 | m³ | Niche | AllplanAttributes - Object Layer Attributes #1, Désignation: CVC-001
PB-RDC-2 | RDC | Nouvelle construction | Maçonnerie | 0100PeM0000029683 | m³ | Percement dans un mur | AllplanAttributes - Object Layer Attributes #1, Désignation: PB-RDC-2
PB-RDC-6 | RDC | Nouvelle construction | Maçonnerie | 0100PeM0000029791 | m³ | Percement dans un mur | AllplanAttributes - Object Layer Attributes #1, Désignation: PB-RDC-6
Baie de fenêtre | RDC | Nouvelle construction | Fenêtrage | 0100Fen0000028307 | m³ | Baie de fenêtre
CVC-030 | RDC | Nouvelle construction | Maçonnerie | 0100NiM0000038612 | m³ | Niche | AllplanAttributes - Object Layer Attributes #1, Désignation: CVC-030
PB-RDC-10 | RDC | Nouvelle construction | Maçonnerie | 0100PeM0000030029 | m³ | Percement dans un mur | AllplanAttributes - Object Layer Attributes #1, Désignation: PB-RDC-10
PB-RDC-7-8 | RDC | Nouvelle construction | Maçonnerie | 0100PeM0000030709 | m³ | Percement dans un mur | AllplanAttributes - Object Layer Attributes #1, Désignation: PB-RDC-7-8
PB-RDC-9-42 | RDC | Nouvelle construction | Maçonnerie | 0100PeM0000030787 | m³ | Percement dans un mur | AllplanAttributes - Object Layer Attributes #1, Désignation: PB-RDC-9-42
Baie de porte | RDC | Nouvelle construction | Béton et béton armé | 0100Por0000028720 | m³ | Baie de porte | AllplanAttributes - Object Layer Attributes #1, Mode_d'ouverture_porte: -
Percement dans mur | RDC | Nouvelle construction | Maçonnerie | 0100PeM0000030832 | m³ | Percement dans un mur
Niche dans mur | RDC | Nouvelle construction | Maçonnerie | 0100NiM0000038546 | m³ | Niche
Niche dans mur | RDC | Nouvelle construction | Maçonnerie | 0100NiM0000038590 | m³ | Niche
Niche dans mur | RDC | Nouvelle construction | Maçonnerie | 0100NiM0000039108 | m³ | Niche
Niche dans mur | RDC | Nouvelle construction | Maçonnerie | 0100NiM0000039035 | m³ | Niche
EL-015-17 | RDC | Nouvelle construction | Maçonnerie | 0100NiM0000039130 | m³ | Niche | AllplanAttributes - Object Layer Attributes #1, Désignation: EL-015-17
EL-010-12 | RDC | Nouvelle construction | Maçonnerie | 0100NiM0000039069 | m³ | Niche | AllplanAttributes - Object Layer Attributes #1, Désignation: EL-010-12
Percement dans mur | RDC | Nouvelle construction | Maçonnerie | 0100PeM0000030772 | m³ | Percement dans un mur
PB-RDC-9-42 | RDC | Nouvelle construction | Maçonnerie | 0100PeM0000030802 | m³ | Percement dans un mur | AllplanAttributes - Object Layer Attributes #1, Désignation: PB-RDC-9-42
Baie de porte | RDC | Nouvelle construction | Béton et béton armé | 0100Por0000031138 | m³ | Baie de porte | AllplanAttributes - Object Layer Attributes #1, Mode_d'ouverture_porte: -
PB-RDC-18-19 | RDC | Nouvelle construction | Maçonnerie | 0100PeM0000031146 | m³ | Percement dans un mur | AllplanAttributes - Object Layer Attributes #1, Désignation: PB-RDC-18-19
CVC-051 | RDC | Nouvelle construction | Maçonnerie | 0100NiM0000038524 | m³ | Niche | AllplanAttributes - Object Layer Attributes #1, Désignation: CVC-051
CVC-050 | RDC | Nouvelle construction | Maçonnerie | 0100NiM0000038568 | m³ | Niche | AllplanAttributes - Object Layer Attributes #1, Désignation: CVC-050
EL-019 | RDC | Nouvelle construction | Maçonnerie | 0100NiM0000039213 | m³ | Niche | AllplanAttributes - Object Layer Attributes #1, Désignation: EL-019
EL-008 | RDC | Nouvelle construction | Maçonnerie | 0100NiM0000039235 | m³ | Niche
EL-013 | RDC | Nouvelle construction | Maçonnerie | 0100NiM0000039257 | m³ | Niche | AllplanAttributes - Object Layer Attributes #1, Désignation: EL-013
Baie de porte | RDC | Nouvelle construction | Béton et béton armé | 0100Por0000028690 | m³ | Baie de porte | AllplanAttributes - Object Layer Attributes #1, Mode_d'ouverture_porte: -
CVC-056 | RDC | Nouvelle construction | Maçonnerie | 0100NiM0000036243 | m³ | Niche | AllplanAttributes - Object Layer Attributes #1, Désignation: CVC-056
CVC-055 | RDC | Nouvelle construction | Maçonnerie | 0100NiM0000036220 | m³ | Niche
CVC-054 | RDC | Nouvelle construction | Maçonnerie | 0100NiM0000036135 | m³ | Niche
CVC-074 | RDC | Nouvelle construction | Maçonnerie | 0100NiM0000035937 | m³ | Niche | AllplanAttributes - Object Layer Attributes #1, Désignation: CVC-074
Percement dans mur | RDC | Nouvelle construction | Maçonnerie | 0100PeM0000026281 | m³ | Percement dans un mur
PB-RDC-20 | RDC | Nouvelle construction | Maçonnerie | 0100PeM0000029174 | m³ | Percement dans un mur | AllplanAttributes - Object Layer Attributes #1, Désignation: PB-RDC-20
Baie de porte | RDC | Nouvelle construction | Béton et béton armé | 0100Por0000027672 | m³ | Baie de porte | AllplanAttributes - Object Layer Attributes #1, Mode_d'ouverture_porte: DIN L
CVC-077 | RDC | Nouvelle construction | Maçonnerie | 0100NiM0000035851 | m³ | Niche | AllplanAttributes - Object Layer Attributes #1, Désignation: CVC-077
CVC-077 | RDC | Nouvelle construction | Maçonnerie | 0100NiM0000042597 | m³ | Niche | AllplanAttributes - Object Layer Attributes #1, Désignation: CVC-077
CVC-073 | RDC | Nouvelle construction | Maçonnerie | 0100NiM0000035866 | m³ | Niche | AllplanAttributes - Object Layer Attributes #1, Désignation: CVC-073
Percement dans mur | RDC | Nouvelle construction | Maçonnerie | 0100PeM0000026193 | m³ | Percement dans un mur
Percement dans mur | RDC | Nouvelle construction | Maçonnerie | 0100PeM0000026320 | m³ | Percement dans un mur
Percement dans mur | RDC | Nouvelle construction | Maçonnerie | 0100PeM0000026333 | m³ | Percement dans un mur
PB-RDC-28 | RDC | Nouvelle construction | Maçonnerie | 0100PeM0000029148 | m³ | Percement dans un mur | AllplanAttributes - Object Layer Attributes #1, Désignation: PB-RDC-28
Baie de porte | RDC | Nouvelle construction | Béton et béton armé | 0100Por0000027662 | m³ | Baie de porte | AllplanAttributes - Object Layer Attributes #1, Mode_d'ouverture_porte: DIN L
CVC-070 | RDC | Nouvelle construction | Maçonnerie | 0100NiM0000035950 | m³ | Niche | AllplanAttributes - Object Layer Attributes #1, Désignation: CVC-070
Percement dans mur | RDC | Nouvelle construction | Maçonnerie | 0100PeM0000026206 | m³ | Percement dans un mur
Percement dans mur | RDC | Nouvelle construction | Maçonnerie | 0100PeM0000026294 | m³ | Percement dans un mur
Baie de fenêtre | RDC | Nouvelle construction | Fenêtrage | 0100Fen0000028082 | m³ | Baie de fenêtre
Baie de fenêtre | RDC | Nouvelle construction | Fenêtrage | 0100Fen0000028073 | m³ | Baie de fenêtre
Baie de fenêtre | RDC | Nouvelle construction | Fenêtrage | 0100Fen0000028062 | m³ | Baie de fenêtre
CVC-087 | RDC | Nouvelle construction | Maçonnerie | 0100NiM0000035155 | m³ | Niche
CVC-078 | RDC | Nouvelle construction | Maçonnerie | 0100NiM0000035346 | m³ | Niche | AllplanAttributes - Object Layer Attributes #1, Désignation: CVC-078
CVC-081 | RDC | Nouvelle construction | Maçonnerie | 0100NiM0000035331 | m³ | Niche
Baie de porte | RDC | Nouvelle construction | Béton et béton armé | 0100Por0000027724 | m³ | Baie de porte | AllplanAttributes - Object Layer Attributes #1, Mode_d'ouverture_porte: DIN L
Percement dans mur | RDC | Nouvelle construction | Maçonnerie | 0100PeM0000026180 | m³ | Percement dans un mur
Percement dans mur | RDC | Nouvelle construction | Maçonnerie | 0100PeM0000026359 | m³ | Percement dans un mur
Percement dans mur | RDC | Nouvelle construction | Maçonnerie | 0100PeM0000026346 | m³ | Percement dans un mur
PB-RDC-30 | RDC | Nouvelle construction | Maçonnerie | 0100PeM0000029135 | m³ | Percement dans un mur | AllplanAttributes - Object Layer Attributes #1, Désignation: PB-RDC-30
CVC-088 | RDC | Nouvelle construction | Maçonnerie | 0100NiM0000035142 | m³ | Niche | AllplanAttributes - Object Layer Attributes #1, Désignation: CVC-088
EL-011 | RDC | Nouvelle construction | Maçonnerie | 0100NiM0000039497 | m³ | Niche | AllplanAttributes - Object Layer Attributes #1, Désignation: EL-011
EL-014 | RDC | Nouvelle construction | Maçonnerie | 0100NiM0000039477 | m³ | Niche | AllplanAttributes - Object Layer Attributes #1, Désignation: EL-014
CVC-089 | RDC | Nouvelle construction | Maçonnerie | 0100NiM0000035124 | m³ | Niche | AllplanAttributes - Object Layer Attributes #1, Désignation: CVC-089
Percement dans mur | RDC | Nouvelle construction | Maçonnerie | 0100PeM0000026167 | m³ | Percement dans un mur
Percement dans mur | RDC | Nouvelle construction | Maçonnerie | 0100PeM0000026385 | m³ | Percement dans un mur
Percement dans mur | RDC | Nouvelle construction | Maçonnerie | 0100PeM0000026372 | m³ | Percement dans un mur
PB-RDC-31 | RDC | Nouvelle construction | Maçonnerie | 0100PeM0000029105 | m³ | Percement dans un mur | AllplanAttributes - Object Layer Attributes #1, Désignation: PB-RDC-31
PB-RDC-32 | RDC | Nouvelle construction | Maçonnerie | 0100PeM0000029120 | m³ | Percement dans un mur | AllplanAttributes - Object Layer Attributes #1, Désignation: PB-RDC-32
Baie de porte | RDC | Nouvelle construction | Béton et béton armé | 0100Por0000027549 | m³ | Baie de porte | AllplanAttributes - Object Layer Attributes #1, Mode_d'ouverture_porte: DIN R
Baie de porte | RDC | Nouvelle construction | Béton et béton armé | 0100Por0000027539 | m³ | Baie de porte | AllplanAttributes - Object Layer Attributes #1, Mode_d'ouverture_porte: DIN R
CVC-083 | RDC | Nouvelle construction | Maçonnerie | 0100NiM0000035216 | m³ | Niche | AllplanAttributes - Object Layer Attributes #1, Désignation: CVC-083
CVC-080 | RDC | Nouvelle construction | Maçonnerie | 0100NiM0000035229 | m³ | Niche
CVC-085 | RDC | Nouvelle construction | Maçonnerie | 0100NiM0000035198 | m³ | Niche | AllplanAttributes - Object Layer Attributes #1, Désignation: CVC-085
Percement dans mur | RDC | Nouvelle construction | Maçonnerie | 0100NiM0000026037 | m³ | Niche
CVC-093 | RDC | Nouvelle construction | Maçonnerie | 0100NiM0000035185 | m³ | Niche | AllplanAttributes - Object Layer Attributes #1, Désignation: CVC-093
CVC-084 | RDC | Nouvelle construction | Maçonnerie | 0100NiM0000035172 | m³ | Niche | AllplanAttributes - Object Layer Attributes #1, Désignation: CVC-084
Percement dans mur | RDC | Nouvelle construction | Maçonnerie | 0100PeM0000025732 | m³ | Percement dans un mur
Percement dans mur | RDC | Nouvelle construction | Maçonnerie | 0100PeM0000026005 | m³ | Percement dans un mur
Baie de porte | RDC | Nouvelle construction | Béton et béton armé | 0100Por0000027559 | m³ | Baie de porte | AllplanAttributes - Object Layer Attributes #1, Mode_d'ouverture_porte: DIN L
Baie de porte | RDC | Nouvelle construction | Béton et béton armé | 0100Por0000027464 | m³ | Baie de porte | AllplanAttributes - Object Layer Attributes #1, Mode_d'ouverture_porte: -
Baie de porte | RDC | Nouvelle construction | Béton et béton armé | 0100Por0000027480 | m³ | Baie de porte | AllplanAttributes - Object Layer Attributes #1, Mode_d'ouverture_porte: -
Baie de fenêtre | RDC | Nouvelle construction | Fenêtrage | 0100Fen0000027969 | m³ | Baie de fenêtre
Baie de porte | RDC | Nouvelle construction | Béton et béton armé | 0100Por0000027961 | m³ | Baie de porte | AllplanAttributes - Object Layer Attributes #1, Mode_d'ouverture_porte: DIN R
Baie de porte | RDC | Nouvelle construction | Béton et béton armé | 0100Por0000027945 | m³ | Baie de porte | AllplanAttributes - Object Layer Attributes #1, Mode_d'ouverture_porte: DIN R
Baie de porte | RDC | Nouvelle construction | Béton et béton armé | 0100Por0000027607 | m³ | Baie de porte | AllplanAttributes - Object Layer Attributes #1, Mode_d'ouverture_porte: -
CVC-124 | RDC | Nouvelle construction | Maçonnerie | 0100NiM0000032230 | m³ | Niche | AllplanAttributes - Object Layer Attributes #1, Désignation: CVC-124
CVC-123 | RDC | Nouvelle construction | Maçonnerie | 0100NiM0000032224 | m³ | Niche | AllplanAttributes - Object Layer Attributes #1, Désignation: CVC-123
CVC-121 | RDC | Nouvelle construction | Maçonnerie | 0100NiM0000032244 | m³ | Niche | AllplanAttributes - Object Layer Attributes #1, Désignation: CVC-121
CVC-120 | RDC | Nouvelle construction | Maçonnerie | 0100NiM0000032250 | m³ | Niche
CVC-122 | RDC | Nouvelle construction | Maçonnerie | 0100NiM0000032236 | m³ | Niche
CVC-117 | RDC | Nouvelle construction | Maçonnerie | 0100NiM0000039744 | m³ | Niche | AllplanAttributes - Object Layer Attributes #1, Désignation: CVC-117
Baie de porte | RDC | Nouvelle construction | Béton et béton armé | 0100Por0000028125 | m³ | Baie de porte | AllplanAttributes - Object Layer Attributes #1, Mode_d'ouverture_porte: DIN L
Percement dans mur | RDC | Nouvelle construction | Maçonnerie | 0100NiM0000029092 | m³ | Niche
Percement dans mur | RDC | Nouvelle construction | Maçonnerie | 0100PeM0000026128 | m³ | Percement dans un mur
Baie de porte | RDC | Nouvelle construction | Béton et béton armé | 0100Por0000027732 | m³ | Baie de porte | AllplanAttributes - Object Layer Attributes #1, Mode_d'ouverture_porte: DIN R
Percement dans mur | RDC | Nouvelle construction | Maçonnerie | 0100PeM0000026115 | m³ | Percement dans un mur
CVC-130 | RDC | Nouvelle construction | Maçonnerie | 0100NiM0000032296 | m³ | Niche | AllplanAttributes - Object Layer Attributes #1, Désignation: CVC-130
CVC-096 | RDC | Nouvelle construction | Maçonnerie | 0100NiM0000032258 | m³ | Niche | AllplanAttributes - Object Layer Attributes #1, Désignation: CVC-096
CVC-094 | RDC | Nouvelle construction | Maçonnerie | 0100NiM0000032270 | m³ | Niche | AllplanAttributes - Object Layer Attributes #1, Désignation: CVC-094
CVC-095 | RDC | Nouvelle construction | Maçonnerie | 0100NiM0000032264 | m³ | Niche | AllplanAttributes - Object Layer Attributes #1, Désignation: CVC-095
PB-RDC-34 | RDC | Nouvelle construction | Maçonnerie | 0100PeM0000029079 | m³ | Percement dans un mur | AllplanAttributes - Object Layer Attributes #1, Désignation: PB-RDC-34
CVC-102 | RDC | Nouvelle construction | Maçonnerie | 0100NiM0000032276 | m³ | Niche | AllplanAttributes - Object Layer Attributes #1, Désignation: CVC-102
Baie de porte | RDC | Nouvelle construction | Béton et béton armé | 0100Por0000027758 | m³ | Baie de porte | AllplanAttributes - Object Layer Attributes #1, Mode_d'ouverture_porte: DIN L
Percement dans mur | RDC | Nouvelle construction | Maçonnerie | 0100NiM0000026077 | m³ | Niche
Percement dans mur | RDC | Nouvelle construction | Maçonnerie | 0100PeM0000026141 | m³ | Percement dans un mur
CVC-107 | RDC | Nouvelle construction | Maçonnerie | 0100NiM0000040338 | m³ | Niche | AllplanAttributes - Object Layer Attributes #1, Désignation: CVC-107
CVC-108 | RDC | Nouvelle construction | Maçonnerie | 0100NiM0000040239 | m³ | Niche | AllplanAttributes - Object Layer Attributes #1, Désignation: CVC-108
CVC-100 | RDC | Nouvelle construction | Maçonnerie | 0100NiM0000032196 | m³ | Niche
CVC-099 | RDC | Nouvelle construction | Maçonnerie | 0100NiM0000032206 | m³ | Niche | AllplanAttributes - Object Layer Attributes #1, Désignation: CVC-099
CVC-097 | RDC | Nouvelle construction | Maçonnerie | 0100NiM0000032218 | m³ | Niche | AllplanAttributes - Object Layer Attributes #1, Désignation: CVC-097
CVC-098 | RDC | Nouvelle construction | Maçonnerie | 0100NiM0000032212 | m³ | Niche | AllplanAttributes - Object Layer Attributes #1, Désignation: CVC-098
Percement dans mur | RDC | Nouvelle construction | Maçonnerie | 0100PeM0000026413 | m³ | Percement dans un mur
Percement dans mur | RDC | Nouvelle construction | Maçonnerie | 0100PeM0000026439 | m³ | Percement dans un mur
Percement dans mur | RDC | Nouvelle construction | Maçonnerie | 0100PeM0000025715 | m³ | Percement dans un mur
Baie de porte | RDC | Nouvelle construction | Béton et béton armé | 0100Por0000027522 | m³ | Baie de porte | AllplanAttributes - Object Layer Attributes #1, Mode_d'ouverture_porte: DIN L
PB-RDC-35 | RDC | Nouvelle construction | Maçonnerie | 0100PeM0000029051 | m³ | Percement dans un mur | AllplanAttributes - Object Layer Attributes #1, Désignation: PB-RDC-35
PB-RDC-36 | RDC | Nouvelle construction | Maçonnerie | 0100PeM0000029038 | m³ | Percement dans un mur | AllplanAttributes - Object Layer Attributes #1, Désignation: PB-RDC-36
PB-RDC-38 | RDC | Nouvelle construction | Maçonnerie | 0100PeM0000029025 | m³ | Percement dans un mur | AllplanAttributes - Object Layer Attributes #1, Désignation: PB-RDC-38
Baie de porte | RDC | Nouvelle construction | Béton et béton armé | 0100Por0000027530 | m³ | Baie de porte | AllplanAttributes - Object Layer Attributes #1, Mode_d'ouverture_porte: DIN L
CVC-105 | RDC | Nouvelle construction | Maçonnerie | 0100NiM0000032174 | m³ | Niche | AllplanAttributes - Object Layer Attributes #1, Désignation: CVC-105
CVC-118 | RDC | Nouvelle construction | Maçonnerie | 0100NiM0000032168 | m³ | Niche | AllplanAttributes - Object Layer Attributes #1, Désignation: CVC-118
Percement dans mur | RDC | Nouvelle construction | Maçonnerie | 0100PeM0000026426 | m³ | Percement dans un mur
CVC-090 | RDC | Nouvelle construction | Maçonnerie | 0100NiM0000032326 | m³ | Niche | AllplanAttributes - Object Layer Attributes #1, Désignation: CVC-090
Baie de porte | RDC | Nouvelle construction | Béton et béton armé | 0100Por0000027786 | m³ | Baie de porte | AllplanAttributes - Object Layer Attributes #1, Mode_d'ouverture_porte: DIN L
Percement dans mur | RDC | Nouvelle construction | Maçonnerie | 0100PeM0000026400 | m³ | Percement dans un mur
CVC-119 | RDC | Nouvelle construction | Maçonnerie | 0100NiM0000032134 | m³ | Niche | AllplanAttributes - Object Layer Attributes #1, Désignation: CVC-119
CVC-106 | RDC | Nouvelle construction | Maçonnerie | 0100NiM0000032146 | m³ | Niche
Percement dans mur | RDC | Nouvelle construction | Maçonnerie | 0100PeM0000026465 | m³ | Percement dans un mur
Percement dans mur | RDC | Nouvelle construction | Maçonnerie | 0100PeM0000025695 | m³ | Percement dans un mur
CVC-101 | RDC | Nouvelle construction | Maçonnerie | 0100NiM0000040030 | m³ | Niche
Percement dans mur | RDC | Nouvelle construction | Maçonnerie | 0100PeM0000026452 | m³ | Percement dans un mur
PB-RDC-37 | RDC | Nouvelle construction | Maçonnerie | 0100PeM0000029066 | m³ | Percement dans un mur | AllplanAttributes - Object Layer Attributes #1, Désignation: PB-RDC-37
Percement dans mur | RDC | Nouvelle construction | Maçonnerie | 0100PeM0000026491 | m³ | Percement dans un mur
PB-RDC-39 | RDC | Nouvelle construction | Maçonnerie | 0100PeM0000028925 | m³ | Percement dans un mur | AllplanAttributes - Object Layer Attributes #1, Désignation: PB-RDC-39
CVC-110 | RDC | Nouvelle construction | Maçonnerie | 0100NiM0000032154 | m³ | Niche | AllplanAttributes - Object Layer Attributes #1, Désignation: CVC-110
CVC-107 | RDC | Nouvelle construction | Maçonnerie | 0100NiM0000032162 | m³ | Niche | AllplanAttributes - Object Layer Attributes #1, Désignation: CVC-107
Percement dans mur | RDC | Nouvelle construction | Maçonnerie | 0100PeM0000026478 | m³ | Percement dans un mur
PB-RDC-41 | RDC | Nouvelle construction | Maçonnerie | 0100PeM0000028773 | m³ | Percement dans un mur | AllplanAttributes - Object Layer Attributes #1, Désignation: PB-RDC-41
CVC-113 | RDC | Nouvelle construction | Maçonnerie | 0100PeM0000031763 | m³ | Percement dans un mur | AllplanAttributes - Object Layer Attributes #1, Désignation: CVC-113
CVC-114 | RDC | Nouvelle construction | Maçonnerie | 0100PeM0000032059 | m³ | Percement dans un mur | AllplanAttributes - Object Layer Attributes #1, Désignation: CVC-114
Baie de fenêtre | RDC | Nouvelle construction | Fenêtrage | 0100Fen0000028017 | m³ | Baie de fenêtre
Baie de fenêtre | RDC | Nouvelle construction | Fenêtrage | 0100Fen0000028032 | m³ | Baie de fenêtre
Baie de fenêtre | RDC | Nouvelle construction | Fenêtrage | 0100Fen0000028042 | m³ | Baie de fenêtre
Baie de fenêtre | RDC | Nouvelle construction | Fenêtrage | 0100Fen0000028052 | m³ | Baie de fenêtre
CVC-116 | RDC | Nouvelle construction | Maçonnerie | 0100NiM0000035109 | m³ | Niche
CVC-115 | RDC | Nouvelle construction | Maçonnerie | 0100PeM0000032072 | m³ | Percement dans un mur | AllplanAttributes - Object Layer Attributes #1, Désignation: CVC-115
Baie de porte | RDC | Nouvelle construction | Béton et béton armé | 0100Por0000028090 | m³ | Baie de porte | AllplanAttributes - Object Layer Attributes #1, Mode_d'ouverture_porte: DIN L
CVC-128 | RDC | Nouvelle construction | Maçonnerie | 0100NiM0000035242 | m³ | Niche | AllplanAttributes - Object Layer Attributes #1, Désignation: CVC-128
EL-006 | RDC | Nouvelle construction | Maçonnerie | 0100NiM0000039393 | m³ | Niche | AllplanAttributes - Object Layer Attributes #1, Désignation: EL-006
CVC-082 | RDC | Nouvelle construction | Maçonnerie | 0100NiM0000035297 | m³ | Niche | AllplanAttributes - Object Layer Attributes #1, Désignation: CVC-082
EL-009 | RDC | Nouvelle construction | Maçonnerie | 0100NiM0000039415 | m³ | Niche | AllplanAttributes - Object Layer Attributes #1, Désignation: EL-009
CVC-086 | RDC | Nouvelle construction | Maçonnerie | 0100NiM0000035314 | m³ | Niche
CVC-079 | RDC | Nouvelle construction | Maçonnerie | 0100NiM0000035280 | m³ | Niche | AllplanAttributes - Object Layer Attributes #1, Désignation: CVC-079
Baie de porte | RDC | Nouvelle construction | Béton et béton armé | 0100Por0000044747 | m³ | Baie de porte | AllplanAttributes - Object Layer Attributes #1, Mode_d'ouverture_porte: -
Percement dans mur | RDC | Nouvelle construction | Maçonnerie | 0100PeM0000025948 | m³ | Percement dans un mur
CVC-126 | RDC | Nouvelle construction | Maçonnerie | 0100NiM0000035267 | m³ | Niche | AllplanAttributes - Object Layer Attributes #1, Désignation: CVC-126
Percement dans mur | RDC | Nouvelle construction | Maçonnerie | 0100PeM0000025913 | m³ | Percement dans un mur
Percement dans mur | RDC | Nouvelle construction | Maçonnerie | 0100PeM0000025786 | m³ | Percement dans un mur
Baie de porte | RDC | Nouvelle construction | Béton et béton armé | 0100Por0000027569 | m³ | Baie de porte | AllplanAttributes - Object Layer Attributes #1, Mode_d'ouverture_porte: DIN R
CVC-127 | RDC | Nouvelle construction | Maçonnerie | 0100NiM0000044783 | m³ | Niche | AllplanAttributes - Object Layer Attributes #1, Désignation: CVC-127
CVC-125 | RDC | Nouvelle construction | Maçonnerie | 0100NiM0000044768 | m³ | Niche | AllplanAttributes - Object Layer Attributes #1, Désignation: CVC-125
Baie de porte | RDC | Nouvelle construction | Béton et béton armé | 0100Por0000044711 | m³ | Baie de porte | AllplanAttributes - Object Layer Attributes #1, Mode_d'ouverture_porte: -
CVC-091 | RDC | Nouvelle construction | Maçonnerie | 0100NiM0000032282 | m³ | Niche | AllplanAttributes - Object Layer Attributes #1, Désignation: CVC-091
Percement dans mur | RDC | Nouvelle construction | Maçonnerie | 0100PeM0000026154 | m³ | Percement dans un mur
Percement dans mur | RDC | Nouvelle construction | Maçonnerie | 0100PeM0000026102 | m³ | Percement dans un mur
Percement dans mur | RDC | Nouvelle construction | Maçonnerie | 0100PeM0000026247 | m³ | Percement dans un mur
PB-RDC-21-23 | RDC | Nouvelle construction | Maçonnerie | 0100PeM0000030866 | m³ | Percement dans un mur | AllplanAttributes - Object Layer Attributes #1, Désignation: PB-RDC-21-23
Niche dans mur | RDC | Nouvelle construction | Maçonnerie | 0100NiM0000036292 | m³ | Niche
Niche dans mur | RDC | Nouvelle construction | Maçonnerie | 0100NiM0000036318 | m³ | Niche
Niche dans mur | RDC | Nouvelle construction | Maçonnerie | 0100NiM0000036344 | m³ | Niche
Niche dans mur | RDC | Nouvelle construction | Maçonnerie | 0100NiM0000036396 | m³ | Niche
Niche dans mur | RDC | Nouvelle construction | Maçonnerie | 0100NiM0000036370 | m³ | Niche
Niche dans mur | RDC | Nouvelle construction | Maçonnerie | 0100NiM0000036266 | m³ | Niche
CVC-112 | RDC | Nouvelle construction | Maçonnerie | 0100PeM0000031704 | m³ | Percement dans un mur | AllplanAttributes - Object Layer Attributes #1, Désignation: CVC-112
Percement dans mur | RDC | Nouvelle construction | Maçonnerie | 0100PeM0000039857 | m³ | Percement dans un mur
Percement dans mur | RDC | Nouvelle construction | Maçonnerie | 0100PeM0000025632 | m³ | Percement dans un mur
CVC-111 | RDC | Nouvelle construction | Maçonnerie | 0100PeM0000031513 | m³ | Percement dans un mur | AllplanAttributes - Object Layer Attributes #1, Désignation: CVC-111
PB-RDC-40 | RDC | Nouvelle construction | Maçonnerie | 0100PeM0000028892 | m³ | Percement dans un mur | AllplanAttributes - Object Layer Attributes #1, Désignation: PB-RDC-40
Baie de porte | RDC | Nouvelle construction | Béton et béton armé | 0100Por0000027494 | m³ | Baie de porte | AllplanAttributes - Object Layer Attributes #1, Mode_d'ouverture_porte: DIN L
Baie de porte | RDC | Nouvelle construction | Béton et béton armé | 0100Por0000027502 | m³ | Baie de porte | AllplanAttributes - Object Layer Attributes #1, Mode_d'ouverture_porte: DIN R
CVC-058 | RDC | Nouvelle construction | Maçonnerie | 0100NiM0000065098 | m³ | Niche | AllplanAttributes - Object Layer Attributes #1, Désignation: CVC-058
CVC-059 | RDC | Nouvelle construction | Maçonnerie | 0100NiM0000065118 | m³ | Niche | AllplanAttributes - Object Layer Attributes #1, Désignation: CVC-059
CVC-053 | RDC | Nouvelle construction | Maçonnerie | 0100NiM0000065162 | m³ | Niche | AllplanAttributes - Object Layer Attributes #1, Désignation: CVC-053
CVC-052 | RDC | Nouvelle construction | Maçonnerie | 0100NiM0000065151 | m³ | Niche | AllplanAttributes - Object Layer Attributes #1, Désignation: CVC-052
CVC-061 | RDC | Nouvelle construction | Maçonnerie | 0100NiM0000065140 | m³ | Niche | AllplanAttributes - Object Layer Attributes #1, Désignation: CVC-061
CVC-060 | RDC | Nouvelle construction | Maçonnerie | 0100NiM0000065129 | m³ | Niche | AllplanAttributes - Object Layer Attributes #1, Désignation: CVC-060
Percement dans mur | RDC | Nouvelle construction | Maçonnerie | 0100PeM0000065209 | m³ | Percement dans un mur
Percement dans mur | RDC | Nouvelle construction | Maçonnerie | 0100PeM0000065200 | m³ | Percement dans un mur
Percement dans mur | RDC | Nouvelle construction | Maçonnerie | 0100PeM0000065191 | m³ | Percement dans un mur
Percement dans mur | RDC | Nouvelle construction | Maçonnerie | 0100PeM0000065182 | m³ | Percement dans un mur
Niche dans mur | RDC | Nouvelle construction | Maçonnerie | 0100NiM0000066383 | m³ | Niche
Percement dans mur | RDC | Nouvelle construction | Maçonnerie | 0100PeM0000065173 | m³ | Percement dans un mur
Percement dans mur | RDC | Nouvelle construction | Maçonnerie | 0100PeM0000062764 | m³ | Percement dans un mur
Baie de porte | RDC | Nouvelle construction | Béton et béton armé | 0100Por0000028341 | m³ | Baie de porte | AllplanAttributes - Object Layer Attributes #1, Mode_d'ouverture_porte: -
Baie de porte | RDC | Nouvelle construction | Béton et béton armé | 0100Por0000028566 | m³ | Baie de porte | AllplanAttributes - Object Layer Attributes #1, Mode_d'ouverture_porte: -
CVC-082 | RDC | Nouvelle construction | Maçonnerie | 0100NiM0000036614 | m³ | Niche
CVC-082 | RDC | Nouvelle construction | Maçonnerie | 0100NiM0000036588 | m³ | Niche
CVC-082 | RDC | Nouvelle construction | Maçonnerie | 0100NiM0000036562 | m³ | Niche
CVC-082 | RDC | Nouvelle construction | Maçonnerie | 0100NiM0000036532 | m³ | Niche
CVC-082 | RDC | Nouvelle construction | Maçonnerie | 0100NiM0000036519 | m³ | Niche
CVC-082 | RDC | Nouvelle construction | Maçonnerie | 0100NiM0000036465 | m³ | Niche
CVC-082 | RDC | Nouvelle construction | Maçonnerie | 0100NiM0000036437 | m³ | Niche
Percement dans mur | RDC | Nouvelle construction | Maçonnerie | 0100PeM0000062979 | m³ | Percement dans un mur
Percement dans mur | RDC | Nouvelle construction | Maçonnerie | 0100PeM0000062963 | m³ | Percement dans un mur
Percement dans mur | RDC | Nouvelle construction | Maçonnerie | 0100PeM0000062886 | m³ | Percement dans un mur
CVC-082 | RDC | Nouvelle construction | Maçonnerie | 0100NiM0000036493 | m³ | Niche
CVC-033 | RDC | Nouvelle construction | Maçonnerie | 0100NiM0000038260 | m³ | Niche | AllplanAttributes - Object Layer Attributes #1, Désignation: CVC-033
CVC-031 | RDC | Nouvelle construction | Maçonnerie | 0100NiM0000038436 | m³ | Niche | AllplanAttributes - Object Layer Attributes #1, Désignation: CVC-031
CVC-032 | RDC | Nouvelle construction | Maçonnerie | 0100NiM0000038337 | m³ | Niche | AllplanAttributes - Object Layer Attributes #1, Désignation: CVC-032
Trémie dans dalle | RDC | Nouvelle construction |  | 0100TrD0000068501 | m³ | Trémie
Trémie dans dalle | RDC | Nouvelle construction |  | 0100TrD0000068486 | m³ | Trémie
Trémie dans dalle | RDC | Nouvelle construction |  | 0100TrD0000068468 | m³ | Trémie
Trémie dans dalle | RDC | Nouvelle construction |  | 0100TrD0000031301 | m³ | Trémie
Trémie dans dalle | RDC | Nouvelle construction |  | 0100TrD0000068547 | m³ | Trémie
Baie de porte | RDC | Nouvelle construction | Béton et béton armé | 0100Por0000028663 | m³ | Baie de porte | AllplanAttributes - Object Layer Attributes #1, Mode_d'ouverture_porte: -
Baie de porte | RDC | Nouvelle construction | Béton et béton armé | 0100Por0000028334 | m³ | Baie de porte | AllplanAttributes - Object Layer Attributes #1, Mode_d'ouverture_porte: -
Niche dans mur | RDC | Nouvelle construction | Maçonnerie | 0100NiM0000036422 | m³ | Niche
Niche dans mur | RDC | Nouvelle construction | Maçonnerie | 0100NiM0000036452 | m³ | Niche
Niche dans mur | RDC | Nouvelle construction | Maçonnerie | 0100NiM0000036506 | m³ | Niche
Niche dans mur | RDC | Nouvelle construction | Maçonnerie | 0100NiM0000036547 | m³ | Niche
Niche dans mur | RDC | Nouvelle construction | Maçonnerie | 0100NiM0000036575 | m³ | Niche
Niche dans mur | RDC | Nouvelle construction | Maçonnerie | 0100NiM0000036601 | m³ | Niche
Niche dans mur | RDC | Nouvelle construction | Maçonnerie | 0100NiM0000036627 | m³ | Niche
Niche dans mur | RDC | Nouvelle construction | Maçonnerie | 0100NiM0000036478 | m³ | Niche
Percement dans mur | RDC | Nouvelle construction | Maçonnerie | 0100PeM0000063007 | m³ | Percement dans un mur
Trémie dans dalle | RDC | Nouvelle construction |  | 0100TrD0000068461 | m³ | Trémie
Trémie dans dalle | RDC | Nouvelle construction |  | 0100TrD0000038198 | m³ | Trémie
Trémie dans dalle | RDC | Nouvelle construction |  | 0100TrD0000038246 | m³ | Trémie
Trémie dans dalle | RDC | Nouvelle construction |  | 0100TrD0000031265 | m³ | Trémie
Trémie dans dalle | RDC | Nouvelle construction |  | 0100TrD0000038253 | m³ | Trémie
Trémie dans dalle | RDC | Nouvelle construction |  | 0100TrD0000038239 | m³ | Trémie
Trémie dans dalle | RDC | Nouvelle construction |  | 0100TrD0000031296 | m³ | Trémie

# IfcOpeningElement: Recess (4)
In: SOUS-SOL
AllplanAttributes - Object Layer Attributes #1, Catégorie de transformation: Nouvelle construction; Object Layer Attributes #1, Unité: m³; Object Layer Attributes #1, Nom_de_macro: Evidement dans dalle
Name | Object Layer Attributes #1, Id_élt_Allmétré
Evidement dans dalle | 0050Epl1613172612
Evidement dans dalle | 0050Epl1612776549
Evidement dans dalle | 0050Epl1613172619
Evidement dans dalle | 0050Epl1612776544

# IfcSlab (108)
PredefinedType: FLOOR
AllplanAttributes - Catégorie de transformation: Nouvelle construction; RATIO_HA: 5; Reserve_sol: 0; G: 150; Q: 150; Unité: m³; Nom_de_macro: Dalle
Pset_SlabCommon - LoadBearing: yes
Name | In | Material = Matériau | Id_élt_Allmétré
 | FONDATIONS | Dalle_BA | 0010Dal1612709901
 | FONDATIONS | Dalle_BA | 0010Dal1612709872
 | FONDATIONS | Dalle_BA | 0010Dal1612656045
 | FONDATIONS | Dalle_BA | 0010Dal1612656051
 | FONDATIONS | Dalle_BA | 0010Dal1612656048
 | FONDATIONS | Dalle_BA | 0010Dal1612668497
 | FONDATIONS | Dalle_BA | 0010Dal1612709087
 | FONDATIONS | Dalle_BA | 0010Dal1612656057
 | FONDATIONS | Dalle_BA | 0010Dal1612676011
 | FONDATIONS | Dalle_BA | 0010Dal1612675862
 | FONDATIONS | Dalle_BA | 0010Dal1612674850
 | FONDATIONS | Dalle_BA | 0010Dal1612656066
 | FONDATIONS | Dalle_BA | 0010Dal1612656063
 | FONDATIONS | Dalle_BA | 0010Dal1612656060
 | FONDATIONS | Dalle_BA | 0010Dal1612667444
 | FONDATIONS | Dalle_BA | 0010Dal1612706628
 | FONDATIONS | Dalle_BA | 0010Dal1612673807
 | FONDATIONS | Dalle_BA | 0010Dal1612668621
 | FONDATIONS | Dalle_BA | 0010Dal1612656078
 | FONDATIONS | Dalle_BA | 0010Dal1612667423
 | FONDATIONS | Dalle_BA | 0010Dal1612667405
 | FONDATIONS | Dalle_BA | 0010Dal1612667288
 | FONDATIONS | Dalle_BA | 0010Dal1612667169
 | FONDATIONS | Dalle_BA | 0010Dal1612666934
 | FONDATIONS | Dalle_BA | 0010Dal1612667436
 | FONDATIONS | Dalle_BA | 0010Dal1612659235
 | FONDATIONS | Dalle_BA | 0010Dal1612713121
 | FONDATIONS | Dalle_BA | 0010Dal1612710320
 | FONDATIONS | Dalle_BA | 0010Dal1612709405
 | FONDATIONS | Dalle_BA | 0010Dal1612656069
 | FONDATIONS | Dalle_BA | 0010Dal1612709970
 | FONDATIONS | Dalle_BA | 0010Dal1612709938
 | FONDATIONS | Dalle_BA | 0010Dal1612709839
 | FONDATIONS | Dalle_BA | 0010Dal1612709439
 | FONDATIONS | Dalle_BA | 0010Dal1612709644
 | FONDATIONS | Dalle_BA | 0010Dal1612673788
 | FONDATIONS | Dalle_BA | 0010Dal1612669698
 | FONDATIONS | Dalle_BA | 0010Dal1612721068
 | FONDATIONS | Dalle_BA | 0010Dal1612678570
 | FONDATIONS | Dalle_BA | 0010Dal1612706636
 | FONDATIONS | Dalle_BA | 0010Dal1612720868
 | FONDATIONS | Dalle_BA | 0010Dal1612667546
 | FONDATIONS | Béton | 0010Dal1612667088
 | FONDATIONS | Dalle_BA | 0010Dal1612654425
 | SOUS-SOL | Dalle_BA | 0050Dal1612726371
 | SOUS-SOL | Dalle_BA | 0050Dal1612732908
 | SOUS-SOL | Béton | 0050Dal1612685875
 | SOUS-SOL | Béton | 0050Dal1612686959
 | SOUS-SOL | Dalle_BA | 0050Dal1612726467
 | SOUS-SOL | Dalle_BA | 0050Dal1612726306
 | SOUS-SOL | Dalle_BA | 0050Dal1612726333
 | SOUS-SOL | Dalle_BA | 0050Dal1612726353
 | SOUS-SOL | Dalle_BA | 0050Dal1612726111
 | SOUS-SOL | Dalle_BA | 0050Dal1612726290
 | SOUS-SOL | Béton | 0050Dal1612694158
 | SOUS-SOL | Dalle_BA | 0050Dal1612726391
 | SOUS-SOL | Dalle_BA | 0050Dal1612726484
 | SOUS-SOL | Dalle_BA | 0050Dal1612662494
 | SOUS-SOL | Dalle_BA | 0050Dal1612662491
 | SOUS-SOL | Dalle_BA | 0050Dal1612711052
 | SOUS-SOL | Dalle_BA | 0050Dal1612790730
 | SOUS-SOL | Dalle_BA | 0050Dal1612708782
 | SOUS-SOL | Dalle_BA | 0050Dal1612665460
 | SOUS-SOL | Dalle_BA | 0050Dal1612778936
 | SOUS-SOL | Dalle_BA | 0050Dal1612755914
 | SOUS-SOL | Dalle_BA | 0050Dal1612662376
 | SOUS-SOL | Dalle_BA | 0050Dal1612790444
 | SOUS-SOL | Dalle_BA | 0050Dal1612657165
 | SOUS-SOL | Dalle_BA | 0050Dal1612791152
 | SOUS-SOL | Béton | 0050Dal1612716946
 | SOUS-SOL | Béton | 0050Dal1612662248
 | SOUS-SOL | Dalle_BA | 0050Dal1612761774
 | SOUS-SOL | Dalle_BA | 0050Dal1612776978
 | SOUS-SOL | Dalle_BA | 0050Dal1612769715
 | SOUS-SOL | Béton | 0050Dal1612739509
 | SOUS-SOL | Dalle_BA | 0050Dal1612741895
 | SOUS-SOL | Béton | 0050Dal1612662718
 | SOUS-SOL | Béton | 0050Dal1612729539
 | SOUS-SOL | Béton | 0050Dal1612694139
 | SOUS-SOL | Béton | 0050Dal1612694510
 | SOUS-SOL | Béton | 0050Dal1612736346
 | SOUS-SOL | Béton | 0050Dal1612726499
 | SOUS-SOL | Béton | 0050Dal1612662890
 | SOUS-SOL | Béton | 0050Dal1612662889
 | SOUS-SOL | Béton | 0050Dal1613195513
 | SOUS-SOL | Béton | 0050Dal1612743412
 | SOUS-SOL | Béton | 0050Dal1612700671
 | SOUS-SOL | Béton | 0050Dal1612742768
 | SOUS-SOL | Béton | 0050Dal1612742838
 | SOUS-SOL | Béton | 0050Dal1612662915
 | SOUS-SOL | Béton | 0050Dal1612662801
 | SOUS-SOL | Béton | 0050Dal1612743192
 | SOUS-SOL | Béton | 0050Dal1612700629
 | SOUS-SOL | Béton | 0050Dal1612700582
 | SOUS-SOL | Béton | 0050Dal1612726537
 | SOUS-SOL | Béton | 0050Dal1612739811
 | SOUS-SOL | Béton | 0050Dal1612662770
 | SOUS-SOL | Béton | 0050Dal1612743284
 | SOUS-SOL | Béton | 0050Dal1612726519
 | SOUS-SOL | Béton | 0050Dal1612726448
 | SOUS-SOL | Béton | 0050Dal1612726408
 | SOUS-SOL | Béton | 0050Dal1612743140
 | SOUS-SOL | Béton | 0050Dal1612741905
 | SOUS-SOL | Dalle_BA | 0050Dal1612780786
 | SOUS-SOL | Dalle_BA | 0050Dal1612774941
 | RDC | Béton | 0100Dal0000017330
 | RDC | Béton | 0100Dal0000017327
 | RDC | Béton | 0100Dal0000017309

# IfcStair (2)
In: SOUS-SOL
Material: Escalier droit
AllplanAttributes - Matériau: Escalier droit; Unité: Qt; Nom_de_macro: Escalier
Pset_StairCommon - TreadLength: 280 m
Name | Nombre de girons = NumberOfRiser | Id_élt_Allmétré | RiserHeight (m)
 | 16 | 0050Esc1612755990 | 162.5
 | 12 | 0050Esc1612756077 | 169.167

# IfcWall (16)
Material: Béton
AllplanAttributes - Unité: m³; Nom_de_macro: Mur entier; Object Layer Attributes #1, Catégorie de transformation: Nouvelle construction; Object Layer Attributes #1, Métier: Maçonnerie; Object Layer Attributes #1, Matériau: Béton; Object Layer Attributes #1, structure_porteur: no; Object Layer Attributes #1, Nom_de_macro: Mur
Name | In | Id_élt_Allmétré | Object Layer Attributes #1, RATIO_HA | Object Layer Attributes #1, Id_élt_Allmétré | Object Layer Attributes #1, Unité
 | SOUS-SOL | 0050HMu1612651841 | 5 | 0050Mu_1612651842 | m³
 | SOUS-SOL | 0050HMu1612653554 | 5 | 0050Mu_1612653555 | m³
 | SOUS-SOL | 0050HMu1612722670 | 5 | 0050Mu_1612722674 | m³
 | SOUS-SOL | 0050HMu1612722823 | 5 | 0050Mu_1612722845 | m³
 | SOUS-SOL | 0050HMu1612718151 | 5 | 0050Mu_1612718202 | m³
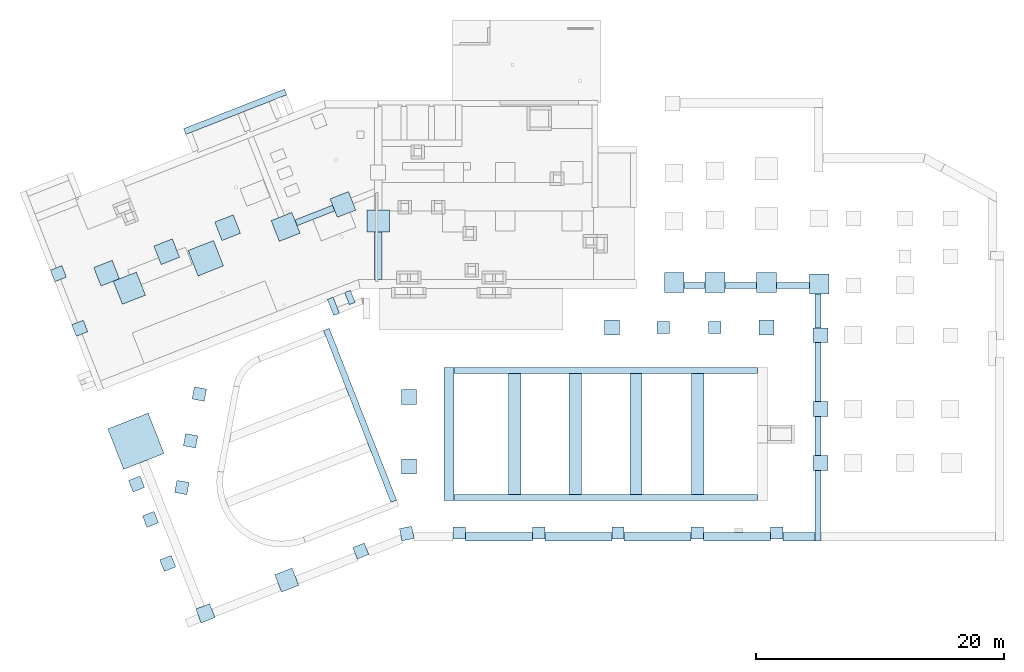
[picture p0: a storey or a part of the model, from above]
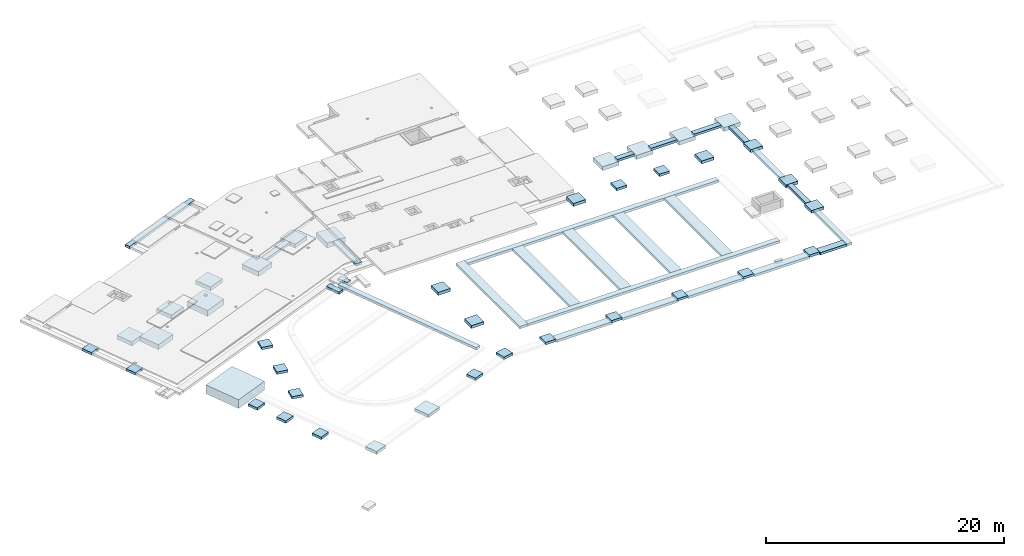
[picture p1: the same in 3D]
Properties of the parts of a building model (IFC2X3), part 4 of 4

# IfcWall (16)
Name | In | Id_élt_Allmétré | Object Layer Attributes #1, RATIO_HA | Object Layer Attributes #1, Id_élt_Allmétré | Object Layer Attributes #1, Unité
 | SOUS-SOL | 0050HMu1612755863 | 5 | 0050Mu_1612755865 | m³
 | SOUS-SOL | 0050HMu1612755965 | 5 | 0050Mu_1612755967 | m³
 | SOUS-SOL | 0050HMu1612656695 | 5 | 0050Mu_1612656697 | m³ | AllplanAttributes - Object Layer Attributes #2, Catégorie de transformation: Nouvelle construction; Object Layer Attributes #2, Métier: Maçonnerie; Object Layer Attributes #2, Matériau: Béton; Object Layer Attributes #2, structure_porteur: no; Object Layer Attributes #2, Id_élt_Allmétré: 0050Mu_1612771902; Object Layer Attributes #2, Unité: m²; Object Layer Attributes #2, Nom_de_macro: Mur; Object Layer Attributes #3, Catégorie de transformation: Nouvelle construction; Object Layer Attributes #3, Métier: Maçonnerie; Object Layer Attributes #3, Matériau: Béton; Object Layer Attributes #3, structure_porteur: no; Object Layer Attributes #3, Id_élt_Allmétré: 0050Mu_1612771903; Object Layer Attributes #3, Unité: m²; Object Layer Attributes #3, Nom_de_macro: Mur
 | SOUS-SOL | 0050HMu1612655688 |  | 0050Mu_1612655689 | m² | AllplanAttributes - Object Layer Attributes #2, Catégorie de transformation: Nouvelle construction; Object Layer Attributes #2, Métier: Maçonnerie; Object Layer Attributes #2, Matériau: Béton; Object Layer Attributes #2, structure_porteur: no; Object Layer Attributes #2, Id_élt_Allmétré: 0050Mu_1612772351; Object Layer Attributes #2, Unité: m²; Object Layer Attributes #2, Nom_de_macro: Mur; Object Layer Attributes #3, Catégorie de transformation: Nouvelle construction; Object Layer Attributes #3, Métier: Maçonnerie; Object Layer Attributes #3, Matériau: Béton; Object Layer Attributes #3, structure_porteur: no; Object Layer Attributes #3, Id_élt_Allmétré: 0050Mu_1612772352; Object Layer Attributes #3, Unité: m³; Object Layer Attributes #3, Nom_de_macro: Mur; Object Layer Attributes #3, RATIO_HA: 5
 | SOUS-SOL | 0050HMu1612655707 | 5 | 0050Mu_1612655708 | m³ | AllplanAttributes - Object Layer Attributes #2, Catégorie de transformation: Nouvelle construction; Object Layer Attributes #2, Métier: Maçonnerie; Object Layer Attributes #2, Matériau: Béton; Object Layer Attributes #2, structure_porteur: no; Object Layer Attributes #2, Id_élt_Allmétré: 0050Mu_1612772237; Object Layer Attributes #2, Unité: m²; Object Layer Attributes #2, Nom_de_macro: Mur; Object Layer Attributes #3, Catégorie de transformation: Nouvelle construction; Object Layer Attributes #3, Métier: Maçonnerie; Object Layer Attributes #3, Matériau: Béton; Object Layer Attributes #3, structure_porteur: no; Object Layer Attributes #3, Id_élt_Allmétré: 0050Mu_1612772238; Object Layer Attributes #3, Unité: m²; Object Layer Attributes #3, Nom_de_macro: Mur
 | SOUS-SOL | 0050HMu1613163896 | 5 | 0050Mu_1613163940 | m³ | AllplanAttributes - Object Layer Attributes #2, Catégorie de transformation: Nouvelle construction; Object Layer Attributes #2, Métier: Maçonnerie; Object Layer Attributes #2, Matériau: Béton; Object Layer Attributes #2, structure_porteur: no; Object Layer Attributes #2, Id_élt_Allmétré: 0050Mu_1613163903; Object Layer Attributes #2, Unité: m³; Object Layer Attributes #2, Nom_de_macro: Mur; Object Layer Attributes #3, Catégorie de transformation: Nouvelle construction; Object Layer Attributes #3, Métier: Maçonnerie; Object Layer Attributes #3, Matériau: Béton; Object Layer Attributes #3, structure_porteur: no; Object Layer Attributes #3, Id_élt_Allmétré: 0050Mu_1613163902; Object Layer Attributes #3, Unité: m³; Object Layer Attributes #3, Nom_de_macro: Mur
 | SOUS-SOL | 0050HMu1612655862 | 5 | 0050Mu_1612655863 | m³ | AllplanAttributes - Object Layer Attributes #2, Catégorie de transformation: Nouvelle construction; Object Layer Attributes #2, Métier: Maçonnerie; Object Layer Attributes #2, Matériau: Béton; Object Layer Attributes #2, structure_porteur: no; Object Layer Attributes #2, Id_élt_Allmétré: 0050Mu_1612771690; Object Layer Attributes #2, Unité: m²; Object Layer Attributes #2, Nom_de_macro: Mur; Object Layer Attributes #3, Catégorie de transformation: Nouvelle construction; Object Layer Attributes #3, Métier: Maçonnerie; Object Layer Attributes #3, Matériau: Béton; Object Layer Attributes #3, structure_porteur: no; Object Layer Attributes #3, Id_élt_Allmétré: 0050Mu_1612771691; Object Layer Attributes #3, Unité: m²; Object Layer Attributes #3, Nom_de_macro: Mur
 | RDC | 0100HMu0000009355 | 5 | 0100Mu_0000009361 | m³
 | RDC | 0100HMu0000007588 | 5 | 0100Mu_0000007589 | m³
 | RDC | 0100HMu0000010326 | 5 | 0100Mu_0000010327 | m³
 | RDC | 0100HMu0000010413 | 5 | 0100Mu_0000010414 | m³

# IfcWallStandardCase (245)
AllplanAttributes - Unité: m³; Nom_de_macro: Mur entier; Object Layer Attributes #1, Catégorie de transformation: Nouvelle construction; Object Layer Attributes #1, Métier: Maçonnerie; Object Layer Attributes #1, Nom_de_macro: Mur
Name | In | Material | Id_élt_Allmétré | Object Layer Attributes #1, structure_porteur | Object Layer Attributes #1, RATIO_HA | Object Layer Attributes #1, Id_élt_Allmétré | Object Layer Attributes #1, Unité | Object Layer Attributes #1, Matériau
 | FONDATIONS | Béton 0.25 m | 0010HMu1612668647 | no | 5 | 0010Mu_1612668648 | m³ | Béton
 | FONDATIONS | Béton 0.25 m | 0010HMu1612668671 | no | 5 | 0010Mu_1612668672 | m³ | Béton
 | FONDATIONS | Béton 0.25 m | 0010HMu1612673772 | no | 5 | 0010Mu_1612673782 | m³ | Béton
 | FONDATIONS | Béton 0.25 m | 0010HMu1612673776 | no | 5 | 0010Mu_1612673783 | m³ | Béton
 | FONDATIONS | Béton 0.25 m | 0010HMu1612673778 | no | 5 | 0010Mu_1612673784 | m³ | Béton
 | FONDATIONS | Béton 0.25 m | 0010HMu1612675904 | no | 5 | 0010Mu_1612675905 | m³ | Béton
 | FONDATIONS | Béton 0.25 m | 0010HMu1612675987 | no | 5 | 0010Mu_1612675996 | m³ | Béton
 | FONDATIONS | Béton 0.25 m | 0010HMu1612675989 | no | 5 | 0010Mu_1612675999 | m³ | Béton
 | FONDATIONS | Béton 0.2 m | 0010HMu1612676271 | no | 5 | 0010Mu_1612676289 | m³ | Béton
 | FONDATIONS | Béton 0.25 m | 0010HMu1612668659 | no | 5 | 0010Mu_1612668660 | m³ | Béton
 | FONDATIONS | Béton 0.25 m | 0010HMu1612668640 | no | 5 | 0010Mu_1612668641 | m³ | Béton
 | FONDATIONS | Béton 0.25 m | 0010HMu1612675914 | no | 5 | 0010Mu_1612675915 | m³ | Béton
 | FONDATIONS | Béton 0.2 m | 0010HMu1612676270 | no | 5 | 0010Mu_1612676292 | m³ | Béton
 | FONDATIONS | Béton 0.25 m | 0010HMu1612709075 | no | 5 | 0010Mu_1612709082 | m³ | Béton
 | FONDATIONS | Béton 0.25 m | 0010HMu1612709093 | no | 5 | 0010Mu_1612709094 | m³ | Béton
 | FONDATIONS | Béton 0.25 m | 0010HMu1612709090 | no | 5 | 0010Mu_1612709092 | m³ | Béton
 | FONDATIONS | Béton 0.25 m | 0010HMu1612709077 | no | 5 | 0010Mu_1612709083 | m³ | Béton
 | FONDATIONS | Béton 0.25 m | 0010HMu1612709428 | no | 5 | 0010Mu_1612709445 | m³ | Béton
 | FONDATIONS | Béton 0.25 m | 0010HMu1612709424 | no | 5 | 0010Mu_1612709442 | m³ | Béton
 | FONDATIONS | Béton 0.25 m | 0010HMu1612709431 | no | 5 | 0010Mu_1612709444 | m³ | Béton
 | FONDATIONS | Béton 0.25 m | 0010HMu1612709558 | no | 5 | 0010Mu_1612709560 | m³ | Béton
 | FONDATIONS | Béton 0.2 m | 0010HMu1612709427 | no | 5 | 0010Mu_1612709446 | m³ | Béton
 | FONDATIONS | Béton 0.25 m | 0010HMu1612709621 | no | 5 | 0010Mu_1612709646 | m³ | Béton
 | FONDATIONS | Béton 0.25 m | 0010HMu1612709628 | no | 5 | 0010Mu_1612709642 | m³ | Béton
 | FONDATIONS | Béton 0.25 m | 0010HMu1612709632 | no | 5 | 0010Mu_1612709639 | m³ | Béton
 | FONDATIONS | Béton 0.25 m | 0010HMu1612709634 | no | 5 | 0010Mu_1612709643 | m³ | Béton
 | FONDATIONS | Béton 0.2 m | 0010HMu1612709636 | no | 5 | 0010Mu_1612709641 | m³ | Béton
 | FONDATIONS | Béton 0.25 m | 0010HMu1612709821 | no | 5 | 0010Mu_1612709838 | m³ | Béton
 | FONDATIONS | Béton 0.25 m | 0010HMu1612709824 | no | 5 | 0010Mu_1612709835 | m³ | Béton
 | FONDATIONS | Béton 0.25 m | 0010HMu1612709825 | no | 5 | 0010Mu_1612709836 | m³ | Béton
 | FONDATIONS | Béton 0.25 m | 0010HMu1612709828 | no | 5 | 0010Mu_1612709837 | m³ | Béton
 | FONDATIONS | Béton 0.25 m | 0010HMu1612709854 | no | 5 | 0010Mu_1612709871 | m³ | Béton
 | FONDATIONS | Béton 0.25 m | 0010HMu1612709857 | no | 5 | 0010Mu_1612709868 | m³ | Béton
 | FONDATIONS | Béton 0.25 m | 0010HMu1612709858 | no | 5 | 0010Mu_1612709869 | m³ | Béton
 | FONDATIONS | Béton 0.25 m | 0010HMu1612709861 | no | 5 | 0010Mu_1612709870 | m³ | Béton
 | FONDATIONS | Béton 0.25 m | 0010HMu1612709887 | no | 5 | 0010Mu_1612709903 | m³ | Béton
 | FONDATIONS | Béton 0.25 m | 0010HMu1612709890 | no | 5 | 0010Mu_1612709906 | m³ | Béton
 | FONDATIONS | Béton 0.25 m | 0010HMu1612709891 | no | 5 | 0010Mu_1612709905 | m³ | Béton
 | FONDATIONS | Béton 0.25 m | 0010HMu1612709894 | no | 5 | 0010Mu_1612709904 | m³ | Béton
 | FONDATIONS | Béton 0.25 m | 0010HMu1612709920 | no | 5 | 0010Mu_1612709937 | m³ | Béton
 | FONDATIONS | Béton 0.25 m | 0010HMu1612709923 | no | 5 | 0010Mu_1612709934 | m³ | Béton
 | FONDATIONS | Béton 0.25 m | 0010HMu1612709924 | no | 5 | 0010Mu_1612709935 | m³ | Béton
 | FONDATIONS | Béton 0.25 m | 0010HMu1612709927 | no | 5 | 0010Mu_1612709936 | m³ | Béton
 | FONDATIONS | Béton 0.25 m | 0010HMu1612709958 | no | 5 | 0010Mu_1612709971 | m³ | Béton
 | FONDATIONS | Béton 0.25 m | 0010HMu1612709961 | no | 5 | 0010Mu_1612709974 | m³ | Béton
 | FONDATIONS | Béton 0.25 m | 0010HMu1612709962 | no | 5 | 0010Mu_1612709973 | m³ | Béton
 | FONDATIONS | Béton 0.25 m | 0010HMu1612709965 | no | 5 | 0010Mu_1612709972 | m³ | Béton
 | FONDATIONS | Béton 0.25 m | 0010HMu1612709383 | no | 5 | 0010Mu_1612709404 | m³ | Béton
 | FONDATIONS | Béton 0.25 m | 0010HMu1612709386 | no | 5 | 0010Mu_1612709401 | m³ | Béton
 | FONDATIONS | Béton 0.25 m | 0010HMu1612709387 | no | 5 | 0010Mu_1612709402 | m³ | Béton
 | FONDATIONS | Béton 0.25 m | 0010HMu1612709390 | no | 5 | 0010Mu_1612709403 | m³ | Béton
 | FONDATIONS | Béton 0.25 m | 0010HMu1612710307 | no | 5 | 0010Mu_1612710321 | m³ | Béton
 | FONDATIONS | Béton 0.25 m | 0010HMu1612710310 | no | 5 | 0010Mu_1612710322 | m³ | Béton
 | FONDATIONS | Béton 0.25 m | 0010HMu1612710311 | no | 5 | 0010Mu_1612710324 | m³ | Béton
 | FONDATIONS | Béton 0.25 m | 0010HMu1612710314 | no | 5 | 0010Mu_1612710323 | m³ | Béton
 | FONDATIONS | Béton 0.25 m | 0010HMu1612675899 | no | 5 | 0010Mu_1612675900 | m³ | Béton
 | FONDATIONS | Béton 0.25 m | 0010HMu1612675970 | no | 5 | 0010Mu_1612675971 | m³ | Béton
 | FONDATIONS | Béton 0.25 m | 0010HMu1612675919 | no | 5 | 0010Mu_1612675920 | m³ | Béton
 | FONDATIONS | Béton 0.25 m | 0010HMu1612675985 | no | 5 | 0010Mu_1612675998 | m³ | Béton
 | FONDATIONS | Béton 0.25 m | 0010HMu1612675994 | no | 5 | 0010Mu_1612675997 | m³ | Béton
 | FONDATIONS | Béton 0.25 m | 0010HMu1612675991 | no | 5 | 0010Mu_1612675993 | m³ | Béton
 | FONDATIONS | Béton 0.25 m | 0010HMu1612673774 | no | 5 | 0010Mu_1612673785 | m³ | Béton
 | FONDATIONS | Béton 0.25 m | 0010HMu1612720665 | no | 5 | 0010Mu_1612720675 | m³ | Béton
 | FONDATIONS | Béton 0.25 m | 0010HMu1612720669 | no | 5 | 0010Mu_1612720677 | m³ | Béton
 | FONDATIONS | Béton 0.25 m | 0010HMu1612720666 | no | 5 | 0010Mu_1612720676 | m³ | Béton
 | FONDATIONS | Béton 0.25 m | 0010HMu1612720662 | no | 5 | 0010Mu_1612720678 | m³ | Béton
 | FONDATIONS | Béton 0.25 m | 0010HMu1612720858 | no | 5 | 0010Mu_1612720865 | m³ | Béton
 | FONDATIONS | Béton 0.25 m | 0010HMu1612720855 | no | 5 | 0010Mu_1612720864 | m³ | Béton
 | FONDATIONS | Béton 0.25 m | 0010HMu1612720851 | no | 5 | 0010Mu_1612720866 | m³ | Béton
 | FONDATIONS | Béton 0.25 m | 0010HMu1612720854 | no | 5 | 0010Mu_1612720863 | m³ | Béton
 | SOUS-SOL | Béton 0.2 m | 0050HMu1612658450 | no | 5 | 0050Mu_1612658451 | m³ | Béton
 | SOUS-SOL | Béton 0.2 m | 0050HMu1612658455 | no | 5 | 0050Mu_1612658456 | m³ | Béton
 | SOUS-SOL | Béton 0.2 m | 0050HMu1612658465 | no | 5 | 0050Mu_1612658466 | m³ | Béton
 | SOUS-SOL | Béton 0.05 m, Béton 0.2 m | 0050HMu1612648499 | no |  | 0050Mu_1612648501 | m² | Béton | AllplanAttributes - Object Layer Attributes #2, Catégorie de transformation: Nouvelle construction; Object Layer Attributes #2, Métier: Maçonnerie; Object Layer Attributes #2, Matériau: Béton; Object Layer Attributes #2, structure_porteur: no; Object Layer Attributes #2, RATIO_HA: 5; Object Layer Attributes #2, Id_élt_Allmétré: 0050Mu_1612648635; Object Layer Attributes #2, Unité: m³; Object Layer Attributes #2, Nom_de_macro: Mur
 | SOUS-SOL | Béton 0.25 m | 0050HMu1612647292 | no | 5 | 0050Mu_1612647293 | m³ | Béton
 | SOUS-SOL | Béton 0.25 m | 0050HMu1612653319 | no | 5 | 0050Mu_1612653320 | m³ | Béton
 | SOUS-SOL | Béton 0.25 m | 0050HMu1612650077 | no | 5 | 0050Mu_1612650078 | m³ | Béton
 | SOUS-SOL | Béton 0.3 m | 0050HMu1612659236 | no | 5 | 0050Mu_1612659238 | m³ | Béton
 | SOUS-SOL | Béton 0.2 m | 0050HMu1612697500 | no | 5 | 0050Mu_1612697547 | m³ | Béton
 | SOUS-SOL | Béton 0.25 m | 0050HMu1612647303 | no | 5 | 0050Mu_1612647304 | m³ | Béton
 | SOUS-SOL | Béton 0.25 m | 0050HMu1612647281 | no | 5 | 0050Mu_1612647282 | m³ | Béton
 | SOUS-SOL | Béton 0.25 m | 0050HMu1612650200 | no | 5 | 0050Mu_1612650201 | m³ | Béton
 | SOUS-SOL | Béton 0.2 m | 0050HMu1612647212 | no | 5 | 0050Mu_1612647213 | m³ | Béton
 | SOUS-SOL | Béton 0.2 m | 0050HMu1612647251 | no | 5 | 0050Mu_1612647252 | m³ | Béton
 | SOUS-SOL | Béton 0.2 m | 0050HMu1612647217 | no | 5 | 0050Mu_1612647218 | m³ | Béton
 | SOUS-SOL | Béton 0.2 m | 0050HMu1612647228 | no | 5 | 0050Mu_1612647229 | m³ | Béton
 | SOUS-SOL | Béton 0.2 m | 0050HMu1612647404 | no | 5 | 0050Mu_1612647405 | m³ | Béton
 | SOUS-SOL | Béton 0.2 m | 0050HMu1612658803 | no | 5 | 0050Mu_1612658804 | m³ | Béton
 | SOUS-SOL | Béton 0.2 m | 0050HMu1612658798 | no | 5 | 0050Mu_1612658799 | m³ | Béton
 | SOUS-SOL | Béton 0.2 m | 0050HMu1612647412 | no | 5 | 0050Mu_1612647413 | m³ | Béton
 | SOUS-SOL | Béton 0.2 m | 0050HMu1612647422 | no | 5 | 0050Mu_1612647423 | m³ | Béton
 | SOUS-SOL | Béton 0.2 m | 0050HMu1612647466 | no | 5 | 0050Mu_1612647467 | m³ | Béton
 | SOUS-SOL | Béton 0.2 m | 0050HMu1612647450 | no | 5 | 0050Mu_1612647451 | m³ | Béton
 | SOUS-SOL | Béton 0.2 m | 0050HMu1612647433 | no | 5 | 0050Mu_1612647434 | m³ | Béton
 | SOUS-SOL | Béton 0.2 m | 0050HMu1612717590 | no | 5 | 0050Mu_1612717642 | m³ | Béton
 | SOUS-SOL | Béton 0.2 m | 0050HMu1612649119 | no | 5 | 0050Mu_1612649120 | m³ | Béton
 | SOUS-SOL | Béton 0.2 m | 0050HMu1612649131 | no | 5 | 0050Mu_1612649132 | m³ | Béton
 | SOUS-SOL | Béton 0.2 m | 0050HMu1612658874 | no | 5 | 0050Mu_1612658876 | m³ | Béton
 | SOUS-SOL | Béton 0.2 m | 0050HMu1612658867 | no | 5 | 0050Mu_1612658869 | m³ | Béton
 | SOUS-SOL | Béton 0.2 m | 0050HMu1612658860 | no | 5 | 0050Mu_1612658862 | m³ | Béton
 | SOUS-SOL | Béton 0.2 m | 0050HMu1612658825 | no | 5 | 0050Mu_1612658826 | m³ | Béton
 | SOUS-SOL | Béton 0.2 m | 0050HMu1612647481 | no | 5 | 0050Mu_1612647482 | m³ | Béton
 | SOUS-SOL | Béton 0.2 m | 0050HMu1612669295 | no | 5 | 0050Mu_1612669297 | m³ | Béton
 | SOUS-SOL | Béton 0.3 m | 0050HMu1612696299 | no | 5 | 0050Mu_1612696301 | m³ | Béton
 | SOUS-SOL | Béton 0.3 m | 0050HMu1612659165 | no | 5 | 0050Mu_1612659166 | m³ | Béton
 | SOUS-SOL | Béton 0.3 m | 0050HMu1612649596 | no | 5 | 0050Mu_1612649599 | m³ | Béton
 | SOUS-SOL | Béton 0.2 m | 0050HMu1612659156 | no | 5 | 0050Mu_1612659158 | m³ | Béton
 | SOUS-SOL | Béton 0.2 m | 0050HMu1612718668 | no | 5 | 0050Mu_1612718728 | m³ | Béton
 | SOUS-SOL | Béton 0.2 m | 0050HMu1612650139 | no | 5 | 0050Mu_1612650140 | m³ | Béton
 | SOUS-SOL | Béton 0.2 m | 0050HMu1612650149 | no | 5 | 0050Mu_1612650150 | m³ | Béton
 | SOUS-SOL | Béton 0.199999 m | 0050HMu1612660525 | no | 5 | 0050Mu_1612660529 | m³ | Béton
 | SOUS-SOL | Béton 0.2 m | 0050HMu1612650724 | no | 5 | 0050Mu_1612650725 | m³ | Béton
 | SOUS-SOL | Béton 0.2 m | 0050HMu1612650733 | no | 5 | 0050Mu_1612650734 | m³ | Béton
 | SOUS-SOL | Béton 0.2 m | 0050HMu1612651269 | no | 5 | 0050Mu_1612651272 | m³ | Béton
 | SOUS-SOL | Béton 0.2 m | 0050HMu1612668951 | no | 5 | 0050Mu_1612668953 | m³ | Béton
 | SOUS-SOL | Béton 0.2 m | 0050HMu1612651730 | no | 5 | 0050Mu_1612651731 | m³ | Béton
 | SOUS-SOL | Béton 0.2 m | 0050HMu1612651745 | no | 5 | 0050Mu_1612651746 | m³ | Béton
 | SOUS-SOL | Béton 0.2 m | 0050HMu1612651757 | no | 5 | 0050Mu_1612651758 | m³ | Béton
 | SOUS-SOL | Béton 0.2 m | 0050HMu1612651852 | no | 5 | 0050Mu_1612651853 | m³ | Béton
 | SOUS-SOL | Béton 0.2 m | 0050HMu1612651865 | no | 5 | 0050Mu_1612651866 | m³ | Béton
 | SOUS-SOL | Béton 0.2 m | 0050HMu1612651877 | no | 5 | 0050Mu_1612651878 | m³ | Béton
 | SOUS-SOL | Béton 0.2 m | 0050HMu1612658308 | no | 5 | 0050Mu_1612658309 | m³ | Béton
 | SOUS-SOL | Béton 0.2 m | 0050HMu1612653736 | no | 5 | 0050Mu_1612653737 | m³ | Béton
 | SOUS-SOL | Béton 0.2 m | 0050HMu1612653474 | no | 5 | 0050Mu_1612653477 | m³ | Béton
 | SOUS-SOL | Béton 0.2 m | 0050HMu1612658170 | no | 5 | 0050Mu_1612658172 | m³ | Béton
 | SOUS-SOL | Béton 0.2 m | 0050HMu1612658191 | no | 5 | 0050Mu_1612658193 | m³ | Béton
 | SOUS-SOL | Béton 0.2 m | 0050HMu1612658200 | no | 5 | 0050Mu_1612658202 | m³ | Béton
 | SOUS-SOL | Béton 0.2 m | 0050HMu1612658209 | no | 5 | 0050Mu_1612658211 | m³ | Béton
 | SOUS-SOL | Béton 0.2 m | 0050HMu1612653657 | no | 5 | 0050Mu_1612653658 | m³ | Béton
 | SOUS-SOL | Béton 0.2 m | 0050HMu1612653565 | no | 5 | 0050Mu_1612653566 | m³ | Béton
 | SOUS-SOL | Béton 0.2 m | 0050HMu1612722616 | no | 5 | 0050Mu_1612722621 | m³ | Béton
 | SOUS-SOL | Béton 0.199992 m | 0050HMu1612654184 | no | 5 | 0050Mu_1612654185 | m³ | Béton
 | SOUS-SOL | Béton 0.2 m | 0050HMu1612654557 | no | 5 | 0050Mu_1612654558 | m³ | Béton
 | SOUS-SOL | Béton 0.2 m | 0050HMu1612647537 | no | 5 | 0050Mu_1612647538 | m³ | Béton
 | SOUS-SOL | Mur_Maconnerie 0.2 m | 0050HMu1612661377 | no | 5 | 0050Mu_1612661378 | m³ | Mur_Maconnerie
 | SOUS-SOL | Béton 0.2 m | 0050HMu1612660668 | no | 5 | 0050Mu_1612660670 | m³ | Béton
 | SOUS-SOL | Béton 0.2 m | 0050HMu1612658956 | no | 5 | 0050Mu_1612658957 | m³ | Béton
 | SOUS-SOL | Béton 0.2 m | 0050HMu1612658946 | no | 5 | 0050Mu_1612658947 | m³ | Béton
 | SOUS-SOL | Béton 0.2 m | 0050HMu1612658934 | no | 5 | 0050Mu_1612658935 | m³ | Béton
 | SOUS-SOL | Béton 0.2 m | 0050HMu1612659038 | no | 5 | 0050Mu_1612659039 | m³ | Béton
 | SOUS-SOL | Béton 0.2 m | 0050HMu1612659089 | no | 5 | 0050Mu_1612659090 | m³ | Béton
 | SOUS-SOL | Béton 0.2 m | 0050HMu1612659120 | no | 5 | 0050Mu_1612659122 | m³ | Béton
 | SOUS-SOL | Béton 0.2 m | 0050HMu1612730646 | no | 5 | 0050Mu_1612730647 | m³ | Béton
 | SOUS-SOL | Béton 0.199998 m | 0050HMu1612647503 | no | 5 | 0050Mu_1612647504 | m³ | Béton
 | SOUS-SOL | Mur_Maconnerie 0.15 m | 0050HMu1612688142 | no | 5 | 0050Mu_1612688143 | m³ | Mur_Maconnerie
 | SOUS-SOL | Mur_Maconnerie 0.15 m | 0050HMu1612688148 | no | 5 | 0050Mu_1612688149 | m³ | Mur_Maconnerie
 | SOUS-SOL | Béton 0.25 m | 0050HMu1612649611 | no | 5 | 0050Mu_1612649613 | m³ | Béton
 | SOUS-SOL | Béton 0.25 m | 0050HMu1612653334 | no | 5 | 0050Mu_1612653335 | m³ | Béton
 | SOUS-SOL | Béton 0.2 m | 0050HMu1612739736 | no | 5 | 0050Mu_1612739737 | m³ | Béton
 | SOUS-SOL | Béton 0.25 m | 0050HMu1612660560 | no | 5 | 0050Mu_1612660563 | m³ | Béton
 | SOUS-SOL | Béton 0.25 m | 0050HMu1612653283 | no | 5 | 0050Mu_1612653285 | m³ | Béton
 | SOUS-SOL | Béton 0.2 m | 0050HMu1612653271 | no | 5 | 0050Mu_1612653273 | m³ | Béton
 | SOUS-SOL | Béton 0.3 m | 0050HMu1612659187 | no | 5 | 0050Mu_1612659189 | m³ | Béton
 | SOUS-SOL | Béton 0.3 m | 0050HMu1612696283 | no | 5 | 0050Mu_1612696285 | m³ | Béton
 | SOUS-SOL | Béton 0.2 m | 0050HMu1612658151 | no | 5 | 0050Mu_1612658153 | m³ | Béton
 | SOUS-SOL | Béton 0.2 m | 0050HMu1612657956 | no | 5 | 0050Mu_1612657958 | m³ | Béton
 | SOUS-SOL | Béton 0.2 m, Béton 0.19 m, Béton 0.11 m | 0050HMu1612655869 | no | 5 | 0050Mu_1612655870 | m³ | Béton | AllplanAttributes - Object Layer Attributes #2, Catégorie de transformation: Nouvelle construction; Object Layer Attributes #2, Métier: Maçonnerie; Object Layer Attributes #2, Matériau: Béton; Object Layer Attributes #2, structure_porteur: no; Object Layer Attributes #2, Id_élt_Allmétré: 0050Mu_1612769760; Object Layer Attributes #2, Unité: m²; Object Layer Attributes #2, Nom_de_macro: Mur; Object Layer Attributes #3, Catégorie de transformation: Nouvelle construction; Object Layer Attributes #3, Métier: Maçonnerie; Object Layer Attributes #3, Matériau: Béton; Object Layer Attributes #3, structure_porteur: no; Object Layer Attributes #3, Id_élt_Allmétré: 0050Mu_1612769761; Object Layer Attributes #3, Unité: m²; Object Layer Attributes #3, Nom_de_macro: Mur
 | SOUS-SOL | Béton 0.11 m, Béton 0.19 m, Béton 0.2 m | 0050HMu1612772212 | no | 5 | 0050Mu_1612772213 | m³ | Béton | AllplanAttributes - Object Layer Attributes #2, Catégorie de transformation: Nouvelle construction; Object Layer Attributes #2, Métier: Maçonnerie; Object Layer Attributes #2, Matériau: Béton; Object Layer Attributes #2, structure_porteur: no; Object Layer Attributes #2, Id_élt_Allmétré: 0050Mu_1612772254; Object Layer Attributes #2, Unité: m²; Object Layer Attributes #2, Nom_de_macro: Mur; Object Layer Attributes #3, Catégorie de transformation: Nouvelle construction; Object Layer Attributes #3, Métier: Maçonnerie; Object Layer Attributes #3, Matériau: Béton; Object Layer Attributes #3, structure_porteur: no; Object Layer Attributes #3, Id_élt_Allmétré: 0050Mu_1612772255; Object Layer Attributes #3, Unité: m²; Object Layer Attributes #3, Nom_de_macro: Mur
 | SOUS-SOL | Béton 0.2 m, Béton 0.19 m, Béton 0.11 m | 0050HMu1612655683 | no |  | 0050Mu_1612655684 | m² | Béton | AllplanAttributes - Object Layer Attributes #2, Catégorie de transformation: Nouvelle construction; Object Layer Attributes #2, Métier: Maçonnerie; Object Layer Attributes #2, Matériau: Béton; Object Layer Attributes #2, structure_porteur: no; Object Layer Attributes #2, Id_élt_Allmétré: 0050Mu_1612772595; Object Layer Attributes #2, Unité: m²; Object Layer Attributes #2, Nom_de_macro: Mur; Object Layer Attributes #3, Catégorie de transformation: Nouvelle construction; Object Layer Attributes #3, Métier: Maçonnerie; Object Layer Attributes #3, Matériau: Béton; Object Layer Attributes #3, structure_porteur: no; Object Layer Attributes #3, Id_élt_Allmétré: 0050Mu_1612772596; Object Layer Attributes #3, Unité: m³; Object Layer Attributes #3, Nom_de_macro: Mur; Object Layer Attributes #3, RATIO_HA: 5
 | SOUS-SOL | Béton 0.2 m | 0050HMu1612647169 | no | 5 | 0050Mu_1612647170 | m³ | Béton
 | SOUS-SOL | Béton 0.2 m | 0050HMu1612647176 | no | 5 | 0050Mu_1612647177 | m³ | Béton
 | SOUS-SOL | Béton 0.2 m | 0050HMu1612647186 | no | 5 | 0050Mu_1612647187 | m³ | Béton
 | SOUS-SOL | Béton 0.2 m | 0050HMu1612668694 | no | 5 | 0050Mu_1612668696 | m³ | Béton
 | SOUS-SOL | Béton 0.2 m | 0050HMu1612647200 | no | 5 | 0050Mu_1612647201 | m³ | Béton
 | SOUS-SOL | Béton 0.2 m | 0050HMu1612654690 | no | 5 | 0050Mu_1612654693 | m³ | Béton
 | SOUS-SOL | Béton 0.2 m, Béton 0.31 m, Béton 0.11 m | 0050HMu1612657071 | no | 5 | 0050Mu_1612657072 | m³ | Béton | AllplanAttributes - Object Layer Attributes #2, Catégorie de transformation: Nouvelle construction; Object Layer Attributes #2, Métier: Maçonnerie; Object Layer Attributes #2, Matériau: Béton; Object Layer Attributes #2, structure_porteur: no; Object Layer Attributes #2, Id_élt_Allmétré: 0050Mu_1612784176; Object Layer Attributes #2, Unité: m³; Object Layer Attributes #2, Nom_de_macro: Mur; Object Layer Attributes #3, Catégorie de transformation: Nouvelle construction; Object Layer Attributes #3, Métier: Maçonnerie; Object Layer Attributes #3, Matériau: Béton; Object Layer Attributes #3, structure_porteur: no; Object Layer Attributes #3, Id_élt_Allmétré: 0050Mu_1612784177; Object Layer Attributes #3, Unité: m³; Object Layer Attributes #3, Nom_de_macro: Mur
 | SOUS-SOL | Béton 0.2 m, Béton 0.19 m, Béton 0.11 m | 0050HMu1612657044 | no | 5 | 0050Mu_1612657045 | m³ | Béton | AllplanAttributes - Object Layer Attributes #2, Catégorie de transformation: Nouvelle construction; Object Layer Attributes #2, Métier: Maçonnerie; Object Layer Attributes #2, Matériau: Béton; Object Layer Attributes #2, structure_porteur: no; Object Layer Attributes #2, Id_élt_Allmétré: 0050Mu_1612784293; Object Layer Attributes #2, Unité: m²; Object Layer Attributes #2, Nom_de_macro: Mur; Object Layer Attributes #3, Catégorie de transformation: Nouvelle construction; Object Layer Attributes #3, Métier: Maçonnerie; Object Layer Attributes #3, Matériau: Béton; Object Layer Attributes #3, structure_porteur: no; Object Layer Attributes #3, Id_élt_Allmétré: 0050Mu_1612784294; Object Layer Attributes #3, Unité: m²; Object Layer Attributes #3, Nom_de_macro: Mur
 | SOUS-SOL | Béton 0.2 m, Béton 0.19 m, Béton 0.11 m | 0050HMu1612657059 | no | 5 | 0050Mu_1612657060 | m³ | Béton | AllplanAttributes - Object Layer Attributes #2, Catégorie de transformation: Nouvelle construction; Object Layer Attributes #2, Métier: Maçonnerie; Object Layer Attributes #2, Matériau: Béton; Object Layer Attributes #2, structure_porteur: no; Object Layer Attributes #2, Id_élt_Allmétré: 0050Mu_1612784393; Object Layer Attributes #2, Unité: m²; Object Layer Attributes #2, Nom_de_macro: Mur; Object Layer Attributes #3, Catégorie de transformation: Nouvelle construction; Object Layer Attributes #3, Métier: Maçonnerie; Object Layer Attributes #3, Matériau: Béton; Object Layer Attributes #3, structure_porteur: no; Object Layer Attributes #3, Id_élt_Allmétré: 0050Mu_1612784394; Object Layer Attributes #3, Unité: m²; Object Layer Attributes #3, Nom_de_macro: Mur
 | SOUS-SOL | Béton 0.2 m, Béton 0.31 m, Béton 0.11 m | 0050HMu1612657049 | no | 5 | 0050Mu_1612657050 | m³ | Béton | AllplanAttributes - Object Layer Attributes #2, Catégorie de transformation: Nouvelle construction; Object Layer Attributes #2, Métier: Maçonnerie; Object Layer Attributes #2, Matériau: Béton; Object Layer Attributes #2, structure_porteur: no; Object Layer Attributes #2, Id_élt_Allmétré: 0050Mu_1612786821; Object Layer Attributes #2, Unité: m³; Object Layer Attributes #2, Nom_de_macro: Mur; Object Layer Attributes #3, Catégorie de transformation: Nouvelle construction; Object Layer Attributes #3, Métier: Maçonnerie; Object Layer Attributes #3, Matériau: Béton; Object Layer Attributes #3, structure_porteur: no; Object Layer Attributes #3, Id_élt_Allmétré: 0050Mu_1612786822; Object Layer Attributes #3, Unité: m³; Object Layer Attributes #3, Nom_de_macro: Mur
 | SOUS-SOL | Béton 0.25 m | 0050HMu1612653345 | no | 5 | 0050Mu_1612653346 | m³ | Béton
 | SOUS-SOL | Béton 0.25 m | 0050HMu1612653464 | no | 5 | 0050Mu_1612653467 | m³ | Béton
 | SOUS-SOL | Béton 0.25 m | 0050HMu1612653453 | no | 5 | 0050Mu_1612653456 | m³ | Béton
 | SOUS-SOL | Béton 0.25 m | 0050HMu1612653398 | no | 5 | 0050Mu_1612653400 | m³ | Béton
 | SOUS-SOL | Béton 0.2 m, Béton 0.19 m, Béton 0.11 m | 0050HMu1612774328 | no | 5 | 0050Mu_1612774329 | m³ | Béton | AllplanAttributes - Object Layer Attributes #2, Catégorie de transformation: Nouvelle construction; Object Layer Attributes #2, Métier: Maçonnerie; Object Layer Attributes #2, Matériau: Béton; Object Layer Attributes #2, structure_porteur: no; Object Layer Attributes #2, Id_élt_Allmétré: 0050Mu_1612774330; Object Layer Attributes #2, Unité: m²; Object Layer Attributes #2, Nom_de_macro: Mur; Object Layer Attributes #3, Catégorie de transformation: Nouvelle construction; Object Layer Attributes #3, Métier: Maçonnerie; Object Layer Attributes #3, Matériau: Béton; Object Layer Attributes #3, structure_porteur: no; Object Layer Attributes #3, Id_élt_Allmétré: 0050Mu_1612774331; Object Layer Attributes #3, Unité: m²; Object Layer Attributes #3, Nom_de_macro: Mur
 | SOUS-SOL | Béton 0.2 m | 0050HMu1612659312 | no | 5 | 0050Mu_1612659314 | m³ | Béton
 | SOUS-SOL | Mur_Maconnerie 0.15 m | 0050HMu1612647796 | no | 5 | 0050Mu_1612647797 | m³ | Mur_Maconnerie
 | SOUS-SOL | Mur_Maconnerie 0.15 m | 0050HMu1612647786 | no | 5 | 0050Mu_1612647787 | m³ | Mur_Maconnerie
 | SOUS-SOL | Béton 0.2 m | 0050HMu1612651888 | no | 5 | 0050Mu_1612651889 | m³ | Béton
 | SOUS-SOL | Béton 0.2 m | 0050HMu1612657993 | no | 5 | 0050Mu_1612657995 | m³ | Béton
 | SOUS-SOL | Béton 0.2 m | 0050HMu1612658149 | no | 5 | 0050Mu_1612658154 | m³ | Béton
 | SOUS-SOL | Béton 0.2 m | 0050HMu1613203974 | no | 5 | 0050Mu_1613203989 | m³ | Béton
 | SOUS-SOL | Béton 0.199973 m | 0050HMu1612653241 | no | 5 | 0050Mu_1612653243 | m³ | Béton
 | SOUS-SOL | Béton 0.2 m | 0050HMu1612653624 | no | 5 | 0050Mu_1612653626 | m³ | Béton
 | RDC | Béton 0.2 m | 0100HMu0000010060 | no | 5 | 0100Mu_0000010061 | m³ | Béton
 | RDC | Béton 0.2 m | 0100HMu0000010139 | no | 5 | 0100Mu_0000010159 | m³ | Béton
 | RDC | Mur_Maconnerie 0.15 m | 0100HMu0000017750 |  | 5 | 0100Mu_0000017751 | m³ | Mur_Maconnerie
 | RDC | Mur_Maconnerie 0.15 m | 0100HMu0000017767 |  | 5 | 0100Mu_0000017768 | m³ | Mur_Maconnerie
 | RDC | Mur_Maconnerie 0.15 m | 0100HMu0000017736 |  | 5 | 0100Mu_0000017737 | m³ | Mur_Maconnerie
 | RDC | Béton 0.2 m | 0100HMu0000018057 |  | 5 | 0100Mu_0000018058 | m³ | Béton
 | RDC | Béton 0.2 m | 0100HMu0000018062 |  | 5 | 0100Mu_0000018063 | m³ | Béton
 | RDC | Béton 0.2 m | 0100HMu0000018067 |  | 5 | 0100Mu_0000018068 | m³ | Béton
 | RDC | Béton 0.2 m | 0100HMu0000018115 |  | 5 | 0100Mu_0000018116 | m³ | Béton
 | RDC | Béton 0.199998 m | 0100HMu0000007593 | no | 5 | 0100Mu_0000007594 | m³ | Béton
 | RDC | Béton 0.2 m | 0100HMu0000009140 | no | 5 | 0100Mu_0000009141 | m³ | Béton
 | RDC | Béton 0.2 m | 0100HMu0000009294 | no | 5 | 0100Mu_0000009295 | m³ | Béton
 | RDC | Béton 0.2 m | 0100HMu0000016169 | no | 5 | 0100Mu_0000016171 | m³ | Béton
 | RDC | Béton 0.2 m | 0100HMu0000009950 | no | 5 | 0100Mu_0000009951 | m³ | Béton
 | RDC | Béton 0.2 m | 0100HMu0000019852 | no | 5 | 0100Mu_0000019855 | m³ | Béton
 | RDC | Béton 0.2 m | 0100HMu0000017617 | no | 5 | 0100Mu_0000017618 | m³ | Béton
 | RDC | Béton 0.2 m | 0100HMu0000012872 | no | 5 | 0100Mu_0000012874 | m³ | Béton
 | RDC | Mur_Maconnerie 0.15 m | 0100HMu0000017922 |  | 5 | 0100Mu_0000017923 | m³ | Mur_Maconnerie
 | RDC | Béton 0.2 m | 0100HMu0000012957 | no | 5 | 0100Mu_0000012958 | m³ | Béton
 | RDC | Béton 0.2 m | 0100HMu0000010310 | no | 5 | 0100Mu_0000010311 | m³ | Béton
 | RDC | Mur_Maconnerie 0.2 m | 0100HMu0000017784 | no | 5 | 0100Mu_0000017785 | m³ | Mur_Maconnerie
 | RDC | Mur_Maconnerie 0.15 m | 0100HMu0000017801 |  | 5 | 0100Mu_0000017802 | m³ | Mur_Maconnerie
 | RDC | Mur_Maconnerie 0.15 m | 0100HMu0000017817 | no | 5 | 0100Mu_0000017818 | m³ | Mur_Maconnerie
 | RDC | Béton 0.2 m | 0100HMu0000010337 | no | 5 | 0100Mu_0000010338 | m³ | Béton
 | RDC | Béton 0.199994 m | 0100HMu0000013078 | no | 5 | 0100Mu_0000013081 | m³ | Béton
 | RDC | Béton 0.2 m | 0100HMu0000010377 | no | 5 | 0100Mu_0000010380 | m³ | Béton
 | RDC | Béton 0.2 m | 0100HMu0000010366 | no | 5 | 0100Mu_0000010367 | m³ | Béton
 | RDC | Béton 0.2 m | 0100HMu0000010446 | no | 5 | 0100Mu_0000010447 | m³ | Béton
 | RDC | Béton 0.199993 m | 0100HMu0000010390 | no | 5 | 0100Mu_0000010391 | m³ | Béton
 | RDC | Mur_Maconnerie 0.15 m | 0100HMu0000018841 | no | 5 | 0100Mu_0000018842 | m³ | Mur_Maconnerie
 | RDC | Mur_Maconnerie 0.15 m | 0100HMu0000018831 | no | 5 | 0100Mu_0000018832 | m³ | Mur_Maconnerie
 | RDC | Mur_Maconnerie 0.15 m | 0100HMu0000017988 |  | 5 | 0100Mu_0000017989 | m³ | Mur_Maconnerie
 | RDC | Mur_Maconnerie 0.15 m | 0100HMu0000018010 |  | 5 | 0100Mu_0000018011 | m³ | Mur_Maconnerie
 | RDC | Mur_Maconnerie 0.2 m | 0100HMu0000017832 | no | 5 | 0100Mu_0000017833 | m³ | Mur_Maconnerie
 | RDC | Béton 0.2 m | 0100HMu0000010567 | no | 5 | 0100Mu_0000010569 | m³ | Béton
 | RDC | Béton 0.2 m | 0100HMu0000010479 | no | 5 | 0100Mu_0000010480 | m³ | Béton
 | RDC | Béton 0.2 m | 0100HMu0000010466 | no | 5 | 0100Mu_0000010467 | m³ | Béton
 | RDC | Mur_Maconnerie 0.2 m | 0100HMu0000017842 |  | 5 | 0100Mu_0000017843 | m³ | Mur_Maconnerie
 | RDC | Béton 0.2 m | 0100HMu0000010523 | no | 5 | 0100Mu_0000010524 | m³ | Béton
 | RDC | Béton 0.2 m | 0100HMu0000010513 | no | 5 | 0100Mu_0000010514 | m³ | Béton
 | RDC | Mur_Maconnerie 0.15 m | 0100HMu0000018027 |  | 5 | 0100Mu_0000018028 | m³ | Mur_Maconnerie
 | RDC | Béton 0.2 m | 0100HMu0000010583 | no | 5 | 0100Mu_0000010584 | m³ | Béton
 | RDC | Béton 0.2 m | 0100HMu0000013438 | no | 5 | 0100Mu_0000013440 | m³ | Béton
 | RDC | Béton 0.2 m | 0100HMu0000016727 | no | 5 | 0100Mu_0000016731 | m³ | Béton
 | RDC | Béton 0.2 m | 0100HMu0000023586 | no | 5 | 0100Mu_0000023589 | m³ | Béton
 | RDC | Béton 0.2 m | 0100HMu0000010435 | no | 5 | 0100Mu_0000010436 | m³ | Béton
 | RDC | Béton 0.2 m | 0100HMu0000010350 | no | 5 | 0100Mu_0000010351 | m³ | Béton
 | RDC | Béton 0.2 m | 0100HMu0000010355 | no | 5 | 0100Mu_0000010356 | m³ | Béton
 | RDC | Mur_Maconnerie 0.2 m | 0100HMu0000044742 | no | 5 | 0100Mu_0000044749 | m³ | Mur_Maconnerie
 | RDC | Béton 0.2 m | 0100HMu0000023329 | no | 5 | 0100Mu_0000023331 | m³ | Béton
 | RDC | Mur_Maconnerie 0.2 m | 0100HMu0000044690 | no | 5 | 0100Mu_0000044691 | m³ | Mur_Maconnerie
 | RDC | Mur_Maconnerie 0.15 m | 0100HMu0000017999 | no | 5 | 0100Mu_0000018000 | m³ | Mur_Maconnerie
 | RDC | Béton 0.2 m | 0100HMu0000007619 | no | 5 | 0100Mu_0000007620 | m³ | Béton
 | RDC | Béton 0.2 m | 0100HMu0000009441 | no | 5 | 0100Mu_0000009445 | m³ | Béton
 | RDC | Béton 0.2 m | 0100HMu0000010634 | no | 5 | 0100Mu_0000010635 | m³ | Béton
 | RDC | Béton 0.2 m | 0100HMu0000065073 | no | 5 | 0100Mu_0000065113 | m³ | Béton
 | RDC | Béton 0.2 m | 0100HMu0000010172 | no | 5 | 0100Mu_0000010175 | m³ | Béton
 | RDC | Béton 0.2 m | 0100HMu0000007800 | no | 5 | 0100Mu_0000007801 | m³ | Béton
 | RDC | Béton 0.2 m | 0100HMu0000009189 | no | 5 | 0100Mu_0000009190 | m³ | Béton
 | RDC | Béton 0.2 m | 0100HMu0000015268 | no | 5 | 0100Mu_0000015272 | m³ | Béton
 | RDC | Béton 0.2 m | 0100HMu0000007795 | no | 5 | 0100Mu_0000007796 | m³ | Béton
 | RDC | Béton 0.2 m | 0100HMu0000017598 | no | 5 | 0100Mu_0000017599 | m³ | Béton
